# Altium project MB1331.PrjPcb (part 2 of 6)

## Sheet MCU.SchDoc: MCU STM32H7B3LIH6Q
size A3; Date: Not used; ApprovedBy: Not used; CheckedBy: Not used; Author: Not used; CompanyName: STMicroelectronics; DrawnBy: Not used; Engineer: Not used; Organization: Not used; Address1: Not used; Address2: Not used; Address3: Not used; Address4: Not used; DocumentNumber: Not used; Revision: Not used; SheetNumber: 3; SheetTotal: 23

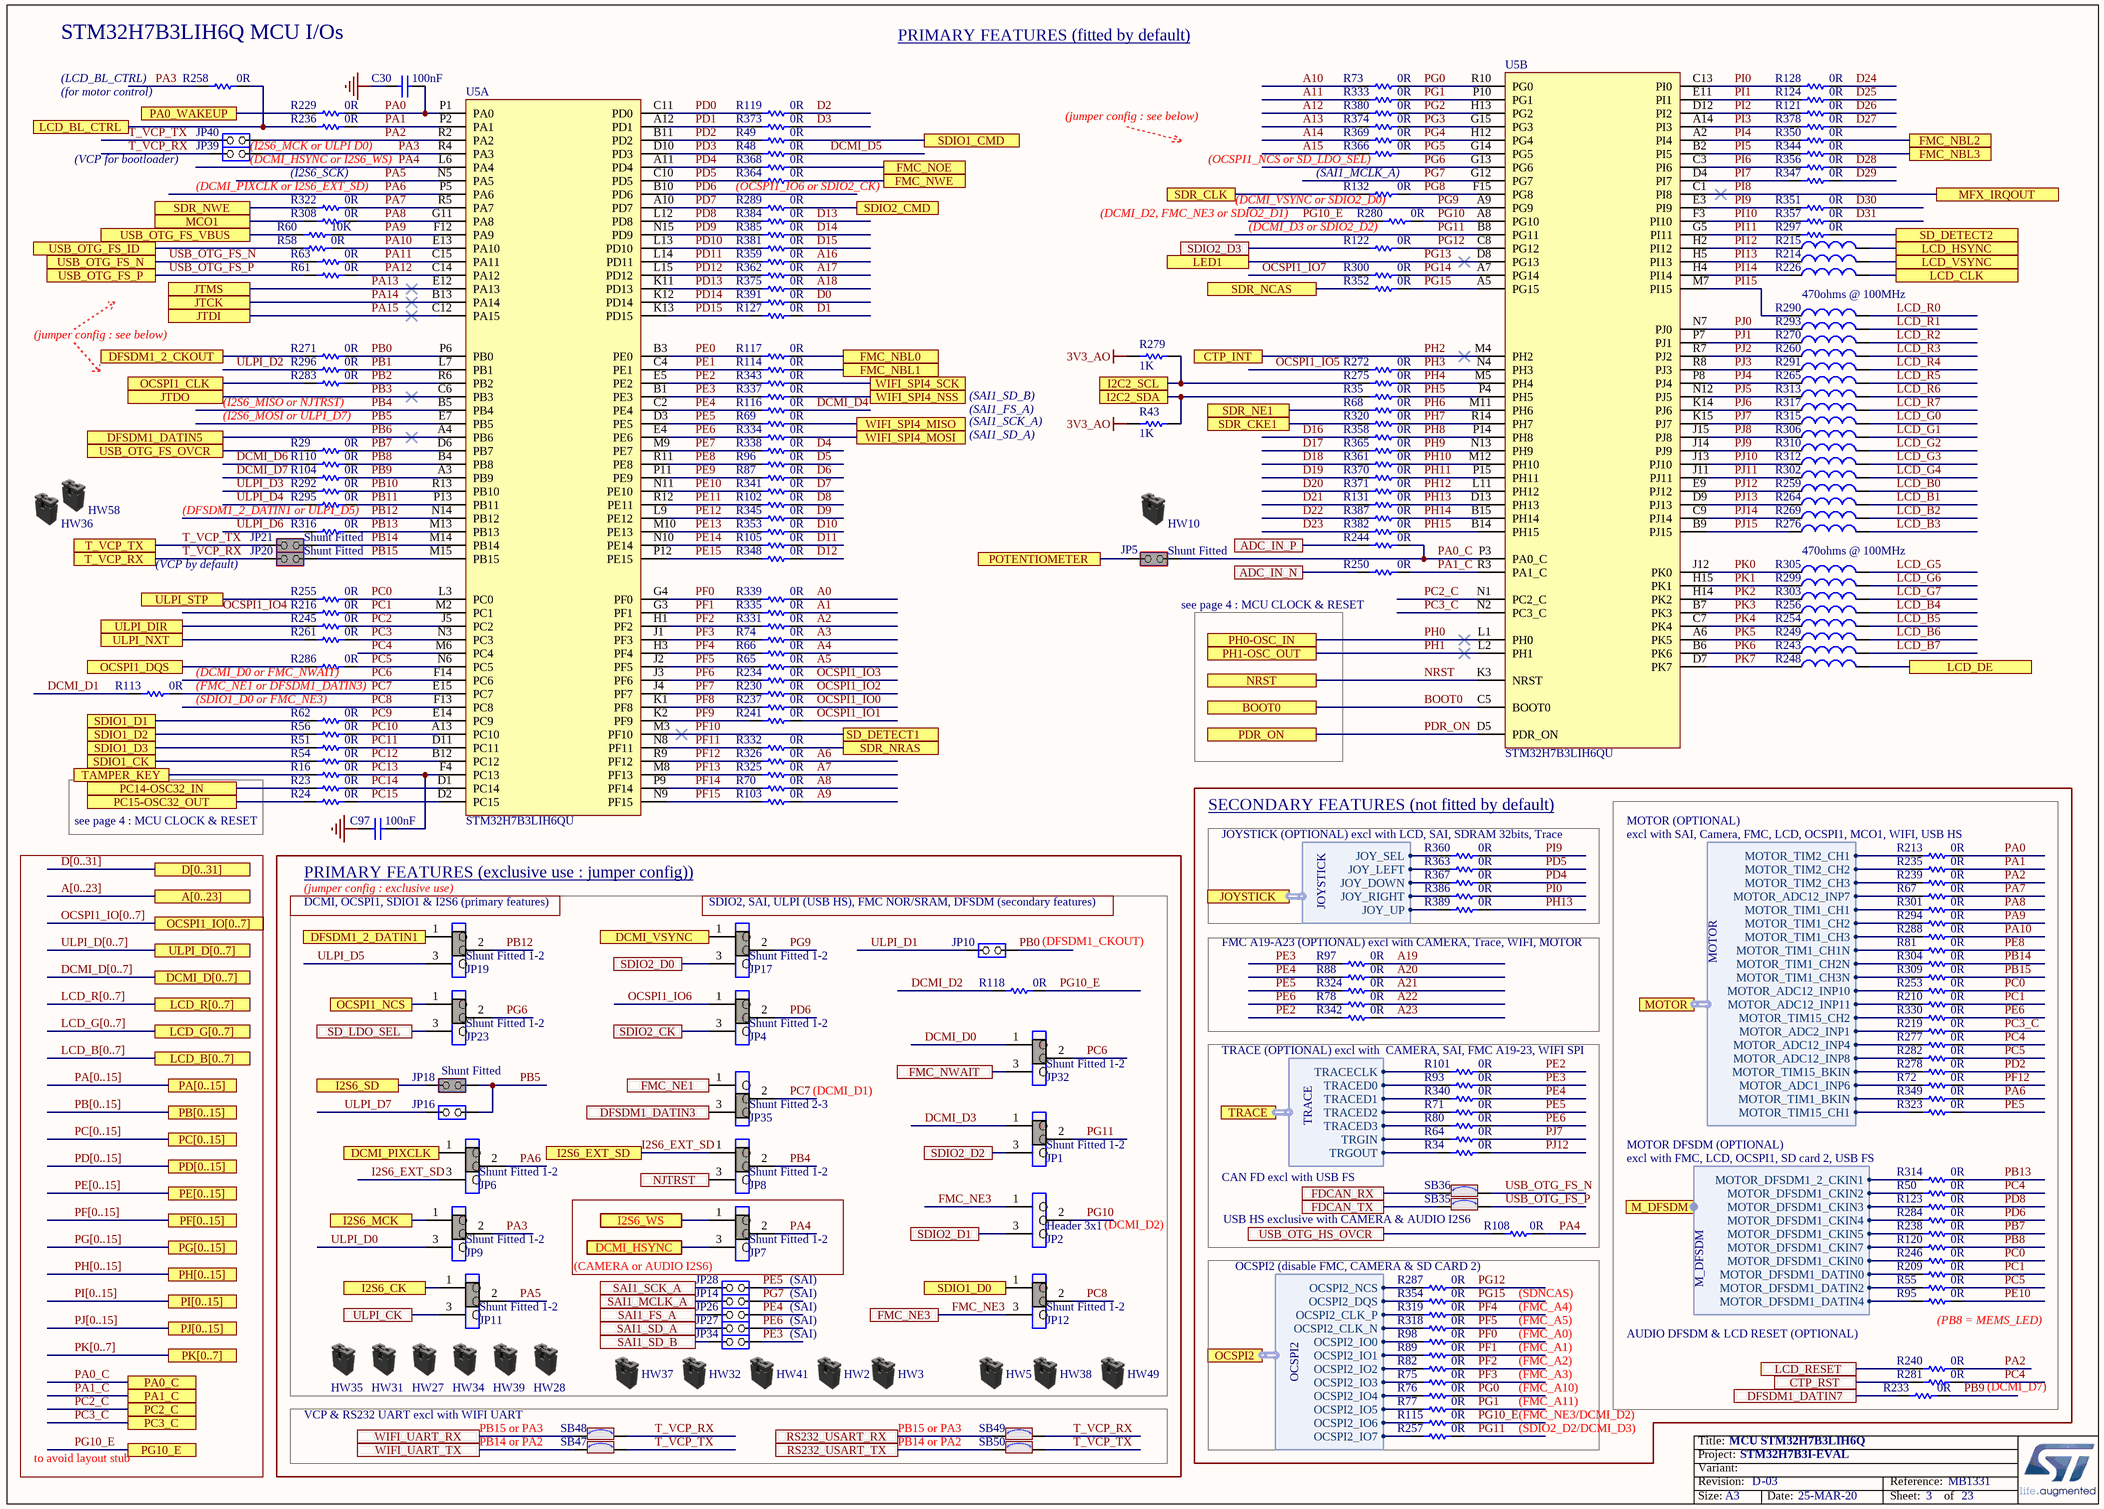
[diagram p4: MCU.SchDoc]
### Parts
C30  value 100nF  [C0402]  (hidden comment: Capacitor)
C97  value 100nF  [C0402]  (hidden comment: Capacitor)
HW2  Shunt Black 2.54mm  (value not drawn)  (mechanical)
HW3  Shunt Black 2.54mm  (value not drawn)  (mechanical)
HW5  Shunt Black 2.54mm  (value not drawn)  (mechanical)
HW10  Shunt Black 2.54mm  (value not drawn)  (mechanical)
HW27  Shunt Black 2.54mm  (value not drawn)  (mechanical)
HW28  Shunt Black 2.54mm  (value not drawn)  (mechanical)
HW31  Shunt Black 2.54mm  (value not drawn)  (mechanical)
HW32  Shunt Black 2.54mm  (value not drawn)  (mechanical)
HW34  Shunt Black 2.54mm  (value not drawn)  (mechanical)
HW35  Shunt Black 2.54mm  (value not drawn)  (mechanical)
HW36  Shunt Black 2.54mm  (value not drawn)  (mechanical)
HW37  Shunt Black 2.54mm  (value not drawn)  (mechanical)
HW38  Shunt Black 2.54mm  (value not drawn)  (mechanical)
HW39  Shunt Black 2.54mm  (value not drawn)  (mechanical)
HW41  Shunt Black 2.54mm  (value not drawn)  (mechanical)
HW49  Shunt Black 2.54mm  (value not drawn)  (mechanical)
HW58  Shunt Black 2.54mm  (value not drawn)  (mechanical)
JP1  value Shunt Fitted 1-2  [CON_SAMTEC_TSW-103-07-F-S]  (hidden comment: Jumper_Header 3x1 Fitted 1-2)
JP2  value Header 3x1  [CON_SAMTEC_TSW-103-07-F-S]  (hidden comment: Jumper_Header 3x1)
JP4  value Shunt Fitted 1-2  [CON_SAMTEC_TSW-103-07-F-S]  (hidden comment: Jumper_Header 3x1 Fitted 1-2)
JP5  value Shunt Fitted  [CON_SAMTEC_TSW-102-07-G-S]  (hidden comment: Jumper_Header 2x1 Fitted)
JP6  value Shunt Fitted 1-2  [CON_SAMTEC_TSW-103-07-F-S]  (hidden comment: Jumper_Header 3x1 Fitted 1-2)
JP7  value Shunt Fitted 1-2  [CON_SAMTEC_TSW-103-07-F-S]  (hidden comment: Jumper_Header 3x1 Fitted 1-2)
JP8  value Shunt Fitted 1-2  [CON_SAMTEC_TSW-103-07-F-S]  (hidden comment: Jumper_Header 3x1 Fitted 1-2)
JP9  value Shunt Fitted 1-2  [CON_SAMTEC_TSW-103-07-F-S]  (hidden comment: Jumper_Header 3x1 Fitted 1-2)
JP10  Jumper_Header 2x1  [CON_SAMTEC_TSW-102-07-G-S]  (value not drawn)
JP11  value Shunt Fitted 1-2  [CON_SAMTEC_TSW-103-07-F-S]  (hidden comment: Jumper_Header 3x1 Fitted 1-2)
JP12  value Shunt Fitted 1-2  [CON_SAMTEC_TSW-103-07-F-S]  (hidden comment: Jumper_Header 3x1 Fitted 1-2)
JP14  Jumper_Header 2x1  [CON_SAMTEC_TSW-102-07-G-S]  (value not drawn)
JP16  Jumper_Header 2x1  [CON_SAMTEC_TSW-102-07-G-S]  (value not drawn)
JP17  value Shunt Fitted 1-2  [CON_SAMTEC_TSW-103-07-F-S]  (hidden comment: Jumper_Header 3x1 Fitted 1-2)
JP18  value Shunt Fitted  [CON_SAMTEC_TSW-102-07-G-S]  (hidden comment: Jumper_Header 2x1 Fitted)
JP19  value Shunt Fitted 1-2  [CON_SAMTEC_TSW-103-07-F-S]  (hidden comment: Jumper_Header 3x1 Fitted 1-2)
JP20  value Shunt Fitted  [CON_SAMTEC_TSW-102-07-G-S]  (hidden comment: Jumper_Header 2x1 Fitted)
JP21  value Shunt Fitted  [CON_SAMTEC_TSW-102-07-G-S]  (hidden comment: Jumper_Header 2x1 Fitted)
JP23  value Shunt Fitted 1-2  [CON_SAMTEC_TSW-103-07-F-S]  (hidden comment: Jumper_Header 3x1 Fitted 1-2)
JP26  Jumper_Header 2x1  [CON_SAMTEC_TSW-102-07-G-S]  (value not drawn)
JP27  Jumper_Header 2x1  [CON_SAMTEC_TSW-102-07-G-S]  (value not drawn)
JP28  Jumper_Header 2x1  [CON_SAMTEC_TSW-102-07-G-S]  (value not drawn)
JP32  value Shunt Fitted 1-2  [CON_SAMTEC_TSW-103-07-F-S]  (hidden comment: Jumper_Header 3x1 Fitted 1-2)
JP34  Jumper_Header 2x1  [CON_SAMTEC_TSW-102-07-G-S]  (value not drawn)
JP35  value Shunt Fitted 2-3  [CON_SAMTEC_TSW-103-07-F-S]  (hidden comment: Jumper_Header 3x1 Fitted 2-3)
JP39  Jumper_Header 2x1  [CON_SAMTEC_TSW-102-07-G-S]  (value not drawn)
JP40  Jumper_Header 2x1  [CON_SAMTEC_TSW-102-07-G-S]  (value not drawn)
R16  value 0R  [R0402]  (hidden comment: Resistor)
R23  value 0R  [R0402]  (hidden comment: Resistor)
R24  value 0R  [R0402]  (hidden comment: Resistor)
R29  value 0R  [R0402]  (hidden comment: Resistor)
R34  value 0R  [R0402]  (hidden comment: Resistor)
R35  value 0R  [R0603]  (hidden comment: Resistor)
R43  value 1K  [R0402]  (hidden comment: Resistor)
R48  value 0R  [R0402]  (hidden comment: Resistor)
R49  value 0R  [R0402]  (hidden comment: Resistor)
R50  value 0R  [R0603]  (hidden comment: Resistor)
R51  value 0R  [R0402]  (hidden comment: Resistor)
R54  value 0R  [R0402]  (hidden comment: Resistor)
R55  value 0R  [R0603]  (hidden comment: Resistor)
R56  value 0R  [R0402]  (hidden comment: Resistor)
R58  value 0R  [R0402]  (hidden comment: Resistor)
R60  value 10K  [R0402]  (hidden comment: Resistor)
R61  value 0R  [R0402]  (hidden comment: Resistor)
R62  value 0R  [R0402]  (hidden comment: Resistor)
R63  value 0R  [R0402]  (hidden comment: Resistor)
R64  value 0R  [R0402]  (hidden comment: Resistor)
R65  value 0R  [R0402]  (hidden comment: Resistor)
R66  value 0R  [R0402]  (hidden comment: Resistor)
R67  value 0R  [R0603]  (hidden comment: Resistor)
R68  value 0R  [R0402]  (hidden comment: Resistor)
R69  value 0R  [R0402]  (hidden comment: Resistor)
R70  value 0R  [R0402]  (hidden comment: Resistor)
R71  value 0R  [R0402]  (hidden comment: Resistor)
R72  value 0R  [R0603]  (hidden comment: Resistor)
R73  value 0R  [R0402]  (hidden comment: Resistor)
R74  value 0R  [R0402]  (hidden comment: Resistor)
R75  value 0R  [R0402]  (hidden comment: Resistor)
R76  value 0R  [R0402]  (hidden comment: Resistor)
R77  value 0R  [R0402]  (hidden comment: Resistor)
R78  value 0R  [R0402]  (hidden comment: Resistor)
R80  value 0R  [R0402]  (hidden comment: Resistor)
R81  value 0R  [R0603]  (hidden comment: Resistor)
R82  value 0R  [R0402]  (hidden comment: Resistor)
R87  value 0R  [R0402]  (hidden comment: Resistor)
R88  value 0R  [R0402]  (hidden comment: Resistor)
R89  value 0R  [R0402]  (hidden comment: Resistor)
R93  value 0R  [R0402]  (hidden comment: Resistor)
R95  value 0R  [R0402]  (hidden comment: Resistor)
R96  value 0R  [R0402]  (hidden comment: Resistor)
R97  value 0R  [R0402]  (hidden comment: Resistor)
R98  value 0R  [R0402]  (hidden comment: Resistor)
R101  value 0R  [R0402]  (hidden comment: Resistor)
R102  value 0R  [R0402]  (hidden comment: Resistor)
R103  value 0R  [R0402]  (hidden comment: Resistor)
R104  value 0R  [R0402]  (hidden comment: Resistor)
R105  value 0R  [R0402]  (hidden comment: Resistor)
R108  value 0R  [R0402]  (hidden comment: Resistor)
R110  value 0R  [R0402]  (hidden comment: Resistor)
R113  value 0R  [R0402]  (hidden comment: Resistor)
R114  value 0R  [R0402]  (hidden comment: Resistor)
R115  value 0R  [R0402]  (hidden comment: Resistor)
R116  value 0R  [R0402]  (hidden comment: Resistor)
R117  value 0R  [R0402]  (hidden comment: Resistor)
R118  value 0R  [R0402]  (hidden comment: Resistor)
R119  value 0R  [R0402]  (hidden comment: Resistor)
R120  value 0R  [R0603]  (hidden comment: Resistor)
R121  value 0R  [R0402]  (hidden comment: Resistor)
R122  value 0R  [R0402]  (hidden comment: Resistor)
R123  value 0R  [R0603]  (hidden comment: Resistor)
R124  value 0R  [R0402]  (hidden comment: Resistor)
R127  value 0R  [R0402]  (hidden comment: Resistor)
R128  value 0R  [R0402]  (hidden comment: Resistor)
R131  value 0R  [R0402]  (hidden comment: Resistor)
R132  value 0R  [R0402]  (hidden comment: Resistor)
R209  value 0R  [R0603]  (hidden comment: Resistor)
R210  value 0R  [R0603]  (hidden comment: Resistor)
R213  value 0R  [R0603]  (hidden comment: Resistor)
R214  Inductor  [IND_0402_MURATA_BLM15H_H0P5]  (value not drawn)
R215  Inductor  [IND_0402_MURATA_BLM15H_H0P5]  (value not drawn)
R216  value 0R  [R0402]  (hidden comment: Resistor)
R219  value 0R  [R0603]  (hidden comment: Resistor)
R226  Inductor  [IND_0402_MURATA_BLM15H_H0P5]  (value not drawn)
R229  value 0R  [R0402]  (hidden comment: Resistor)
R230  value 0R  [R0402]  (hidden comment: Resistor)
R233  value 0R  [R0402]  (hidden comment: Resistor)
R234  value 0R  [R0402]  (hidden comment: Resistor)
R235  value 0R  [R0603]  (hidden comment: Resistor)
R236  value 0R  [R0402]  (hidden comment: Resistor)
R237  value 0R  [R0402]  (hidden comment: Resistor)
R238  value 0R  [R0603]  (hidden comment: Resistor)
R239  value 0R  [R0603]  (hidden comment: Resistor)
R240  value 0R  [R0402]  (hidden comment: Resistor)
R241  value 0R  [R0402]  (hidden comment: Resistor)
R243  Inductor  [IND_0402_MURATA_BLM15H_H0P5]  (value not drawn)
R244  value 0R  [R0402]  (hidden comment: Resistor)
R245  value 0R  [R0402]  (hidden comment: Resistor)
R246  value 0R  [R0603]  (hidden comment: Resistor)
R248  Inductor  [IND_0402_MURATA_BLM15H_H0P5]  (value not drawn)
R249  Inductor  [IND_0402_MURATA_BLM15H_H0P5]  (value not drawn)
R250  value 0R  [R0402]  (hidden comment: Resistor)
R253  value 0R  [R0603]  (hidden comment: Resistor)
R254  Inductor  [IND_0402_MURATA_BLM15H_H0P5]  (value not drawn)
R255  value 0R  [R0402]  (hidden comment: Resistor)
R256  Inductor  [IND_0402_MURATA_BLM15H_H0P5]  (value not drawn)
R257  value 0R  [R0402]  (hidden comment: Resistor)
R258  value 0R  [R0402]  (hidden comment: Resistor)
R259  Inductor  [IND_0402_MURATA_BLM15H_H0P5]  (value not drawn)
R260  Inductor  [IND_0402_MURATA_BLM15H_H0P5]  (value not drawn)
R261  value 0R  [R0402]  (hidden comment: Resistor)
R264  Inductor  [IND_0402_MURATA_BLM15H_H0P5]  (value not drawn)
R265  Inductor  [IND_0402_MURATA_BLM15H_H0P5]  (value not drawn)
R269  Inductor  [IND_0402_MURATA_BLM15H_H0P5]  (value not drawn)
R270  Inductor  [IND_0402_MURATA_BLM15H_H0P5]  (value not drawn)
R271  value 0R  [R0402]  (hidden comment: Resistor)
R272  value 0R  [R0402]  (hidden comment: Resistor)
R275  value 0R  [R0603]  (hidden comment: Resistor)
R276  Inductor  [IND_0402_MURATA_BLM15H_H0P5]  (value not drawn)
R277  value 0R  [R0603]  (hidden comment: Resistor)
R278  value 0R  [R0603]  (hidden comment: Resistor)
R279  value 1K  [R0402]  (hidden comment: Resistor)
R280  value 0R  [R0402]  (hidden comment: Resistor)
R281  value 0R  [R0402]  (hidden comment: Resistor)
R282  value 0R  [R0603]  (hidden comment: Resistor)
R283  value 0R  [R0402]  (hidden comment: Resistor)
R284  value 0R  [R0603]  (hidden comment: Resistor)
R286  value 0R  [R0402]  (hidden comment: Resistor)
R287  value 0R  [R0402]  (hidden comment: Resistor)
R288  value 0R  [R0603]  (hidden comment: Resistor)
R289  value 0R  [R0402]  (hidden comment: Resistor)
R290  value 470ohms @ 100MHz  [IND_0402_MURATA_BLM15H_H0P5]  (hidden comment: Inductor)
R291  Inductor  [IND_0402_MURATA_BLM15H_H0P5]  (value not drawn)
R292  value 0R  [R0402]  (hidden comment: Resistor)
R293  Inductor  [IND_0402_MURATA_BLM15H_H0P5]  (value not drawn)
R294  value 0R  [R0603]  (hidden comment: Resistor)
R295  value 0R  [R0402]  (hidden comment: Resistor)
R296  value 0R  [R0402]  (hidden comment: Resistor)
R297  value 0R  [R0402]  (hidden comment: Resistor)
R299  Inductor  [IND_0402_MURATA_BLM15H_H0P5]  (value not drawn)
R300  value 0R  [R0402]  (hidden comment: Resistor)
R301  value 0R  [R0603]  (hidden comment: Resistor)
R302  Inductor  [IND_0402_MURATA_BLM15H_H0P5]  (value not drawn)
R303  Inductor  [IND_0402_MURATA_BLM15H_H0P5]  (value not drawn)
R304  value 0R  [R0603]  (hidden comment: Resistor)
R305  value 470ohms @ 100MHz  [IND_0402_MURATA_BLM15H_H0P5]  (hidden comment: Inductor)
R306  Inductor  [IND_0402_MURATA_BLM15H_H0P5]  (value not drawn)
R308  value 0R  [R0402]  (hidden comment: Resistor)
R309  value 0R  [R0603]  (hidden comment: Resistor)
R310  Inductor  [IND_0402_MURATA_BLM15H_H0P5]  (value not drawn)
R312  Inductor  [IND_0402_MURATA_BLM15H_H0P5]  (value not drawn)
R313  Inductor  [IND_0402_MURATA_BLM15H_H0P5]  (value not drawn)
R314  value 0R  [R0603]  (hidden comment: Resistor)
R315  Inductor  [IND_0402_MURATA_BLM15H_H0P5]  (value not drawn)
R316  value 0R  [R0402]  (hidden comment: Resistor)
R317  Inductor  [IND_0402_MURATA_BLM15H_H0P5]  (value not drawn)
R318  value 0R  [R0402]  (hidden comment: Resistor)
R319  value 0R  [R0402]  (hidden comment: Resistor)
R320  value 0R  [R0402]  (hidden comment: Resistor)
R322  value 0R  [R0402]  (hidden comment: Resistor)
R323  value 0R  [R0603]  (hidden comment: Resistor)
R324  value 0R  [R0402]  (hidden comment: Resistor)
R325  value 0R  [R0402]  (hidden comment: Resistor)
R326  value 0R  [R0402]  (hidden comment: Resistor)
R330  value 0R  [R0603]  (hidden comment: Resistor)
R331  value 0R  [R0402]  (hidden comment: Resistor)
R332  value 0R  [R0402]  (hidden comment: Resistor)
R333  value 0R  [R0402]  (hidden comment: Resistor)
R334  value 0R  [R0402]  (hidden comment: Resistor)
R335  value 0R  [R0402]  (hidden comment: Resistor)
R337  value 0R  [R0402]  (hidden comment: Resistor)
R338  value 0R  [R0402]  (hidden comment: Resistor)
R339  value 0R  [R0402]  (hidden comment: Resistor)
R340  value 0R  [R0402]  (hidden comment: Resistor)
R341  value 0R  [R0402]  (hidden comment: Resistor)
R342  value 0R  [R0402]  (hidden comment: Resistor)
R343  value 0R  [R0402]  (hidden comment: Resistor)
R344  value 0R  [R0402]  (hidden comment: Resistor)
R345  value 0R  [R0402]  (hidden comment: Resistor)
R347  value 0R  [R0402]  (hidden comment: Resistor)
R348  value 0R  [R0402]  (hidden comment: Resistor)
R349  value 0R  [R0402]  (hidden comment: Resistor)
R350  value 0R  [R0402]  (hidden comment: Resistor)
R351  value 0R  [R0402]  (hidden comment: Resistor)
R352  value 0R  [R0402]  (hidden comment: Resistor)
R353  value 0R  [R0402]  (hidden comment: Resistor)
R354  value 0R  [R0402]  (hidden comment: Resistor)
R356  value 0R  [R0402]  (hidden comment: Resistor)
R357  value 0R  [R0402]  (hidden comment: Resistor)
R358  value 0R  [R0402]  (hidden comment: Resistor)
R359  value 0R  [R0402]  (hidden comment: Resistor)
R360  value 0R  [R0402]  (hidden comment: Resistor)
R361  value 0R  [R0402]  (hidden comment: Resistor)
R362  value 0R  [R0402]  (hidden comment: Resistor)
R363  value 0R  [R0402]  (hidden comment: Resistor)
R364  value 0R  [R0402]  (hidden comment: Resistor)
R365  value 0R  [R0402]  (hidden comment: Resistor)
R366  value 0R  [R0402]  (hidden comment: Resistor)
R367  value 0R  [R0402]  (hidden comment: Resistor)
R368  value 0R  [R0402]  (hidden comment: Resistor)
R369  value 0R  [R0402]  (hidden comment: Resistor)
R370  value 0R  [R0402]  (hidden comment: Resistor)
R371  value 0R  [R0402]  (hidden comment: Resistor)
R373  value 0R  [R0402]  (hidden comment: Resistor)
R374  value 0R  [R0402]  (hidden comment: Resistor)
R375  value 0R  [R0402]  (hidden comment: Resistor)
R378  value 0R  [R0402]  (hidden comment: Resistor)
R380  value 0R  [R0402]  (hidden comment: Resistor)
R381  value 0R  [R0402]  (hidden comment: Resistor)
R382  value 0R  [R0402]  (hidden comment: Resistor)
R384  value 0R  [R0402]  (hidden comment: Resistor)
R385  value 0R  [R0402]  (hidden comment: Resistor)
R386  value 0R  [R0402]  (hidden comment: Resistor)
R387  value 0R  [R0402]  (hidden comment: Resistor)
R389  value 0R  [R0402]  (hidden comment: Resistor)
R391  value 0R  [R0402]  (hidden comment: Resistor)
SB35  SB_ON  [SOLDER-BRIDGE_R0603-0R]  (value not drawn)
SB36  SB_ON  [SOLDER-BRIDGE_R0603-0R]  (value not drawn)
SB47  SB_ON  [SOLDER-BRIDGE_R0402-0R]  (value not drawn)
SB48  SB_ON  [SOLDER-BRIDGE_R0402-0R]  (value not drawn)
SB49  SB_ON  [SOLDER-BRIDGE_R0402-0R]  (value not drawn)
SB50  SB_ON  [SOLDER-BRIDGE_R0402-0R]  (value not drawn)
U5  value STM32H7B3LIH6QU  [ICC_TFBGA225_13X13_STM32H7B3NIH6Q_P080__SOCKET_IRONWOOD_CS1222291MF_REV-A_WITHOUT-3D-SOCKET]  (hidden comment: STM32H7B3NIH6Q)  (parts A,B of 3)

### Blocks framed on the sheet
SECONDARY FEATURES (not fitted by default): R360 R363 R367 R386 R389
PRIMARY FEATURES (exclusive use : jumper config)): HW2 HW3 HW5 HW27 HW28 HW31 HW32 HW34 HW35 HW37-HW39 HW41 HW49 JP1 JP2 JP4 JP6 JP8-JP12 JP14 JP16-JP19 JP23 JP26-JP28 JP32 JP34 JP35 R118
FMC A19-A23 (OPTIONAL) excl with CAMERA, Trace, WIFI, MOTOR: R78 R88 R97 R324 R342
(CAMERA or AUDIO I2S6): JP7

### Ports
A[0..23], ADC_IN_N, ADC_IN_P, BOOT0, CTP_INT, CTP_RST, D[0..31], DCMI_D[0..7], DCMI_HSYNC, DCMI_PIXCLK, DCMI_VSYNC, DFSDM1_2_CKOUT, DFSDM1_2_DATIN1, DFSDM1_DATIN3, DFSDM1_DATIN5, DFSDM1_DATIN7, FDCAN_RX, FDCAN_TX, FMC_NBL0, FMC_NBL1, FMC_NBL2, FMC_NBL3, FMC_NE1, FMC_NE3, FMC_NOE, FMC_NWAIT, FMC_NWE, I2C2_SCL, I2C2_SDA, I2S6_CK, I2S6_EXT_SD, I2S6_MCK, I2S6_SD, I2S6_WS, JOYSTICK (harness JOYSTICK), JTCK, JTDI, JTDO, JTMS, LCD_B[0..7], LCD_BL_CTRL, LCD_CLK, LCD_DE, LCD_G[0..7], LCD_HSYNC, LCD_R[0..7], LCD_RESET, LCD_VSYNC, LED1, M_DFSDM (harness M_DFSDM), MCO1, MFX_IRQOUT, MOTOR (harness MOTOR), NJTRST, NRST, OCSPI1_CLK, OCSPI1_DQS, OCSPI1_IO[0..7], OCSPI1_NCS, OCSPI2 (harness OCSPI2), PA0_C, PA0_WAKEUP, PA1_C, PA[0..15], PB[0..15], PC2_C, PC3_C, PC14-OSC32_IN, PC15-OSC32_OUT, PC[0..15], PD[0..15], PDR_ON, PE[0..15], PF[0..15], PG10_E, PG[0..15], PH0-OSC_IN, PH1-OSC_OUT, PH[0..15], PI[0..15], PJ[0..15], PK[0..7], POTENTIOMETER, RS232_USART_RX, RS232_USART_TX, SAI1_FS_A, SAI1_MCLK_A, SAI1_SCK_A, SAI1_SD_A, SAI1_SD_B, SD_DETECT1, SD_DETECT2, SD_LDO_SEL, SDIO1_CK, SDIO1_CMD, SDIO1_D0, SDIO1_D1, SDIO1_D2, SDIO1_D3, SDIO2_CK, SDIO2_CMD, SDIO2_D0, SDIO2_D1, SDIO2_D2, SDIO2_D3, SDR_CKE1, SDR_CLK, SDR_NCAS, SDR_NE1, SDR_NRAS, SDR_NWE, T_VCP_RX, T_VCP_TX, TAMPER_KEY, TRACE (harness TRACE), ULPI_CK, ULPI_D[0..7], ULPI_DIR, ULPI_NXT, ULPI_STP, USB_OTG_FS_ID, USB_OTG_FS_N, USB_OTG_FS_OVCR, USB_OTG_FS_P, USB_OTG_FS_VBUS, USB_OTG_HS_OVCR, WIFI_SPI4_MISO, WIFI_SPI4_MOSI, WIFI_SPI4_NSS, WIFI_SPI4_SCK, WIFI_UART_RX, WIFI_UART_TX

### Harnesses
MOTOR: MOTOR_TIM2_CH1, MOTOR_TIM2_CH2, MOTOR_TIM2_CH3, MOTOR_ADC12_INP7, MOTOR_TIM1_CH1, MOTOR_TIM1_CH2, MOTOR_TIM1_CH3, MOTOR_TIM1_CH1N, MOTOR_TIM1_CH2N, MOTOR_TIM1_CH3N, MOTOR_ADC12_INP10, MOTOR_ADC12_INP11, MOTOR_TIM15_CH2, MOTOR_ADC2_INP1, MOTOR_ADC12_INP4, MOTOR_ADC12_INP8, MOTOR_TIM15_BKIN, MOTOR_ADC1_INP6, MOTOR_TIM1_BKIN, MOTOR_TIM15_CH1
OCSPI2: OCSPI2_NCS, OCSPI2_DQS, OCSPI2_CLK_P, OCSPI2_CLK_N, OCSPI2_IO0, OCSPI2_IO1, OCSPI2_IO2, OCSPI2_IO3, OCSPI2_IO4, OCSPI2_IO5, OCSPI2_IO6, OCSPI2_IO7
TRACE: TRACECLK, TRACED0, TRACED1, TRACED2, TRACED3, TRGIN, TRGOUT
JOYSTICK: JOY_SEL, JOY_LEFT, JOY_DOWN, JOY_RIGHT, JOY_UP
M_DFSDM: MOTOR_DFSDM1_2_CKIN1, MOTOR_DFSDM1_CKIN3, MOTOR_DFSDM1_CKIN5, MOTOR_DFSDM1_CKIN7, MOTOR_DFSDM1_CKIN2, MOTOR_DFSDM1_CKIN4, MOTOR_DFSDM1_CKIN0, MOTOR_DFSDM1_DATIN0, MOTOR_DFSDM1_DATIN2, MOTOR_DFSDM1_DATIN4

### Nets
3V3_AO: R43.1 R279.1
GND: C30.2 C97.2
A0: R339.2
A1: R335.2
A2: R331.2
A3: R74.2
A4: R66.2
A5: R65.2
A6: R326.2
A7: R325.2
A8: R70.2
A9: R103.2
A10: R73.1
A11: R333.1
A12: R380.1
A13: R374.1
A14: R369.1
A15: R366.1
A16: R359.2
A17: R362.2
A18: R375.2
A19: R97.2
A20: R88.2
A21: R324.2
A22: R78.2
A23: R342.2
ADC_IN_N: R250.1 ; port ADC_IN_N
ADC_IN_P: R244.1 ; port ADC_IN_P
BOOT0: U5.C5(BOOT0) ; port BOOT0
CTP_RST: R281.1 ; port CTP_RST
D0: R391.2
D1: R127.2
D2: R119.2
D3: R373.2
D4: R338.2
D5: R96.2
D6: R87.2
D7: R341.2
D8: R102.2
D9: R345.2
D10: R353.2
D11: R105.2
D12: R348.2
D13: R384.2
D14: R385.2
D15: R381.2
D16: R358.1
D17: R365.1
D18: R361.1
D19: R370.1
D20: R371.1
D21: R131.1
D22: R387.1
D23: R382.1
D24: R128.2
D25: R124.1
D26: R121.1
D27: R378.1
D28: R356.1
D29: R347.1
D30: R351.2
D31: R357.2
DCMI_D0: JP32.1
DCMI_D1: R113.1
DCMI_D2: R118.1
DCMI_D3: JP1.1
DCMI_D4: R116.1
DCMI_D5: R48.2
DCMI_D6: R110.2
DCMI_D7: R104.1
DCMI_HSYNC: JP7.3 ; port DCMI_HSYNC
DCMI_PIXCLK: JP6.1 ; port DCMI_PIXCLK
DCMI_VSYNC: JP17.1 ; port DCMI_VSYNC
DFSDM1_2_CKOUT: R271.1 ; port DFSDM1_2_CKOUT
DFSDM1_2_DATIN1: JP19.1 ; port DFSDM1_2_DATIN1
DFSDM1_DATIN3: JP35.3 ; port DFSDM1_DATIN3
DFSDM1_DATIN7: R233.2 ; port DFSDM1_DATIN7
FDCAN_RX: SB36.1 ; port FDCAN_RX
FDCAN_TX: SB35.1 ; port FDCAN_TX
FMC_NBL0: R117.2 ; port FMC_NBL0
FMC_NBL1: R114.2 ; port FMC_NBL1
FMC_NBL2: R350.2 ; port FMC_NBL2
FMC_NBL3: R344.2 ; port FMC_NBL3
FMC_NE1: JP35.1 ; port FMC_NE1
FMC_NE3: JP2.1 JP12.3 ; port FMC_NE3
FMC_NOE: R368.2 ; port FMC_NOE
FMC_NWAIT: JP32.3 ; port FMC_NWAIT
FMC_NWE: R364.2 ; port FMC_NWE
I2C2_SCL: R275.1 R279.2 ; port I2C2_SCL
I2C2_SDA: R35.1 R43.2 ; port I2C2_SDA
I2S6_CK: JP11.1 ; port I2S6_CK
I2S6_EXT_SD: JP6.3 JP8.1 ; port I2S6_EXT_SD
I2S6_MCK: JP9.1 ; port I2S6_MCK
I2S6_SD: JP18.2(NO) ; port I2S6_SD
I2S6_WS: JP7.1 ; port I2S6_WS
LCD_B0: R259.2
LCD_B1: R264.2
LCD_B2: R269.2
LCD_B3: R276.2
LCD_B4: R256.2
LCD_B5: R254.2
LCD_B6: R249.2
LCD_B7: R243.2
LCD_BL_CTRL: R236.1 R258.2 ; port LCD_BL_CTRL
LCD_CLK: R226.2 ; port LCD_CLK
LCD_DE: R248.2 ; port LCD_DE
LCD_G0: R315.2
LCD_G1: R306.2
LCD_G2: R310.2
LCD_G3: R312.2
LCD_G4: R302.2
LCD_G5: R305.2
LCD_G6: R299.2
LCD_G7: R303.2
LCD_HSYNC: R215.2 ; port LCD_HSYNC
LCD_R0: R290.2
LCD_R1: R293.2
LCD_R2: R270.2
LCD_R3: R260.2
LCD_R4: R291.2
LCD_R5: R265.2
LCD_R6: R313.2
LCD_R7: R317.2
LCD_RESET: R240.1 ; port LCD_RESET
LCD_VSYNC: R214.2 ; port LCD_VSYNC
MCO1: R308.1 ; port MCO1
MOTOR_ADC1_INP6: R72.1 ; port MOTOR.MOTOR_ADC1_INP6
MOTOR_ADC2_INP1: R219.1 ; port MOTOR.MOTOR_ADC2_INP1
MOTOR_ADC12_INP4: R277.1 ; port MOTOR.MOTOR_ADC12_INP4
MOTOR_ADC12_INP7: R67.1 ; port MOTOR.MOTOR_ADC12_INP7
MOTOR_ADC12_INP8: R282.1 ; port MOTOR.MOTOR_ADC12_INP8
MOTOR_ADC12_INP10: R253.1 ; port MOTOR.MOTOR_ADC12_INP10
MOTOR_ADC12_INP11: R210.1 ; port MOTOR.MOTOR_ADC12_INP11
MOTOR_DFSDM1_2_CKIN1: R314.1 ; port M_DFSDM.MOTOR_DFSDM1_2_CKIN1
MOTOR_DFSDM1_CKIN0: R246.1 ; port M_DFSDM.MOTOR_DFSDM1_CKIN0
MOTOR_DFSDM1_CKIN2: R50.1 ; port M_DFSDM.MOTOR_DFSDM1_CKIN2
MOTOR_DFSDM1_CKIN3: R123.1 ; port M_DFSDM.MOTOR_DFSDM1_CKIN3
MOTOR_DFSDM1_CKIN4: R284.1 ; port M_DFSDM.MOTOR_DFSDM1_CKIN4
MOTOR_DFSDM1_CKIN5: R238.1 ; port M_DFSDM.MOTOR_DFSDM1_CKIN5
MOTOR_DFSDM1_CKIN7: R120.1 ; port M_DFSDM.MOTOR_DFSDM1_CKIN7
MOTOR_DFSDM1_DATIN0: R209.1 ; port M_DFSDM.MOTOR_DFSDM1_DATIN0
MOTOR_DFSDM1_DATIN2: R55.1 ; port M_DFSDM.MOTOR_DFSDM1_DATIN2
MOTOR_DFSDM1_DATIN4: R95.1 ; port M_DFSDM.MOTOR_DFSDM1_DATIN4
MOTOR_TIM1_BKIN: R349.1 ; port MOTOR.MOTOR_TIM1_BKIN
MOTOR_TIM1_CH1: R301.1 ; port MOTOR.MOTOR_TIM1_CH1
MOTOR_TIM1_CH1N: R81.1 ; port MOTOR.MOTOR_TIM1_CH1N
MOTOR_TIM1_CH2: R294.1 ; port MOTOR.MOTOR_TIM1_CH2
MOTOR_TIM1_CH2N: R304.1 ; port MOTOR.MOTOR_TIM1_CH2N
MOTOR_TIM1_CH3: R288.1 ; port MOTOR.MOTOR_TIM1_CH3
MOTOR_TIM1_CH3N: R309.1 ; port MOTOR.MOTOR_TIM1_CH3N
MOTOR_TIM2_CH1: R213.1 ; port MOTOR.MOTOR_TIM2_CH1
MOTOR_TIM2_CH2: R235.1 ; port MOTOR.MOTOR_TIM2_CH2
MOTOR_TIM2_CH3: R239.1 ; port MOTOR.MOTOR_TIM2_CH3
MOTOR_TIM15_BKIN: R278.1 ; port MOTOR.MOTOR_TIM15_BKIN
MOTOR_TIM15_CH1: R323.1 ; port MOTOR.MOTOR_TIM15_CH1
MOTOR_TIM15_CH2: R330.1 ; port MOTOR.MOTOR_TIM15_CH2
NJTRST: JP8.3 ; port NJTRST
NRST: U5.K3(NRST) ; port NRST
OCSPI1_CLK: R283.1 ; port OCSPI1_CLK
OCSPI1_DQS: R286.1 ; port OCSPI1_DQS
OCSPI1_IO0: R237.2
OCSPI1_IO1: R241.2
OCSPI1_IO2: R230.2
OCSPI1_IO3: R234.2
OCSPI1_IO4: R216.1
OCSPI1_IO5: R272.1
OCSPI1_IO6: JP4.1
OCSPI1_IO7: R300.1
OCSPI1_NCS: JP23.1 ; port OCSPI1_NCS
OCSPI2_CLK_N: R318.1 ; port OCSPI2.OCSPI2_CLK_N
OCSPI2_CLK_P: R319.1 ; port OCSPI2.OCSPI2_CLK_P
OCSPI2_DQS: R354.1 ; port OCSPI2.OCSPI2_DQS
OCSPI2_IO0: R98.1 ; port OCSPI2.OCSPI2_IO0
OCSPI2_IO1: R89.1 ; port OCSPI2.OCSPI2_IO1
OCSPI2_IO2: R82.1 ; port OCSPI2.OCSPI2_IO2
OCSPI2_IO3: R75.1 ; port OCSPI2.OCSPI2_IO3
OCSPI2_IO4: R76.1 ; port OCSPI2.OCSPI2_IO4
OCSPI2_IO5: R77.1 ; port OCSPI2.OCSPI2_IO5
OCSPI2_IO6: R115.1 ; port OCSPI2.OCSPI2_IO6
OCSPI2_IO7: R257.1 ; port OCSPI2.OCSPI2_IO7
OCSPI2_NCS: R287.1 ; port OCSPI2.OCSPI2_NCS
PA0: C30.1 R213.2 R229.2 U5.P1(PA0)
PA0_C: JP5.2(NO) R244.2 U5.P3(PA0_C) ; port PA0_C
PA0_WAKEUP: R229.1 ; port PA0_WAKEUP
PA1: R235.2 R236.2 U5.P2(PA1)
PA1_C: R250.2 U5.R3(PA1_C) ; port PA1_C
PA2: JP40.2(NO) R239.2 R240.2 U5.R2(PA2)
PA3: JP9.2 JP39.2(NO) R258.1 U5.R4(PA3)
PA4: JP7.2 R108.2 U5.L6(PA4)
PA5: JP11.2 U5.N5(PA5)
PA6: JP6.2 R349.2 U5.P5(PA6)
PA7: R67.2 R322.2 U5.R5(PA7)
PA8: R301.2 R308.2 U5.G11(PA8)
PA9: R60.2 R294.2 U5.F12(PA9)
PA10: R58.2 R288.2 U5.E13(PA10)
PA11: R63.2 U5.C15(PA11)
PA12: R61.2 U5.C14(PA12)
PA13: U5.E12(PA13) ; port JTMS
PA14: U5.B13(PA14) ; port JTCK
PA15: U5.C12(PA15) ; port JTDI
PB0: JP10.1(COMMON) R271.2 U5.P6(PB0)
PB1: R296.2 U5.L7(PB1)
PB2: R283.2 U5.R6(PB2)
PB3: U5.C6(PB3) ; port JTDO
PB4: JP8.2 U5.B5(PB4)
PB5: JP16.2(NO) JP18.1(COMMON) U5.E7(PB5)
PB6: U5.A4(PB6) ; port DFSDM1_DATIN5  [project net DFSDM1_DATIN5]
PB7: R29.2 R238.2 U5.D6(PB7)
PB8: R110.1 R120.2 U5.B4(PB8)
PB9: R104.2 R233.1 U5.A3(PB9)
PB10: R292.2 U5.R13(PB10)
PB11: R295.2 U5.P13(PB11)
PB12: JP19.2 U5.N14(PB12)
PB13: R314.2 R316.2 U5.M13(PB13)
PB14: JP21.2(NO) R304.2 U5.M14(PB14)
PB15: JP20.2(NO) R309.2 U5.M15(PB15)
PC0: R246.2 R253.2 R255.2 U5.L3(PC0)
PC1: R209.2 R210.2 R216.2 U5.M2(PC1)
PC2: R245.2 U5.J5(PC2)
PC2_C: U5.N1(PC2_C) ; port PC2_C
PC3: R261.2 U5.N3(PC3)
PC3_C: R219.2 U5.N2(PC3_C) ; port PC3_C
PC4: R50.2 R277.2 R281.2 U5.M6(PC4)
PC5: R55.2 R282.2 R286.2 U5.N6(PC5)
PC6: JP32.2 U5.F14(PC6)
PC7: JP35.2 R113.2 U5.E15(PC7)
PC8: JP12.2 U5.F13(PC8)
PC9: R62.2 U5.E14(PC9)
PC10: R56.2 U5.A13(PC10)
PC11: R51.2 U5.D11(PC11)
PC12: R54.2 U5.B12(PC12)
PC13: C97.1 R16.2 U5.F4(PC13)
PC14: R23.2 U5.D1(PC14)
PC14-OSC32_IN: R23.1 ; port PC14-OSC32_IN
PC15: R24.2 U5.D2(PC15)
PC15-OSC32_OUT: R24.1 ; port PC15-OSC32_OUT
PD0: R119.1 U5.C11(PD0)
PD1: R373.1 U5.A12(PD1)
PD2: R49.1 R278.2 U5.B11(PD2)
PD3: R48.1 U5.D10(PD3)
PD4: R367.2 R368.1 U5.A11(PD4)
PD5: R363.2 R364.1 U5.C10(PD5)
PD6: JP4.2 R284.2 U5.B10(PD6)
PD7: R289.1 U5.A10(PD7)
PD8: R123.2 R384.1 U5.L12(PD8)
PD9: R385.1 U5.N15(PD9)
PD10: R381.1 U5.L13(PD10)
PD11: R359.1 U5.L14(PD11)
PD12: R362.1 U5.L15(PD12)
PD13: R375.1 U5.K11(PD13)
PD14: R391.1 U5.K12(PD14)
PD15: R127.1 U5.K13(PD15)
PDR_ON: U5.D5(PDR_ON) ; port PDR_ON
PE0: R117.1 U5.B3(PE0)
PE1: R114.1 U5.C4(PE1)
PE2: R101.2 R342.1 R343.2 U5.E5(PE2)
PE3: JP34.1(COMMON) R93.2 R97.1 R337.2 U5.B1(PE3)
PE4: JP26.1(COMMON) R88.1 R116.2 R340.2 U5.C2(PE4)
PE5: JP28.1(COMMON) R69.2 R71.2 R323.2 R324.1 U5.D3(PE5)
PE6: JP27.1(COMMON) R78.1 R80.2 R330.2 R334.2 U5.E4(PE6)
PE7: R338.1 U5.M9(PE7)
PE8: R81.2 R96.1 U5.R11(PE8)
PE9: R87.1 U5.P11(PE9)
PE10: R95.2 R341.1 U5.N11(PE10)
PE11: R102.1 U5.R12(PE11)
PE12: R345.1 U5.L9(PE12)
PE13: R353.1 U5.M10(PE13)
PE14: R105.1 U5.N10(PE14)
PE15: R348.1 U5.P12(PE15)
PF0: R98.2 R339.1 U5.G4(PF0)
PF1: R89.2 R335.1 U5.G3(PF1)
PF2: R82.2 R331.1 U5.H1(PF2)
PF3: R74.1 R75.2 U5.J1(PF3)
PF4: R66.1 R319.2 U5.H3(PF4)
PF5: R65.1 R318.2 U5.J2(PF5)
PF6: R234.1 U5.J3(PF6)
PF7: R230.1 U5.J4(PF7)
PF8: R237.1 U5.K1(PF8)
PF9: R241.1 U5.K2(PF9)
PF10: U5.M3(PF10) ; port SD_DETECT1
PF11: R332.1 U5.N8(PF11)
PF12: R72.2 R326.1 U5.R9(PF12)
PF13: R325.1 U5.M8(PF13)
PF14: R70.1 U5.P9(PF14)
PF15: R103.1 U5.N9(PF15)
PG0: R73.2 R76.2 U5.R10(PG0)
PG1: R77.2 R333.2 U5.P10(PG1)
PG2: R380.2 U5.H13(PG2)
PG3: R374.2 U5.G15(PG3)
PG4: R369.2 U5.H12(PG4)
PG5: R366.2 U5.G14(PG5)
PG6: JP23.2 U5.G13(PG6)
PG7: JP14.1(COMMON) U5.G12(PG7)
PG8: R132.2 U5.F15(PG8)
PG9: JP17.2 U5.A9(PG9)
PG10: JP2.2 R280.2 U5.A8(PG10)
PG10_E: R115.2 R118.2 R280.1 ; port PG10_E
PG11: JP1.2 R257.2 U5.B8(PG11)
PG12: R122.2 R287.2 U5.C8(PG12)
PG13: U5.D8(PG13) ; port LED1
PG14: R300.2 U5.A7(PG14)
PG15: R352.2 R354.2 U5.A5(PG15)
PH0: U5.L1(PH0) ; port PH0-OSC_IN
PH1: U5.L2(PH1) ; port PH1-OSC_OUT
PH2: U5.M4(PH2) ; port CTP_INT  [project net CTP_INT]
PH3: R272.2 U5.N4(PH3)
PH4: R275.2 U5.M5(PH4)
PH5: R35.2 U5.P4(PH5)
PH6: R68.2 U5.M11(PH6)
PH7: R320.2 U5.R14(PH7)
PH8: R358.2 U5.P14(PH8)
PH9: R365.2 U5.N13(PH9)
PH10: R361.2 U5.M12(PH10)
PH11: R370.2 U5.P15(PH11)
PH12: R371.2 U5.L11(PH12)
PH13: R131.2 R389.2 U5.D13(PH13)
PH14: R387.2 U5.B15(PH14)
PH15: R382.2 U5.B14(PH15)
PI0: R128.1 R386.2 U5.C13(PI0)
PI1: R124.2 U5.E11(PI1)
PI2: R121.2 U5.D12(PI2)
PI3: R378.2 U5.A14(PI3)
PI4: R350.1 U5.A2(PI4)
PI5: R344.1 U5.B2(PI5)
PI6: R356.2 U5.C3(PI6)
PI7: R347.2 U5.D4(PI7)
PI8: U5.C1(PI8) ; port MFX_IRQOUT
PI9: R351.1 R360.2 U5.E3(PI9)
PI10: R357.1 U5.F3(PI10)
PI11: R297.1 U5.G5(PI11)
PI12: R215.1 U5.H2(PI12)
PI13: R214.1 U5.H5(PI13)
PI14: R226.1 U5.H4(PI14)
PI15: R290.1 U5.M7(PI15)
PJ0: R293.1 U5.N7(PJ0)
PJ1: R270.1 U5.P7(PJ1)
PJ2: R260.1 U5.R7(PJ2)
PJ3: R291.1 U5.R8(PJ3)
PJ4: R265.1 U5.P8(PJ4)
PJ5: R313.1 U5.N12(PJ5)
PJ6: R317.1 U5.K14(PJ6)
PJ7: R64.2 R315.1 U5.K15(PJ7)
PJ8: R306.1 U5.J15(PJ8)
PJ9: R310.1 U5.J14(PJ9)
PJ10: R312.1 U5.J13(PJ10)
PJ11: R302.1 U5.J11(PJ11)
PJ12: R34.2 R259.1 U5.E9(PJ12)
PJ13: R264.1 U5.D9(PJ13)
PJ14: R269.1 U5.C9(PJ14)
PJ15: R276.1 U5.B9(PJ15)
PK0: R305.1 U5.J12(PK0)
PK1: R299.1 U5.H15(PK1)
PK2: R303.1 U5.H14(PK2)
PK3: R256.1 U5.B7(PK3)
PK4: R254.1 U5.C7(PK4)
PK5: R249.1 U5.A6(PK5)
PK6: R243.1 U5.B6(PK6)
PK7: R248.1 U5.D7(PK7)
POTENTIOMETER: JP5.1(COMMON) ; port POTENTIOMETER
RS232_USART_RX: SB49.1 ; port RS232_USART_RX
RS232_USART_TX: SB50.1 ; port RS232_USART_TX
SAI1_FS_A: JP26.2(NO) ; port SAI1_FS_A
SAI1_MCLK_A: JP14.2(NO) ; port SAI1_MCLK_A
SAI1_SCK_A: JP28.2(NO) ; port SAI1_SCK_A
SAI1_SD_A: JP27.2(NO) ; port SAI1_SD_A
SAI1_SD_B: JP34.2(NO) ; port SAI1_SD_B
SD_DETECT2: R297.2 ; port SD_DETECT2
SD_LDO_SEL: JP23.3 ; port SD_LDO_SEL
SDIO1_CK: R54.1 ; port SDIO1_CK
SDIO1_CMD: R49.2 ; port SDIO1_CMD
SDIO1_D0: JP12.1 ; port SDIO1_D0
SDIO1_D1: R62.1 ; port SDIO1_D1
SDIO1_D2: R56.1 ; port SDIO1_D2
SDIO1_D3: R51.1 ; port SDIO1_D3
SDIO2_CK: JP4.3 ; port SDIO2_CK
SDIO2_CMD: R289.2 ; port SDIO2_CMD
SDIO2_D0: JP17.3 ; port SDIO2_D0
SDIO2_D1: JP2.3 ; port SDIO2_D1
SDIO2_D2: JP1.3 ; port SDIO2_D2
SDIO2_D3: R122.1 ; port SDIO2_D3
SDR_CKE1: R320.1 ; port SDR_CKE1
SDR_CLK: R132.1 ; port SDR_CLK
SDR_NCAS: R352.1 ; port SDR_NCAS
SDR_NE1: R68.1 ; port SDR_NE1
SDR_NRAS: R332.2 ; port SDR_NRAS
SDR_NWE: R322.1 ; port SDR_NWE
T_VCP_RX: JP20.1(COMMON) JP39.1(COMMON) SB48.2 SB49.2 ; port T_VCP_RX
T_VCP_TX: JP21.1(COMMON) JP40.1(COMMON) SB47.2 SB50.2 ; port T_VCP_TX
TAMPER_KEY: R16.1 ; port TAMPER_KEY
TRACECLK: R101.1 ; port TRACE.TRACECLK
TRACED0: R93.1 ; port TRACE.TRACED0
TRACED1: R340.1 ; port TRACE.TRACED1
TRACED2: R71.1 ; port TRACE.TRACED2
TRACED3: R80.1 ; port TRACE.TRACED3
TRGIN: R64.1 ; port TRACE.TRGIN
TRGOUT: R34.1 ; port TRACE.TRGOUT
ULPI_CK: JP11.3 ; port ULPI_CK
ULPI_D0: JP9.3
ULPI_D1: JP10.2(NO)
ULPI_D2: R296.1
ULPI_D3: R292.1
ULPI_D4: R295.1
ULPI_D5: JP19.3
ULPI_D6: R316.1
ULPI_D7: JP16.1(COMMON)
ULPI_DIR: R245.1 ; port ULPI_DIR
ULPI_NXT: R261.1 ; port ULPI_NXT
ULPI_STP: R255.1 ; port ULPI_STP
USB_OTG_FS_ID: R58.1 ; port USB_OTG_FS_ID
USB_OTG_FS_N: R63.1 SB36.2 ; port USB_OTG_FS_N
USB_OTG_FS_OVCR: R29.1 ; port USB_OTG_FS_OVCR
USB_OTG_FS_P: R61.1 SB35.2 ; port USB_OTG_FS_P
USB_OTG_FS_VBUS: R60.1 ; port USB_OTG_FS_VBUS
USB_OTG_HS_OVCR: R108.1 ; port USB_OTG_HS_OVCR
WIFI_SPI4_MISO: R69.1 ; port WIFI_SPI4_MISO
WIFI_SPI4_MOSI: R334.1 ; port WIFI_SPI4_MOSI
WIFI_SPI4_NSS: R337.1 ; port WIFI_SPI4_NSS
WIFI_SPI4_SCK: R343.1 ; port WIFI_SPI4_SCK
WIFI_UART_RX: SB48.1 ; port WIFI_UART_RX
WIFI_UART_TX: SB47.1 ; port WIFI_UART_TX
NetB4_1: R363.1 ; port JOYSTICK.JOY_LEFT
NetB4_2: R360.1 ; port JOYSTICK.JOY_SEL
NetB4_3: R367.1 ; port JOYSTICK.JOY_DOWN
NetB4_4: R389.1 ; port JOYSTICK.JOY_UP
NetB4_6: R386.1 ; port JOYSTICK.JOY_RIGHT

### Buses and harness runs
bus A[0..23] = port A[0..23]
bus D[0..31] = port D[0..31]
bus DCMI_D[0..7] = port DCMI_D[0..7]
bus LCD_B[0..7] = port LCD_B[0..7]
bus LCD_G[0..7] = port LCD_G[0..7]
bus LCD_R[0..7] = port LCD_R[0..7]
bus OCSPI1_IO[0..7] = port OCSPI1_IO[0..7]
bus PA[0..15] = port PA[0..15]
bus PB[0..15] = port PB[0..15]
bus PC[0..15] = port PC[0..15]
bus PD[0..15] = port PD[0..15]
bus PE[0..15] = port PE[0..15]
bus PF[0..15] = port PF[0..15]
bus PG[0..15] = port PG[0..15]
bus PH[0..15] = port PH[0..15]
bus PI[0..15] = port PI[0..15]
bus PJ[0..15] = port PJ[0..15]
bus PK[0..7] = port PK[0..7]
bus ULPI_D[0..7] = port ULPI_D[0..7]

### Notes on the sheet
- (near R258) STM32H7B3LIH6Q MCU I/Os
- PRIMARY FEATURES (fitted by default)
- (near R258) (for motor control)
- (LCD_BL_CTRL)
- (VCP for bootloader)
- (I2S6_MCK or ULPI D0)
- (DCMI_HSYNC or I2S6_WS)
- (I2S6_SCK)
- (jumper config : see below)
- (near R366) (OCSPI1_NCS or SD_LDO_SEL)
- (SAI1_MCLK_A)
- (near R322) (DCMI_PIXCLK or I2S6_EXT_SD)
- (near R364) (OCSPI1_IO6 or SDIO2_CK)
- (DCMI_D2, FMC_NE3 or SDIO2_D1)
- (near R132) (DCMI_VSYNC or SDIO2_D0)
- (DCMI_D3 or SDIO2_D2)
- (near R283) (I2S6_MISO or NJTRST)
- (I2S6_MOSI or ULPI_D7)
- (SAI1_SCK_A)
- (SAI1_FS_A)
- (SAI1_SD_A)
- (SAI1_SD_B)
- (near R295) (DFSDM1_2_DATIN1 or ULPI_D5)
- (VCP by default)
- (near R250) see page 4 : MCU CLOCK & RESET
- (near R62) (SDIO1_D0 or FMC_NE3)
- (near R286) (FMC_NE1 or DFSDM1_DATIN3)
- (near R286) (DCMI_D0 or FMC_NWAIT)
- see page 4 : MCU CLOCK & RESET
- (near R360) JOYSTICK (OPTIONAL) excl with LCD, SAI, SDRAM 32bits, Trace
- MOTOR (OPTIONAL)
- (near R213) excl with SAI, Camera, FMC, LCD, OCSPI1, MCO1, WIFI, USB HS
- (jumper config : exclusive use)
- (near JP19) DCMI, OCSPI1, SDIO1 & I2S6 (primary features)
- SDIO2, SAI, ULPI (USB HS), FMC NOR/SRAM, DFSDM (secondary features)
- (DFSDM1_CKOUT)
- (near R101) TRACE (OPTIONAL) excl with  CAMERA, SAI, FMC A19-23, WIFI SPI
- (DCMI_D1)
- CAN FD excl with USB FS
- excl with FMC, LCD, OCSPI1, SD card 2, USB FS
- MOTOR DFSDM (OPTIONAL)
- (DCMI_D2)
- (near SB35) USB HS exclusive with CAMERA & AUDIO I2S6
- (SAI)
- (near HW2) (SAI)
- (near R287) OCSPI2 (disable FMC, CAMERA & SD CARD 2)
- (SDNCAS)
- (FMC_A4)
- (FMC_A5)
- (near R95) (PB8 = MEMS_LED)
- (FMC_A0)
- (FMC_A1)
- (FMC_A2)
- (FMC_A3)
- (FMC_A10)
- AUDIO DFSDM & LCD RESET (OPTIONAL)
- (DCMI_D7)
- to avoid layout stub
- VCP & RS232 UART excl with WIFI UART
- PB14 or PA2
- PB15 or PA3
- (FMC_A11)
- (FMC_NE3/DCMI_D2)
- (SDIO2_D2/DCMI_D3)

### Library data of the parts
C30 C97 = MCD-00006: Capacitor, MLCC, 100nF, 16V, X7R, 10%, 0402, T=0.5mm; Manufacturer_Part_Number: CC0402KRX7R7BB104; Manufacturer: YAGEO; Alternate_Manufacturer_Part_Number: GCM155R71C104KA55D; Alternate_Manufacturer: MURATA; Provided_By: SUBCO; ECCN_US: EAR99; ECCN_EU: NEC
HW2 HW3 HW5 HW10 HW27 HW28 HW31 HW32 HW34-HW39 HW41 HW49 HW58 = MCD-00043: SHUNT 2.54mm BLACK; Part_Type: Mechanical; Manufacturer: SAMTEC; Alternate_Manufacturer_Part_Number: 316102S111A; Alternate_Manufacturer: JIUBABA; Value: SNT-100-BK-G; Provided_By: SUBCO
JP1 JP4 JP6-JP9 JP11 JP12 JP17 JP19 JP23 JP32 = MCD-00684: Header, 3x1, 2,54mm, VR, TH, Height 5.84mm/2.54mm - Shunt Fitted 1-2 by default; Part_Type: Connector; Manufacturer_Part_Number: TSW-103-07-F-S; Manufacturer: SAMTEC; Provided_By: SUBCO
JP2 = MCD-00111: Header, 3x1, 2,54mm, VR, TH, Height 5.84mm/2.54mm; Part_Type: Connector; Manufacturer_Part_Number: TSW-103-07-F-S; Manufacturer: SAMTEC; Provided_By: SUBCO; ECCN_US: EAR99; ECCN_EU: NEC
JP5 JP18 JP20 JP21 = MCD-00683: Header, 2x1, 2,54mm, VR, TH, Height 5.84mm/2.54mm - Shunt Fitted by default; Part_Type: Connector; Manufacturer_Part_Number: TSW-102-07-x-S; Manufacturer: SAMTEC; Alternate_Manufacturer_Part_Number: 313102S111116; Alternate_Manufacturer: LIANYI; Provided_By: SUBCO
JP10 JP14 JP16 JP26-JP28 JP34 JP39 JP40 = MCD-00045: Header, 2x1, 2,54mm, VR, TH, Height 5.84mm/2.54mm; Manufacturer_Part_Number: TSW-102-07-x-S; Manufacturer: SAMTEC; Part_Type: Connector; Alternate_Manufacturer_Part_Number: 313102S111116;313102S111116; Alternate_Manufacturer: JIUBABA; LIANYI; Value: Shunt not fitted; Provided_By: SUBCO
JP35 = MCD-00685: Header, 3x1, 2,54mm, VR, TH, Height 5.84mm/2.54mm - Shunt Fitted 2-3 by default; Part_Type: Connector; Manufacturer_Part_Number: TSW-103-07-F-S; Manufacturer: SAMTEC; Provided_By: SUBCO
R16 R23 R24 R29 R34 R48 R49 R51 R54 R56 R58 R61-R66 R68-R71 R73-R78 R80 R82 R87-R89 R93 R95-R98 R101-R105 R108 R110 R113-R119 R121 R122 R124 R127 R128 R131 R132 R216 R229 R230 R233 R234 R236 R237 R240 R241 R244 R245 R250 R255 R257 R258 R261 R271 R272 R280 R281 R283 R286 R287 R289 R292 R295-R297 R300 R308 R316 R318-R320 R322 R324-R326 R331-R335 R337-R345 R347-R354 R356-R371 R373-R375 R378 R380-R382 R384-R387 R389 R391 = MCD-00052: Resistor,0R,0402,5%,1/16W; Manufacturer_Part_Number: RC0402JR-070RL; Manufacturer: YAGEO; Provided_By: SUBCO; ECCN_US: EAR99; ECCN_EU: NEC
R35 R50 R55 R67 R72 R81 R120 R123 R209 R210 R213 R219 R235 R238 R239 R246 R253 R275 R277 R278 R282 R284 R288 R294 R301 R304 R309 R314 R323 R330 = MCD-00056: Resistor,0R,0603,5%,1/10W; Manufacturer_Part_Number: RC0603JR-070RL; Manufacturer: YAGEO; Provided_By: SUBCO; ECCN_US: EAR99; ECCN_EU: NEC
R43 R279 = MCD-00061: Resistor,1K,0402,1%,1/16W; Manufacturer_Part_Number: RC0402FR-071KL; Manufacturer: YAGEO; Provided_By: SUBCO; ECCN_US: EAR99; ECCN_EU: NEC
R60 = MCD-00053: Resistor,10K,0402,1%,1/16W; Manufacturer_Part_Number: RC0402FR-0710KL; Manufacturer: YAGEO; Provided_By: SUBCO; ECCN_US: EAR99; ECCN_EU: NEC
R214 R215 R226 R243 R248 R249 R254 R256 R259 R260 R264 R265 R269 R270 R276 R291 R293 R299 R302 R303 R306 R310 R312 R313 R315 R317 = MCD-01986: Ferrite bead, 470ohms at 100MHz, 200mA, 0.6ohms DC max; Manufacturer_Part_Number: BLM15BD471SN1D; Manufacturer: Murata; Value: 470ohms @ 100MHz; ECCN_US: EAR99; ECCN_EU: NEC; Provided_By: SUBCO
R290 R305 = MCD-01986: Ferrite bead, 470ohms at 100MHz, 200mA, 0.6ohms DC max; Manufacturer_Part_Number: BLM15BD471SN1D; Manufacturer: Murata; ECCN_US: EAR99; ECCN_EU: NEC; Provided_By: SUBCO
SB35 SB36 = MCD-00071: Solder Bridge ON; Part_Type: Mechanical; Manufacturer_Part_Number: RC0603JR-070RL; Manufacturer: YAGEO; Provided_By: SUBCO
SB47-SB50 = MCD-01618: Solder Bridge 0402 ON; Part_Type: Mechanical; Manufacturer_Part_Number: RC0402JR-070RL; Manufacturer: YAGEO; Provided_By: SUBCO
U5 = MCD-01930: STM32H7B3LIH6QU (crypto),TFBGA 225, 13x13 0.8 with footprint for socket IRONWOOD CS1222291MF; Part_Type: IC; Manufacturer: STMICROELECTRONICS; BMS_Part_Number: 9175362; ECCN_US: 5A992C; ECCN_EU: 5A002A4; Provided_By: SUBCO with ST control

## Sheet Audio_Codec.SchDoc: Audio Codec
size A4; Date: Not used; ApprovedBy: Not used; CheckedBy: Not used; Author: Not used; CompanyName: STMicroelectronics; DrawnBy: Not used; Engineer: Not used; Organization: Not used; Address1: Not used; Address2: Not used; Address3: Not used; Address4: Not used; DocumentNumber: Not used; Revision: Not used; SheetNumber: 10; SheetTotal: 23

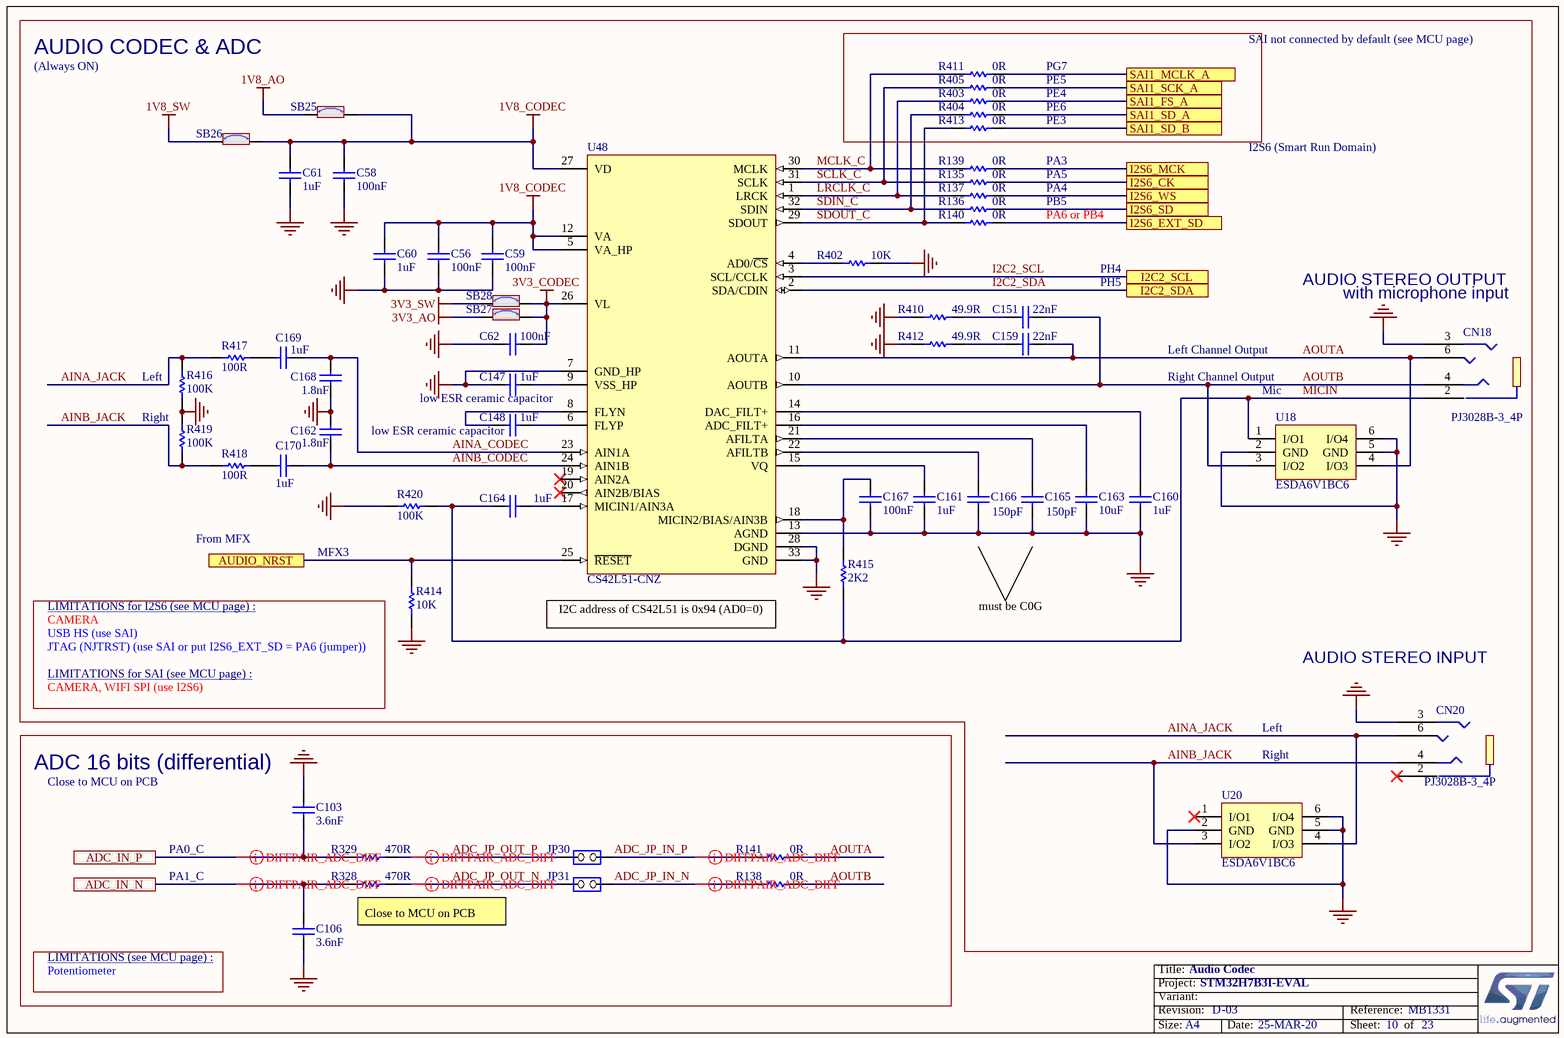
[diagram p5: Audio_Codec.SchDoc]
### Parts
C56  value 100nF  [C0402]  (hidden comment: Capacitor)
C58  value 100nF  [C0402]  (hidden comment: Capacitor)
C59  value 100nF  [C0402]  (hidden comment: Capacitor)
C60  value 1uF  [C0603]  (hidden comment: Capacitor)
C61  value 1uF  [C0603]  (hidden comment: Capacitor)
C62  value 100nF  [C0402]  (hidden comment: Capacitor)
C103  value 3.6nF  [C0603]  (hidden comment: Capacitor)
C106  value 3.6nF  [C0603]  (hidden comment: Capacitor)
C147  value 1uF  [C0603]  (hidden comment: Capacitor)
C148  value 1uF  [C0603]  (hidden comment: Capacitor)
C151  value 22nF  [C0603]  (hidden comment: Capacitor)
C159  value 22nF  [C0603]  (hidden comment: Capacitor)
C160  value 1uF  [C0603]  (hidden comment: Capacitor)
C161  value 1uF  [C0603]  (hidden comment: Capacitor)
C162  value 1.8nF  [C0402]  (hidden comment: Capacitor)
C163  value 10uF  [C0603]  (hidden comment: Capacitor)
C164  value 1uF  [C0603]  (hidden comment: Capacitor)
C165  value 150pF  [C0603]  (hidden comment: Capacitor)
C166  value 150pF  [C0603]  (hidden comment: Capacitor)
C167  value 100nF  [C0402]  (hidden comment: Capacitor)
C168  value 1.8nF  [C0402]  (hidden comment: Capacitor)
C169  value 1uF  [C0402]  (hidden comment: Capacitor)
C170  value 1uF  [C0402]  (hidden comment: Capacitor)
CN18  value PJ3028B-3_4P  [CON_PHONE-JACK-3P5_HY_PJ3028B]  (hidden comment: Jack_PJ3028B-3_4P)
CN20  value PJ3028B-3_4P  [CON_PHONE-JACK-3P5_HY_PJ3028B]  (hidden comment: Jack_PJ3028B-3_4P)
JP30  Jumper_Header 2x1  [CON_SAMTEC_TSW-102-07-G-S]  (value not drawn)
JP31  Jumper_Header 2x1  [CON_SAMTEC_TSW-102-07-G-S]  (value not drawn)
R135  value 0R  [R0402]  (hidden comment: Resistor)
R136  value 0R  [R0402]  (hidden comment: Resistor)
R137  value 0R  [R0402]  (hidden comment: Resistor)
R138  value 0R  [R0603]  (hidden comment: Resistor)
R139  value 0R  [R0402]  (hidden comment: Resistor)
R140  value 0R  [R0402]  (hidden comment: Resistor)
R141  value 0R  [R0603]  (hidden comment: Resistor)
R328  value 470R  [R0402]  (hidden comment: Resistor)
R329  value 470R  [R0402]  (hidden comment: Resistor)
R402  value 10K  [R0402]  (hidden comment: Resistor)
R403  value 0R  [R0402]  (hidden comment: Resistor)
R404  value 0R  [R0402]  (hidden comment: Resistor)
R405  value 0R  [R0402]  (hidden comment: Resistor)
R410  value 49.9R  [R0603]  (hidden comment: Resistor)
R411  value 0R  [R0402]  (hidden comment: Resistor)
R412  value 49.9R  [R0603]  (hidden comment: Resistor)
R413  value 0R  [R0402]  (hidden comment: Resistor)
R414  value 10K  [R0402]  (hidden comment: Resistor)
R415  value 2K2  [R0603]  (hidden comment: Resistor)
R416  value 100K  [R0402]  (hidden comment: Resistor)
R417  value 100R  [R0402]  (hidden comment: Resistor)
R418  value 100R  [R0402]  (hidden comment: Resistor)
R419  value 100K  [R0402]  (hidden comment: Resistor)
R420  value 100K  [R0603]  (hidden comment: Resistor)
SB25  SB_ON  [SOLDER-BRIDGE_R0603-0R]  (value not drawn)
SB26  SB_ON  [SOLDER-BRIDGE_R0603-0R]  (value not drawn)
SB27  SB_ON  [SOLDER-BRIDGE_R0603-0R]  (value not drawn)
SB28  SB_ON  [SOLDER-BRIDGE_R0603-0R]  (value not drawn)
U18  ESDA6V1BC6  [ESD_SOT23-6L]
U20  ESDA6V1BC6  [ESD_SOT23-6L]
U48  CS42L51-CNZ  [ICC_QFN32-EPAD_5X5_P050]

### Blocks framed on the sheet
AUDIO CODEC & ADC: C56 C58-C62 C147 C148 C151 C159-C170 CN18 CN20 R135-R137 R139 R140 R402-R405 R410-R420 SB25-SB28 U18 U20 U48
ADC 16 bits (differential): C103 C106 JP30 JP31 R138 R141 R328 R329

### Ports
ADC_IN_N, ADC_IN_P, AUDIO_NRST, I2C2_SCL, I2C2_SDA, I2S6_CK, I2S6_EXT_SD, I2S6_MCK, I2S6_SD, I2S6_WS, SAI1_FS_A, SAI1_MCLK_A, SAI1_SCK_A, SAI1_SD_A, SAI1_SD_B

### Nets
1V8_AO: SB25.1
1V8_CODEC: C56.2 C58.2 C59.2 C60.1 C61.1 SB25.2 SB26.2 U48.5(VA_HP) U48.12(VA) U48.27(VD)
1V8_SW: SB26.1
3V3_AO: SB27.1
3V3_CODEC: C62.1 SB27.2 SB28.2 U48.26(VL)
3V3_SW: SB28.1
GND: C56.1 C58.1 C59.1 C60.2 C61.2 C62.2 C103.2 C106.1 C147.1 C160.1 C161.1 C162.2 C163.1 C165.2 C166.2 C167.2 C168.1 CN18.3 CN20.3 R402.2 R410.1 R412.1 R414.1 R416.1 R419.2 R420.1 U18.2(GND) U18.5(GND) U18.6(I/O4) U20.2(GND) U20.5(GND) U20.6(I/O4) U48.7(GND_HP) U48.13(AGND) U48.28(DGND) U48.33(GND)
ADC_IN_N: C106.2 R328.1 ; port ADC_IN_N
ADC_IN_P: C103.1 R329.1 ; port ADC_IN_P
ADC_JP_IN_N: JP31.1(COMMON) R138.1
ADC_JP_IN_P: JP30.1(COMMON) R141.1
ADC_JP_OUT_N: JP31.2(NO) R328.2
ADC_JP_OUT_P: JP30.2(NO) R329.2
AINA_CODEC: C168.2 C169.2 U48.23(AIN1A)
AINA_JACK: CN20.6 R416.2 R417.1 U20.4(I/O3)
AINB_CODEC: C162.1 C170.2 U48.24(AIN1B)
AINB_JACK: CN20.4 R418.1 R419.1 U20.3(I/O2)
AOUTA: C159.2 CN18.6 R141.2 U18.4(I/O3) U48.11(AOUTA)
AOUTB: C151.2 CN18.4 R138.2 U18.3(I/O2) U48.10(AOUTB)
AUDIO_NRST: R414.2 U48.25(~{RESET}) ; port AUDIO_NRST
I2C2_SCL: U48.3(SCL/CCLK) ; port I2C2_SCL
I2C2_SDA: U48.2(SDA/CDIN) ; port I2C2_SDA
I2S6_CK: R135.2 ; port I2S6_CK
I2S6_EXT_SD: R140.2 ; port I2S6_EXT_SD
I2S6_MCK: R139.2 ; port I2S6_MCK
I2S6_SD: R136.2 ; port I2S6_SD
I2S6_WS: R137.2 ; port I2S6_WS
LRCLK_C: R137.1 R403.1 U48.1(LRCK)
MCLK_C: R139.1 R411.1 U48.30(MCLK)
MICIN: C164.1 CN18.2 R415.1 R420.2 U18.1(I/O1)
SAI1_FS_A: R403.2 ; port SAI1_FS_A
SAI1_MCLK_A: R411.2 ; port SAI1_MCLK_A
SAI1_SCK_A: R405.2 ; port SAI1_SCK_A
SAI1_SD_A: R404.2 ; port SAI1_SD_A
SAI1_SD_B: R413.2 ; port SAI1_SD_B
SCLK_C: R135.1 R405.1 U48.31(SCLK)
SDIN_C: R136.1 R404.1 U48.32(SDIN)
SDOUT_C: R140.1 R413.1 U48.29(SDOUT)
NetC147_2: C147.2 U48.9(VSS_HP)
NetC148_1: C148.1 U48.8(FLYN)
NetC148_2: C148.2 U48.6(FLYP)
NetC151_1: C151.1 R410.2
NetC159_1: C159.1 R412.2
NetC160_2: C160.2 U48.14(DAC_FILT+)
NetC161_2: C161.2 U48.15(VQ)
NetC163_2: C163.2 U48.16(ADC_FILT+)
NetC164_2: C164.2 U48.17(MICIN1/AIN3A)
NetC165_1: C165.1 U48.21(AFILTA)
NetC166_1: C166.1 U48.22(AFILTB)
NetC167_1: C167.1 R415.2 U48.18(MICIN2/BIAS/AIN3B)
NetC169_1: C169.1 R417.2
NetC170_1: C170.1 R418.2
NetR402_1: R402.1 U48.4(AD0/~{CS})

Not connected (* = marked no-connect by the designer): CN20 2*; U20 1(I/O1)*; U48 19(AIN2A)* 20(AIN2B/BIAS)*

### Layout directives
differential pair: ADC_IN_N, ADC_IN_P, ADC_JP_IN_N, ADC_JP_IN_P, ADC_JP_OUT_N, ADC_JP_OUT_P

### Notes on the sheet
- SAI not connected by default (see MCU page)
- (Always ON)
- PE6
- PE4
- PE5
- PG7
- PA5
- PA3
- PE3
- I2S6 (Smart Run Domain)
- PA4
- PA6 or PB4
- PB5
- PH4
- PH5
- AUDIO STEREO OUTPUT
- (near CN18) with microphone input
- (near R416) Left
- Left Channel Output
- Right Channel Output
- Right
- (near C148) low ESR ceramic capacitor
- low ESR ceramic capacitor
- (near U18) Mic
- From MFX
- MFX3
- LIMITATIONS for I2S6 (see MCU page) :
- CAMERA
- USB HS (use SAI)
- (near R414) JTAG (NJTRST) (use SAI or put I2S6_EXT_SD = PA6 (jumper))
- (near U48) I2C address of CS42L51 is 0x94 (AD0=0)
- must be C0G
- LIMITATIONS for SAI (see MCU page) :
- CAMERA, WIFI SPI (use I2S6)
- AUDIO STEREO INPUT
- Close to MCU on PCB
- Left
- PA0_C
- PA1_C
- (near R328) Close to MCU on PCB
- LIMITATIONS (see MCU page) :
- Potentiometer

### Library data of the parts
C56 C58 C59 C62 C167 = MCD-00006: as C30 on sheet MCU
C60 C61 C147 C148 C160 C161 C164 = MCD-00010: Capacitor, MLCC, 1uF, 16V, X5R, 10%, 0603, T=0,8mm; Manufacturer_Part_Number: CC0603KRX5R7BB105; Manufacturer: YAGEO; Provided_By: SUBCO; ECCN_US: EAR99; ECCN_EU: NEC
C103 C106 = MCD-00716: Capacitor, MLCC, 3.6nF, 50V, C0G, 5%, 0603, T=0,8mm; Manufacturer_Part_Number: C0603C362J5GACTU; Manufacturer: KEMET; Alternate_Manufacturer_Part_Number: GRM1885C1H362JA01D; Alternate_Manufacturer: MURATA; Provided_By: SUBCO; ECCN_US: EAR99; ECCN_EU: NEC
C151 C159 = MCD-00555: Capacitor, MLCC, 22nF, 10%, 25V, X7R, 0603, T=0,8mm; Manufacturer_Part_Number: CC0603KRX7R8BB223; Manufacturer: YAGEO; Provided_By: SUBCO; ECCN_US: EAR99; ECCN_EU: NEC
C162 C168 = MCD-00694: Capacitor, MLCC, 1.8nF, 50V, X7R, 10%, 0402, T=0.5mm; Manufacturer_Part_Number: CC0402KRX7R9BB182; Manufacturer: YAGEO; Provided_By: SUBCO
C163 = MCD-00099: Capacitor, MLCC, 10uF, 10V, X5R, 10%, 0603, T=0,8mm; Manufacturer_Part_Number: GRM188R61A106KE69D; Manufacturer: MURATA; Provided_By: SUBCO; ECCN_US: EAR99; ECCN_EU: NEC
C165 C166 = MCD-00304: Capacitor, MLCC, 150pF, 50V, COG, 5%, 0603, T=0,8mm; Manufacturer_Part_Number: CC0603JRNPO9BN151; Manufacturer: YAGEO; Provided_By: SUBCO; ECCN_US: EAR99; ECCN_EU: NEC
C169 C170 = MCD-00095: Capacitor, MLCC, 1uF, 6V3, X5R, 10%, 0402, T=0,5mm; Manufacturer_Part_Number: GRM155R61E105KA12; Manufacturer: MURATA; Alternate_Manufacturer_Part_Number: GRM155R60J105KE19; Provided_By: SUBCO; ECCN_US: EAR99; ECCN_EU: NEC
CN18 CN20 = MCD-00263: Connector Jack Socket Stereo 3.5mm, 4 pins, RA, SMT, Black; Manufacturer: QIAOD; Provided_By: SUBCO
JP30 JP31 = MCD-00045: Header, 2x1, 2,54mm, VR, TH, Height 5.84mm/2.54mm; Part_Type: Connector; Manufacturer_Part_Number: TSW-102-07-x-S; Manufacturer: SAMTEC; Alternate_Manufacturer_Part_Number: 313102S111116;313102S111116; Alternate_Manufacturer: JIUBABA; LIANYI; Value: Shunt not fitted; Provided_By: SUBCO
R135-R137 R139 R140 R403-R405 R411 R413 = MCD-00052: as R16 on sheet MCU
R138 R141 = MCD-00056: as R35 on sheet MCU
R328 R329 = MCD-00178: Resistor,470R,0402,1%,1/16W; Manufacturer_Part_Number: RC0402FR-07470RL; Manufacturer: YAGEO; Provided_By: SUBCO; ECCN_US: EAR99; ECCN_EU: NEC
R402 R414 = MCD-00053: as R60 on sheet MCU
R410 R412 = MCD-00564: Resistor,49R9,0603,1%,1/10W; Manufacturer_Part_Number: RC0603FR-0749R9L; Manufacturer: YAGEO; Provided_By: SUBCO; ECCN_US: EAR99; ECCN_EU: NEC
R415 = MCD-00349: Resistor,2K2,0603,1%,1/10W; Manufacturer_Part_Number: RC0603FR-072K2L; Manufacturer: YAGEO; Provided_By: SUBCO; ECCN_US: EAR99; ECCN_EU: NEC
R416 R419 = MCD-00059: Resistor,100K,0402,1%,1/16W; Manufacturer_Part_Number: RC0402FR-07100KL; Manufacturer: YAGEO; Alternate_Manufacturer_Part_Number: RT0402FRE07100KL; Provided_By: SUBCO; ECCN_US: EAR99; ECCN_EU: NEC
R417 R418 = MCD-00067: Resistor,100R,0402,1%,1/16W; Manufacturer_Part_Number: RC0402FR-07100RL; Manufacturer: YAGEO; Provided_By: SUBCO; ECCN_US: EAR99; ECCN_EU: NEC
R420 = MCD-00223: Resistor,100K,0603,1%,1/10W; Manufacturer_Part_Number: RC0603FR-07100KL; Manufacturer: YAGEO; Provided_By: SUBCO; ECCN_US: EAR99; ECCN_EU: NEC
SB25-SB28 = MCD-00071: as SB35 on sheet MCU
U18 U20 = MCD-00247: Quad Bidir ESD protection; Manufacturer: STMICROELECTRONICS; Part_Type: Diode; BMS_Part_Number: 9179038; Provided_By: SUBCO with ST control; ECCN_US: EAR99; ECCN_EU: NEC
U48 = MCD-00265: Low-Power, Stereo Codec with Headphone Amp; Manufacturer: CIRRUS LOGIC; Part_Type: IC; Provided_By: SUBCO; ECCN_US: EAR99; ECCN_EU: NEC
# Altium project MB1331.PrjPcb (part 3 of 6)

## Sheet DFSDM_Audio&Motor.SchDoc: Audio & Motor DFSDM
size A4; Date: Not used; ApprovedBy: Not used; CheckedBy: Not used; Author: Not used; CompanyName: STMicroelectronics; DrawnBy: Not used; Engineer: Not used; Organization: Not used; Address1: Not used; Address2: Not used; Address3: Not used; Address4: Not used; DocumentNumber: Not used; Revision: Not used; SheetNumber: 11; SheetTotal: 23

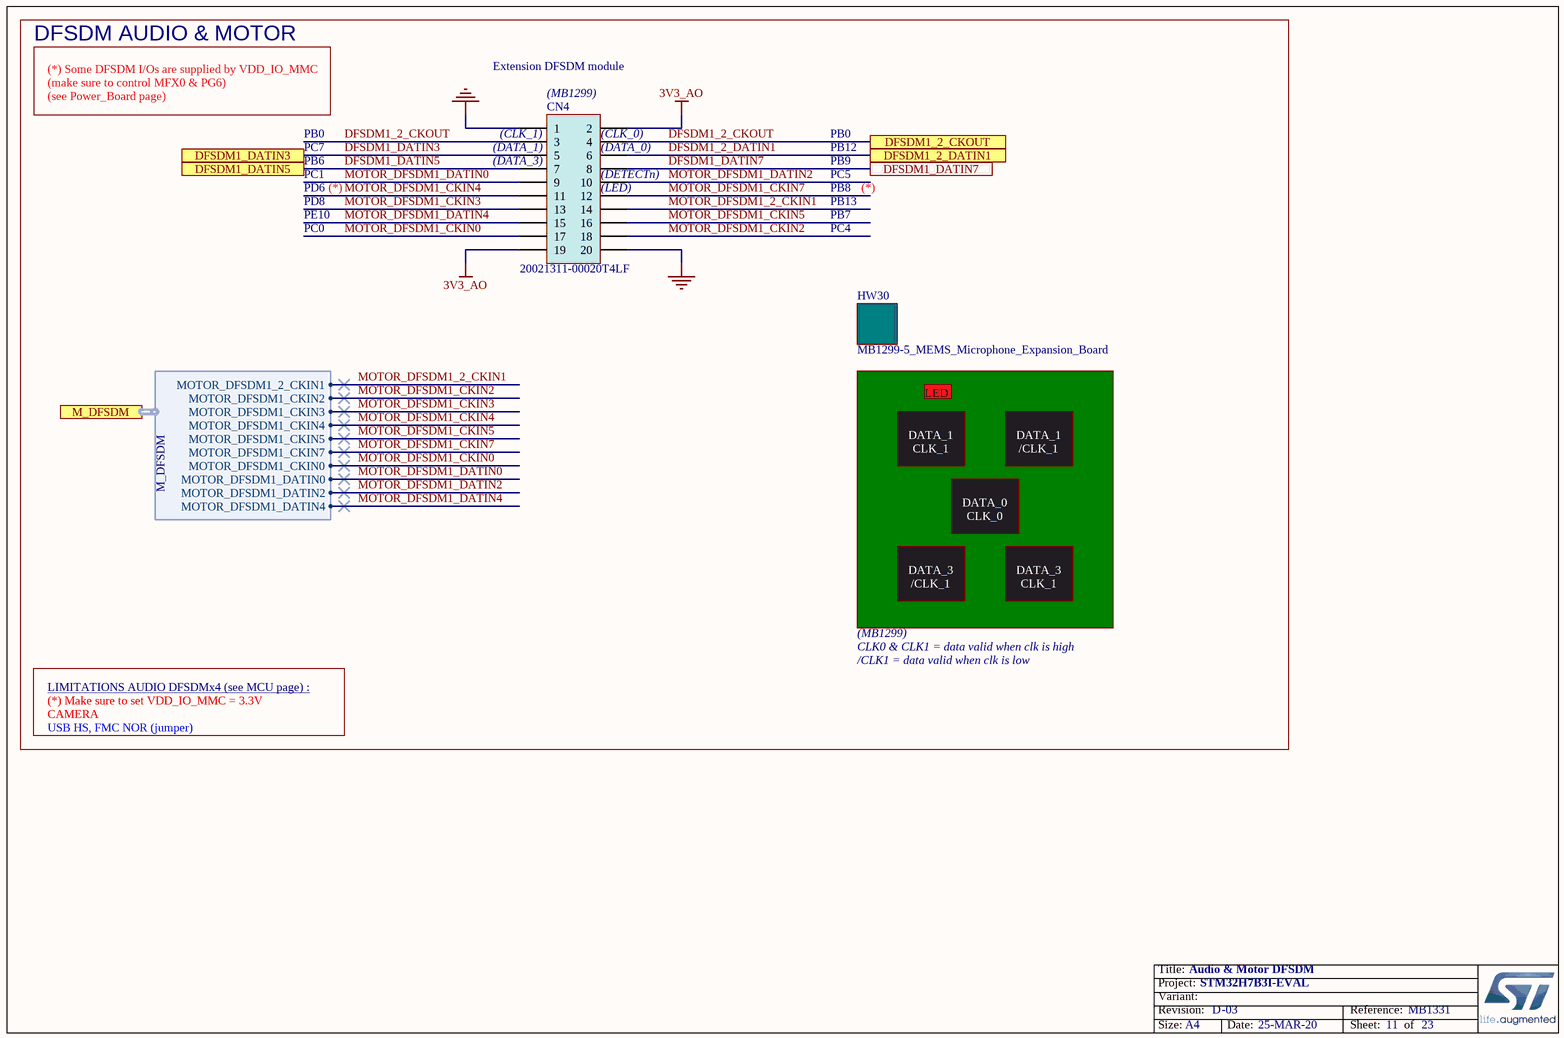
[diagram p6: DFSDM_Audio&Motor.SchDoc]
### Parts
CN4  value 20021311-00020T4LF  [CON_FCI_20021311-XXX20XXLF]  (hidden comment: Socket 10x2)
HW30  value MB1299-5_MEMS_Microphone_Expansion_Board  [MOD_MB1299_5-MEMS_MICROPHONE-EXPANSION-BOARD]  (hidden comment: Daughter_Board)

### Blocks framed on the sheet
DFSDM AUDIO & MOTOR: CN4 HW30

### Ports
DFSDM1_2_CKOUT, DFSDM1_2_DATIN1, DFSDM1_DATIN3, DFSDM1_DATIN5, DFSDM1_DATIN7, M_DFSDM (harness M_DFSDM)

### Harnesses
M_DFSDM: MOTOR_DFSDM1_2_CKIN1, MOTOR_DFSDM1_CKIN3, MOTOR_DFSDM1_CKIN5, MOTOR_DFSDM1_CKIN7, MOTOR_DFSDM1_CKIN2, MOTOR_DFSDM1_CKIN4, MOTOR_DFSDM1_CKIN0, MOTOR_DFSDM1_DATIN0, MOTOR_DFSDM1_DATIN2, MOTOR_DFSDM1_DATIN4

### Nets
3V3_AO: CN4.2 CN4.19
GND: CN4.1 CN4.20
DFSDM1_2_CKOUT: CN4.3 CN4.4 ; port DFSDM1_2_CKOUT
DFSDM1_2_DATIN1: CN4.6 ; port DFSDM1_2_DATIN1
DFSDM1_DATIN3: CN4.5 ; port DFSDM1_DATIN3
DFSDM1_DATIN5: CN4.7 ; port DFSDM1_DATIN5
DFSDM1_DATIN7: CN4.8 ; port DFSDM1_DATIN7
MOTOR_DFSDM1_2_CKIN1: CN4.14 ; port M_DFSDM.MOTOR_DFSDM1_2_CKIN1
MOTOR_DFSDM1_CKIN0: CN4.17 ; port M_DFSDM.MOTOR_DFSDM1_CKIN0
MOTOR_DFSDM1_CKIN2: CN4.18 ; port M_DFSDM.MOTOR_DFSDM1_CKIN2
MOTOR_DFSDM1_CKIN3: CN4.13 ; port M_DFSDM.MOTOR_DFSDM1_CKIN3
MOTOR_DFSDM1_CKIN4: CN4.11 ; port M_DFSDM.MOTOR_DFSDM1_CKIN4
MOTOR_DFSDM1_CKIN5: CN4.16 ; port M_DFSDM.MOTOR_DFSDM1_CKIN5
MOTOR_DFSDM1_CKIN7: CN4.12 ; port M_DFSDM.MOTOR_DFSDM1_CKIN7
MOTOR_DFSDM1_DATIN0: CN4.9 ; port M_DFSDM.MOTOR_DFSDM1_DATIN0
MOTOR_DFSDM1_DATIN2: CN4.10 ; port M_DFSDM.MOTOR_DFSDM1_DATIN2
MOTOR_DFSDM1_DATIN4: CN4.15 ; port M_DFSDM.MOTOR_DFSDM1_DATIN4

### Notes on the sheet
- (*) Some DFSDM I/Os are supplied by VDD_IO_MMC
  (make sure to control MFX0 & PG6)
  (see Power_Board page)
- Extension DFSDM module
- (near CN4) (MB1299)
- PB0
- PB6
- PC7
- PC1
- (near CN4) (DATA_1)
- (near CN4) (DATA_3)
- (near CN4) (CLK_1)
- (near CN4) (CLK_0)
- (near CN4) (DATA_0)
- (near CN4) (DETECTn)
- PB12
- PB9
- PC5
- PD8
- PC0
- PD6
- PE10
- (*)
- (near CN4) (LED)
- PB13
- PB8
- PB7
- PC4
- DATA_1
  CLK_1
- LED
- DATA_1
  /CLK_1
- DATA_0
  CLK_0
- DATA_3
  /CLK_1
- DATA_3
  CLK_1
- (MB1299)
- CLK0 & CLK1 = data valid when clk is high
- LIMITATIONS AUDIO DFSDMx4 (see MCU page) :
- CAMERA
- (*) Make sure to set VDD_IO_MMC = 3.3V
- /CLK1 = data valid when clk is low
- USB HS, FMC NOR (jumper)

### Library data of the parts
CN4 = MCD-00147: Socket for MB1299, 10x2, 1.27mm, VR, TH, Height 4.30mm/2.40mm; Manufacturer: FCI; Part_Type: Connector; Alternate_Manufacturer_Part_Number: 234220S1410; Alternate_Manufacturer: JIUBABA; Provided_By: SUBCO; ECCN_US: EAR99; ECCN_EU: NEC
HW30 = MCD-01031: MB1299 : Expansion Board with 5 x MEMS Microphones; Part_Type: Misc; Manufacturer_Part_Number: MB1299 - 5 x MEMS Microphones Expansion Board; Manufacturer: STMICROELECTRONICS; Provided_By: SUBCO with ST control

## Sheet LCD.SchDoc: LCD
size A4; Date: Not used; ApprovedBy: Not used; CheckedBy: Not used; Author: Not used; CompanyName: STMicroelectronics; DrawnBy: Not used; Engineer: Not used; Organization: Not used; Address1: Not used; Address2: Not used; Address3: Not used; Address4: Not used; DocumentNumber: Not used; Revision: Not used; SheetNumber: 13; SheetTotal: 23

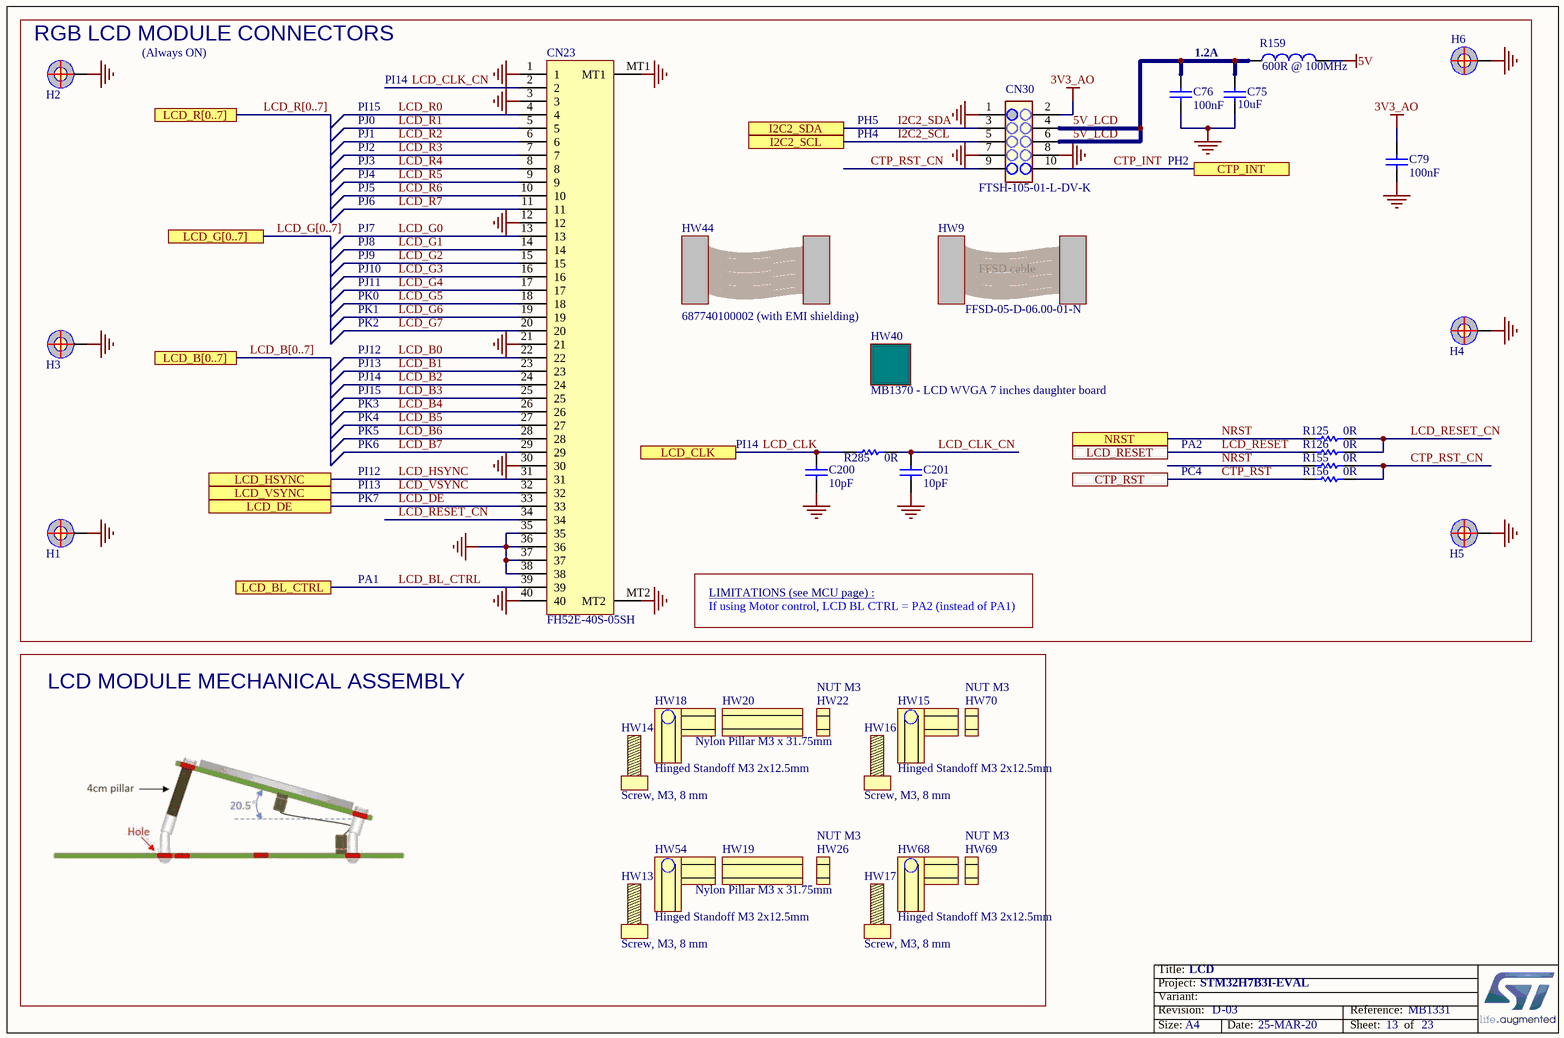
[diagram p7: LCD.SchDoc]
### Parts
C75  value 10uF  [C0805]  (hidden comment: Capacitor)
C76  value 100nF  [C0402]  (hidden comment: Capacitor)
C79  value 100nF  [C0402]  (hidden comment: Capacitor)
C200  value 10pF  [C0402]  (hidden comment: Capacitor)
C201  value 10pF  [C0402]  (hidden comment: Capacitor)
CN23  value FH52E-40S-05SH  [CON_HRS_FH52E-40S-05SH]  (hidden comment: FH52E-40S-0.5SH)
CN30  value FTSH-105-01-L-DV-K  [CON_SAMTEC_FTSH-105-01-L-DV-K]  (hidden comment: Header 5x2 Generic)
H1  POSITION HOLE  [PTH_M1261-3005-N_3P5X6_M3_H14]  (value not drawn)  (no BOM)
H2  POSITION HOLE  [PTH_M1261-3005-N_3P5X6_M3_H14]  (value not drawn)  (no BOM)
H3  POSITION HOLE  [PTH_M1261-3005-N_3P5X6_M3_H14]  (value not drawn)  (no BOM)
H4  POSITION HOLE  [PTH_M1261-3005-N_3P5X6_M3_H14]  (value not drawn)  (no BOM)
H5  POSITION HOLE  [PTH_M1261-3005-N_3P5X6_M3_H14]  (value not drawn)  (no BOM)
H6  POSITION HOLE  [PTH_M1261-3005-N_3P5X6_M3_H14]  (value not drawn)  (no BOM)
HW9  value FFSD-05-D-06.00-01-N  (hidden comment: FFSD05_CABLE)
HW13  value Screw, M3, 8 mm  (hidden comment: SCREW)  (mechanical)
HW14  value Screw, M3, 8 mm  (hidden comment: SCREW)  (mechanical)
HW15  value Hinged Standoff M3 2x12.5mm  (hidden comment: Hinged_Standoff)  (mechanical)
HW16  value Screw, M3, 8 mm  (hidden comment: SCREW)  (mechanical)
HW17  value Screw, M3, 8 mm  (hidden comment: SCREW)  (mechanical)
HW18  value Hinged Standoff M3 2x12.5mm  (hidden comment: Hinged_Standoff)  (mechanical)
HW19  value Nylon Pillar M3 x 31.75mm  (hidden comment: PILLAR)  (mechanical)
HW20  value Nylon Pillar M3 x 31.75mm  (hidden comment: PILLAR)  (mechanical)
HW22  value NUT M3  (hidden comment: NUT)  (mechanical)
HW26  value NUT M3  (hidden comment: NUT)  (mechanical)
HW40  value MB1370 - LCD WVGA 7 inches daughter board  [LCD_DRAWING_ROCKTEK_RK070ER9427L]  (hidden comment: Daughter_Board)
HW44  value 687740100002 (with EMI shielding)  (hidden comment: CABLE)  (mechanical)
HW54  value Hinged Standoff M3 2x12.5mm  (hidden comment: Hinged_Standoff)  (mechanical)
HW68  value Hinged Standoff M3 2x12.5mm  (hidden comment: Hinged_Standoff)  (mechanical)
HW69  value NUT M3  (hidden comment: NUT)  (mechanical)
HW70  value NUT M3  (hidden comment: NUT)  (mechanical)
R125  value 0R  [R0603]  (hidden comment: Resistor)
R126  value 0R  [R0603]  (hidden comment: Resistor)
R155  value 0R  [R0603]  (hidden comment: Resistor)
R156  value 0R  [R0603]  (hidden comment: Resistor)
R159  value 600R @ 100MHz  [IND_0603_H0P8]  (hidden comment: Inductor)
R285  value 0R  [R0603]  (hidden comment: Resistor)

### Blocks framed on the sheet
RGB LCD MODULE CONNECTORS: C75 C76 C79 C200 C201 CN23 CN30 H1-H6 HW9 HW40 HW44 R125 R126 R155 R156 R159 R285
LCD MODULE MECHANICAL ASSEMBLY: HW13-HW20 HW22 HW26 HW54 HW68-HW70

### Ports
CTP_INT, CTP_RST, I2C2_SCL, I2C2_SDA, LCD_B[0..7], LCD_BL_CTRL, LCD_CLK, LCD_DE, LCD_G[0..7], LCD_HSYNC, LCD_R[0..7], LCD_RESET, LCD_VSYNC, NRST

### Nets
3V3_AO: C79.2 CN30.2
5V: R159.2
GND: C75.1 C76.2 C79.1 C200.1 C201.1 CN23.1 CN23.3 CN23.12 CN23.21 CN23.30 CN23.35 CN23.36 CN23.37 CN23.38 CN23.40 CN23.MT1 CN23.MT2 CN30.1 CN30.7 CN30.8 H1.1 H2.1 H3.1 H4.1 H5.1 H6.1
5V_LCD: C75.2 C76.1 CN30.4 CN30.6 R159.1
CTP_INT: CN30.10 ; port CTP_INT
CTP_RST: R156.1 ; port CTP_RST
CTP_RST_CN: CN30.9 R155.2 R156.2
I2C2_SCL: CN30.5 ; port I2C2_SCL
I2C2_SDA: CN30.3 ; port I2C2_SDA
LCD_B0: CN23.22
LCD_B1: CN23.23
LCD_B2: CN23.24
LCD_B3: CN23.25
LCD_B4: CN23.26
LCD_B5: CN23.27
LCD_B6: CN23.28
LCD_B7: CN23.29
LCD_BL_CTRL: CN23.39 ; port LCD_BL_CTRL
LCD_CLK: C200.2 R285.1 ; port LCD_CLK
LCD_CLK_CN: C201.2 CN23.2 R285.2
LCD_DE: CN23.33 ; port LCD_DE
LCD_G0: CN23.13
LCD_G1: CN23.14
LCD_G2: CN23.15
LCD_G3: CN23.16
LCD_G4: CN23.17
LCD_G5: CN23.18
LCD_G6: CN23.19
LCD_G7: CN23.20
LCD_HSYNC: CN23.31 ; port LCD_HSYNC
LCD_R0: CN23.4
LCD_R1: CN23.5
LCD_R2: CN23.6
LCD_R3: CN23.7
LCD_R4: CN23.8
LCD_R5: CN23.9
LCD_R6: CN23.10
LCD_R7: CN23.11
LCD_RESET: R126.1 ; port LCD_RESET
LCD_RESET_CN: CN23.34 R125.2 R126.2
LCD_VSYNC: CN23.32 ; port LCD_VSYNC
NRST: R125.1 R155.1 ; port NRST

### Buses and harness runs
bus LCD_B[0..7] = port LCD_B[0..7]
bus LCD_G[0..7] = port LCD_G[0..7]
bus LCD_R[0..7] = port LCD_R[0..7]

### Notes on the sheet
- (Always ON)
- PI15
- PI14
- 1.2A
- PJ0
- PJ1
- PJ2
- PJ3
- PJ4
- PH5
- PH4
- PH2
- PJ5
- PJ6
- PJ7
- PJ8
- PJ9
- PJ10
- PJ11
- PK0
- PK1
- PK2
- PJ12
- PJ13
- PJ14
- PJ15
- PK3
- PK4
- PK5
- PK6
- PA2
- PI12
- PI13
- PK7
- PC4
- PA1
- LIMITATIONS (see MCU page) :
- If using Motor control, LCD BL CTRL = PA2 (instead of PA1)

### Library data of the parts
C75 = MCD-00014: Capacitor, MLCC, 10uF, 25V, X5R, 10%, 0805, T=0,85mm; Manufacturer_Part_Number: CC0805KRX5R8BB106; Manufacturer: YAGEO; Provided_By: SUBCO; ECCN_US: EAR99; ECCN_EU: NEC
C76 C79 = MCD-00006: Capacitor, MLCC, 100nF, 16V, X7R, 10%, 0402, T=0.5mm; Manufacturer_Part_Number: CC0402KRX7R7BB104; Manufacturer: YAGEO; Alternate_Manufacturer_Part_Number: GCM155R71C104KA55D; Alternate_Manufacturer: MURATA; Provided_By: SUBCO; ECCN_US: EAR99; ECCN_EU: NEC
C200 C201 = MCD-00015: Capacitor, MLCC, 10pF, 50V, NPO, 5%, 0402, T=0,5mm; Manufacturer_Part_Number: CC0402JRNPO9BN100; Manufacturer: YAGEO; ECCN_US: EAR99; ECCN_EU: NEC; Provided_By: SUBCO
CN23 = MCD-01992: FFC et FPC connector 0.5MM 40P LNG MTL FITNG SMT VERT MNT; Manufacturer: HIROSE; ECCN_US: EAR99; ECCN_EU: NEC; Provided_By: SUBCO
CN30 = MCD-00610: Surface mount, vertical male connector. Double row of 5 pins, 1.27mm pitch, 3.05mm lead. Mates with FFSD connector; Manufacturer: SAMTEC; Alternate_Manufacturer_Part_Number: P127B-2x05MGF-079-1A; Alternate_Manufacturer: JIUBABA; Provided_By: SUBCO
H1-H6 = MCD-00035: POSITION HOLE C6D3R5; Part_Type: Mechanical
HW9 = MCD-00612: FFSD series Ribbon cable pitch1.27mm 5pin x 2row, 15cm length.; Part_Type: Misc; Manufacturer: SAMTEC; ECCN_US: EAR99; ECCN_EU: NEC; Provided_By: SUBCO
HW13 HW14 HW16 HW17 = MCD-01711: Screw, M3, 8 mm, Stainless Steel; Part_Type: Mechanical; Manufacturer: ETTINGER; Provided_By: SUBCO
HW15 HW18 HW54 HW68 = MCD-01710: M3 2x12.5mm male to female Hinged Hex Standoff made of brass with nickel plated finish; Part_Type: Mechanical; Manufacturer: ETTINGER; Alternate_Manufacturer_Part_Number: 14.04.3.00034; Alternate_Manufacturer: JIUBABA; Provided_By: SUBCO
HW19 HW20 = MCD-01841: Nylon Pillar M3 x 31.75mm Male/Female; Part_Type: Mechanical; Manufacturer_Part_Number: 4820; Manufacturer: KEYSTONE ELECTRONICS; ECCN_US: EAR99; ECCN_EU: NEC; Provided_By: SUBCO
HW22 HW26 HW69 HW70 = MCD-01354: Nut, Steel, M3; Part_Type: Mechanical; Manufacturer_Part_Number: 4708; Manufacturer: Keystone Electronics
HW40 = MCD-01035: MB1370 - LCD WVGA 7 inches daughter board; Part_Type: Misc; Manufacturer: STMICROELECTRONICS; Provided_By: SUBCO with ST control
HW44 = MCD-02049: FFC/FPC Flex Cable, Opposite Side Contacts, WR-FFC 0.5mm Type 2 40P 100mm length, customized with EMI shielding; Part_Type: Mechanical; Manufacturer: WURTH ELEKTRONIK; Order_Code_RS: 1222740; ECCN_US: EAR99; ECCN_EU: NEC; Provided_By: SUBCO
R125 R126 R155 R156 R285 = MCD-00056: Resistor,0R,0603,5%,1/10W; Manufacturer_Part_Number: RC0603JR-070RL; Manufacturer: YAGEO; Provided_By: SUBCO; ECCN_US: EAR99; ECCN_EU: NEC
R159 = MCD-00593: Ferrite bead, 600R @ 100MHz,  1.3A, 150mOhm, 0603; Manufacturer_Part_Number: BLM18KG601SN1D; Manufacturer: MURATA; ECCN_US: EAR99; ECCN_EU: NEC; Provided_By: SUBCO

## Sheet JTAG&Trace.SchDoc: JTAG & Trace
size A4; Date: Not used; ApprovedBy: Not used; CheckedBy: Not used; Author: Not used; CompanyName: STMicroelectronics; DrawnBy: Not used; Engineer: Not used; Organization: Not used; Address1: Not used; Address2: Not used; Address3: Not used; Address4: Not used; DocumentNumber: Not used; Revision: Not used; SheetNumber: 22; SheetTotal: 23

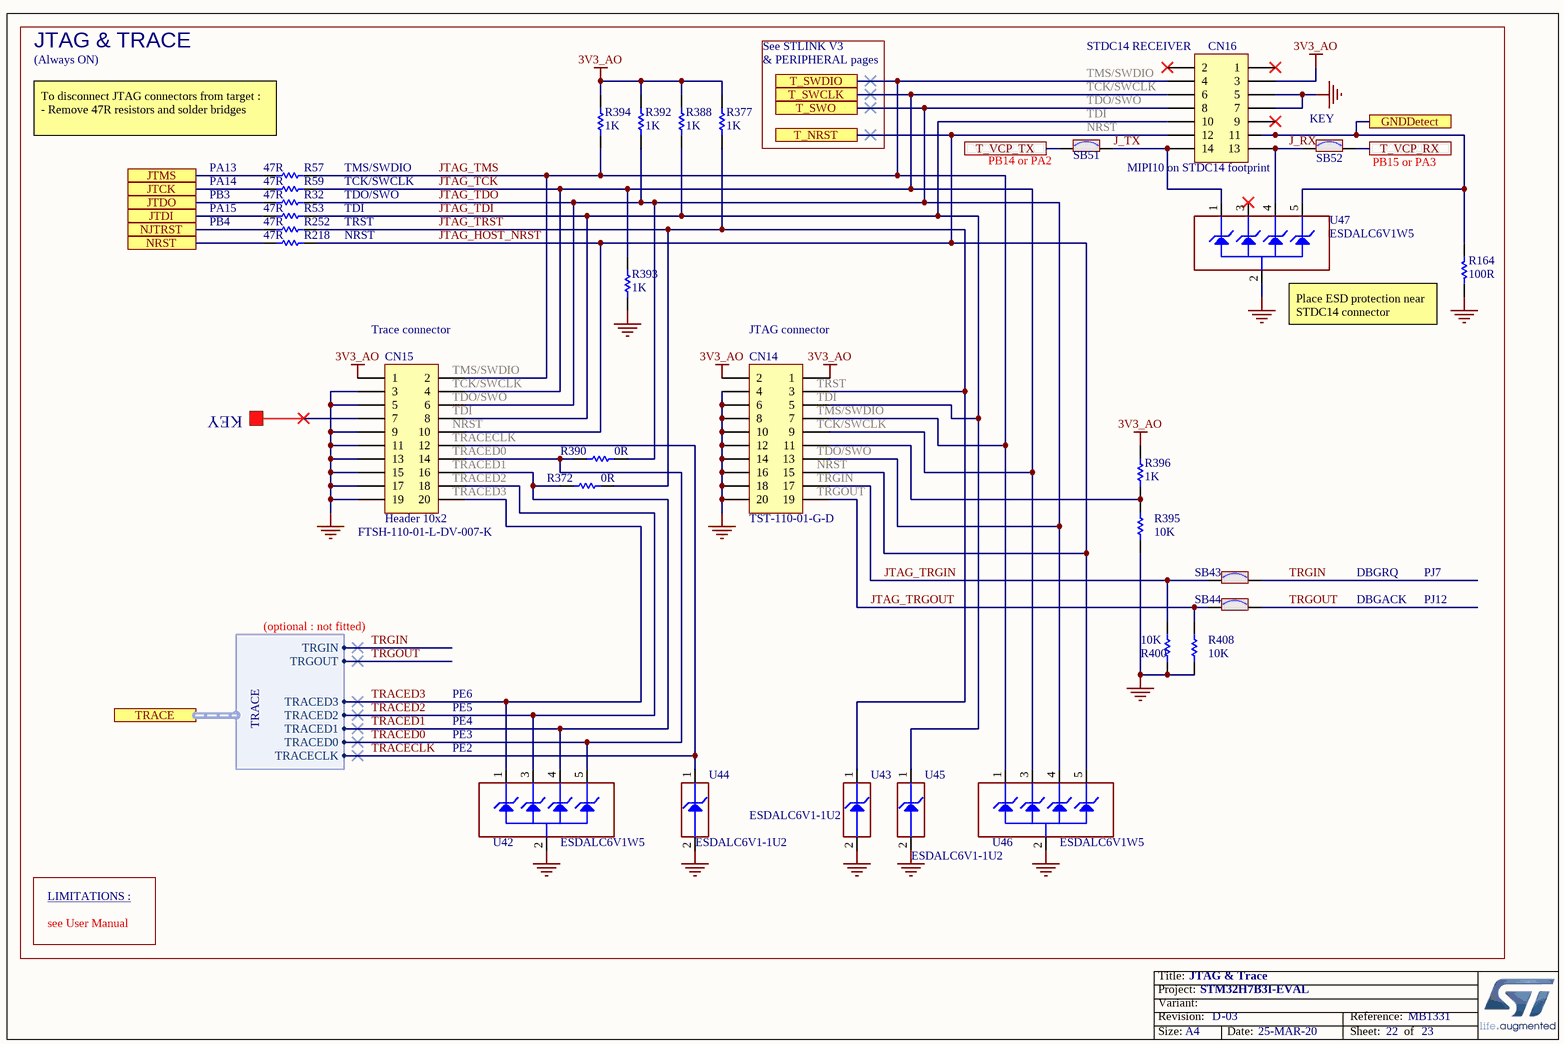
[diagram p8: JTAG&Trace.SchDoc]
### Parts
CN14  value TST-110-01-G-D  [CON_CVILUX_CH87-20-2-V-1-00]  (hidden comment: Header 10x2)
CN15  Header 10x2  [CON_SAMTEC_FTSH-110-01-L-DV]
CN16  value MIPI10 on STDC14 footprint  [CON_STDC14_Receiver_MEDIUM_WITH_MIPI10_3D]  (hidden comment: Header 7x2)
R32  value 47R  [R0603]  (hidden comment: Resistor)
R53  value 47R  [R0603]  (hidden comment: Resistor)
R57  value 47R  [R0603]  (hidden comment: Resistor)
R59  value 47R  [R0603]  (hidden comment: Resistor)
R164  value 100R  [R0402]  (hidden comment: Resistor)
R218  value 47R  [R0603]  (hidden comment: Resistor)
R252  value 47R  [R0603]  (hidden comment: Resistor)
R372  value 0R  [R0402]  (hidden comment: Resistor)
R377  value 1K  [R0402]  (hidden comment: Resistor)
R388  value 1K  [R0402]  (hidden comment: Resistor)
R390  value 0R  [R0402]  (hidden comment: Resistor)
R392  value 1K  [R0402]  (hidden comment: Resistor)
R393  value 1K  [R0402]  (hidden comment: Resistor)
R394  value 1K  [R0402]  (hidden comment: Resistor)
R395  value 10K  [R0402]  (hidden comment: Resistor)
R396  value 1K  [R0402]  (hidden comment: Resistor)
R400  value 10K  [R0402]  (hidden comment: Resistor)
R408  value 10K  [R0402]  (hidden comment: Resistor)
SB43  SB_ON  [SOLDER-BRIDGE_R0603-0R]  (value not drawn)
SB44  SB_ON  [SOLDER-BRIDGE_R0603-0R]  (value not drawn)
SB51  SB_ON  [SOLDER-BRIDGE_R0402-0R]  (value not drawn)
SB52  SB_ON  [SOLDER-BRIDGE_R0402-0R]  (value not drawn)
U42  ESDALC6V1W5  [ESD_SOT323-5L]
U43  value ESDALC6V1-1U2  [ESD_ST0201]  (hidden comment: ESD-TRANSIL)
U44  value ESDALC6V1-1U2  [ESD_ST0201]  (hidden comment: ESD-TRANSIL)
U45  value ESDALC6V1-1U2  [ESD_ST0201]  (hidden comment: ESD-TRANSIL)
U46  ESDALC6V1W5  [ESD_SOT323-5L]
U47  ESDALC6V1W5  [ESD_SOT323-5L]

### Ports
GNDDetect, JTCK, JTDI, JTDO, JTMS, NJTRST, NRST, T_NRST, T_SWCLK, T_SWDIO, T_SWO, T_VCP_RX, T_VCP_TX, TRACE (harness TRACE)

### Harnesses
TRACE: TRACECLK, TRACED0, TRACED1, TRACED2, TRACED3, TRGIN, TRGOUT

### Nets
3V3_AO: CN14.1 CN14.2 CN15.1 CN16.3 R377.2 R388.2 R392.2 R394.2 R396.2
GND: CN14.4 CN14.6 CN14.8 CN14.10 CN14.12 CN14.14 CN14.16 CN14.18 CN14.20 CN15.3 CN15.5 CN15.9 CN15.11 CN15.13 CN15.15 CN15.17 CN15.19 CN16.5 CN16.7 R164.1 R393.1 R395.1 R400.1 R408.1 U42.2(GND) U43.2(GND) U44.2(GND) U45.2(GND) U46.2(GND) U47.2(GND)
GNDDetect: CN16.11 R164.2 U47.5(IO4) ; port GNDDetect
J_RX: CN16.13 SB52.1 U47.4(IO3)
J_TX: CN16.14 SB51.2 U47.1(IO1)
JTAG_HOST_NRST: CN14.15 CN15.10 CN16.12 R218.1 U46.5(IO4) ; port T_NRST
JTAG_TCK: CN14.9 CN15.4 CN16.6 R59.1 R393.2 U46.3(IO2) ; port T_SWCLK
JTAG_TDI: CN14.5 CN15.8 CN16.10 R53.1 R388.1 U45.1(IO1)
JTAG_TDO: CN14.13 CN15.6 CN16.8 R32.1 R390.2 R392.1 U46.4(IO3) ; port T_SWO
JTAG_TMS: CN14.7 CN15.2 CN16.4 R57.1 R394.1 U46.1(IO1) ; port T_SWDIO
JTAG_TRGIN: CN14.17 R400.2 SB43.1
JTAG_TRGOUT: CN14.19 R408.2 SB44.1
JTAG_TRST: CN14.3 R252.1 R372.2 R377.1 U43.1(IO1)
NJTRST: R252.2 ; port NJTRST
NRST: R218.2 ; port NRST
PA13: R57.2 ; port JTMS
PA14: R59.2 ; port JTCK
PA15: R53.2 ; port JTDI
PB3: R32.2 ; port JTDO
T_VCP_RX: SB52.2 ; port T_VCP_RX
T_VCP_TX: SB51.1 ; port T_VCP_TX
TRACECLK: CN15.12 U44.1(IO1) ; port TRACE.TRACECLK
TRACED0: CN15.14 R390.1 U42.5(IO4) ; port TRACE.TRACED0
TRACED1: CN15.16 R372.1 U42.4(IO3) ; port TRACE.TRACED1
TRACED2: CN15.18 U42.3(IO2) ; port TRACE.TRACED2
TRACED3: CN15.20 U42.1(IO1) ; port TRACE.TRACED3
TRGIN: SB43.2 ; port TRACE.TRGIN
TRGOUT: SB44.2 ; port TRACE.TRGOUT
NetCN14_11: CN14.11 R395.2 R396.1

Not connected (* = marked no-connect by the designer): CN15 7*; CN16 1* 2* 9*; U47 3(IO2)*

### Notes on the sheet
- JTAG & TRACE
- See STLINK V3
- (near CN16) STDC14 RECEIVER
- (Always ON)
- & PERIPHERAL pages
- TMS/SWDIO
- TCK/SWCLK
- (near SB51) TDO/SWO
- (near SB51) TDI
- (near SB52) KEY
- To disconnect JTAG connectors from target :
  - Remove 47R resistors and solder bridges
- PA13
- PA14
- (near SB51) PB14 or PA2
- (near SB51) NRST
- (near SB52) PB15 or PA3
- PB3
- PA15
- PB4
- TDO/SWO
- TDI
- TRST
- NRST
- (near U47) Place ESD protection near STDC14 connector
- (near CN15) Trace connector
- (near CN15) TMS/SWDIO
- (near CN15) TCK/SWCLK
- (near CN14) JTAG connector
- (near CN14) TRST
- KEY
- (near CN15) TDO/SWO
- (near CN15) TDI
- (near CN15) NRST
- (near CN15) TRACECLK
- (near CN15) TRACED0
- (near CN14) TDI
- (near CN14) TMS/SWDIO
- (near CN14) TCK/SWCLK
- (near CN14) TDO/SWO
- (near CN15) TRACED1
- (near CN15) TRACED2
- (near CN15) TRACED3
- (near CN14) NRST
- (near CN14) TRGIN
- (near CN14) TRGOUT
- (near CN15) FTSH-110-01-L-DV-007-K
- DBGRQ
- PJ7
- (optional : not fitted)
- DBGACK
- PJ12
- PE6
- PE5
- PE4
- PE3
- (near U42) PE2
- LIMITATIONS :
- see User Manual

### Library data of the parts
CN14 = MCD-01058: Header, 2.54mm, 10x2, VR, TH, Height 9.1mm/3,1mm; Part_Type: Connector; Manufacturer: SAMTEC; Alternate_Manufacturer_Part_Number: CH87-20-2-V-1-00; Alternate_Manufacturer: CVILUX; Provided_By: SUBCO
CN15 = MCD-00557: Header 10x2, 1.27mm, VR, CMS, Height 3.05mm; Part_Type: Connector; Manufacturer_Part_Number: FTSH-110-01-L-DV-007-K; Manufacturer: SAMTEC; Alternate_Manufacturer_Part_Number: P127B-2*10MGF-079-1E7A; Alternate_Manufacturer: JIUBABA; Provided_By: SUBCO
CN16 = MCD-01226: Header 5x2, 1.27mm, Dual row, Straight, Surface mount, vertical male connector. 3.05mm lead. Mates with FFSD connector. Footprint compatible with FTSH-107-01-L-DV,-K,-A,-P,-ES (STDC14 MEDIUM); Manufacturer_Part_Number: FTSH-105-01-L-DV-K; Manufacturer: SAMTEC; Alternate_Manufacturer_Part_Number: P127B-2x05MGF-079-1A; Alternate_Manufacturer: JIUBABA; Provided_By: SUBCO
R32 R53 R57 R59 R218 R252 = MCD-00482: Resistor,47R,0603,1%,1/10W; Manufacturer_Part_Number: RC0603FR-0747RL; Manufacturer: YAGEO; Provided_By: SUBCO; ECCN_US: EAR99; ECCN_EU: NEC
R164 = MCD-00067: Resistor,100R,0402,1%,1/16W; Manufacturer_Part_Number: RC0402FR-07100RL; Manufacturer: YAGEO; Provided_By: SUBCO; ECCN_US: EAR99; ECCN_EU: NEC
R372 R390 = MCD-00052: Resistor,0R,0402,5%,1/16W; Manufacturer_Part_Number: RC0402JR-070RL; Manufacturer: YAGEO; Provided_By: SUBCO; ECCN_US: EAR99; ECCN_EU: NEC
R377 R388 R392-R394 R396 = MCD-00061: Resistor,1K,0402,1%,1/16W; Manufacturer_Part_Number: RC0402FR-071KL; Manufacturer: YAGEO; Provided_By: SUBCO; ECCN_US: EAR99; ECCN_EU: NEC
R395 R400 R408 = MCD-00053: Resistor,10K,0402,1%,1/16W; Manufacturer_Part_Number: RC0402FR-0710KL; Manufacturer: YAGEO; Provided_By: SUBCO; ECCN_US: EAR99; ECCN_EU: NEC
SB43 SB44 = MCD-00071: Solder Bridge ON; Part_Type: Mechanical; Manufacturer_Part_Number: RC0603JR-070RL; Manufacturer: YAGEO; Provided_By: SUBCO
SB51 SB52 = MCD-01618: Solder Bridge 0402 ON; Part_Type: Mechanical; Manufacturer_Part_Number: RC0402JR-070RL; Manufacturer: YAGEO; Provided_By: SUBCO
U42 U46 = MCD-00136: Dual Transil array for ESD protection; Manufacturer: STMICROELECTRONICS; Part_Type: Diode; BMS_Part_Number: 9151112; Provided_By: SUBCO with ST control; ECCN_US: EAR99; ECCN_EU: NEC
U43-U45 = MCD-00170: ESD protection 6V1; Part_Type: Diode; Manufacturer: STMICROELECTRONICS; BMS_Part_Number: 9151132; Provided_By: SUBCO with ST control; ECCN_US: EAR99; ECCN_EU: NEC
U47 = MCD-00136: Dual Transil array for ESD protection; Part_Type: Diode; Manufacturer: STMICROELECTRONICS; BMS_Part_Number: 9151112; Provided_By: SUBCO with ST control; ECCN_US: EAR99; ECCN_EU: NEC

## Sheet MCU_Clock&Reset.SchDoc: MCU Clocks and Reset
size A4; Date: Not used; ApprovedBy: Not used; CheckedBy: Not used; Author: Not used; CompanyName: STMicroelectronics; DrawnBy: Not used; Engineer: Not used; Organization: Not used; Address1: Not used; Address2: Not used; Address3: Not used; Address4: Not used; DocumentNumber: Not used; Revision: Not used; SheetNumber: 4; SheetTotal: 23

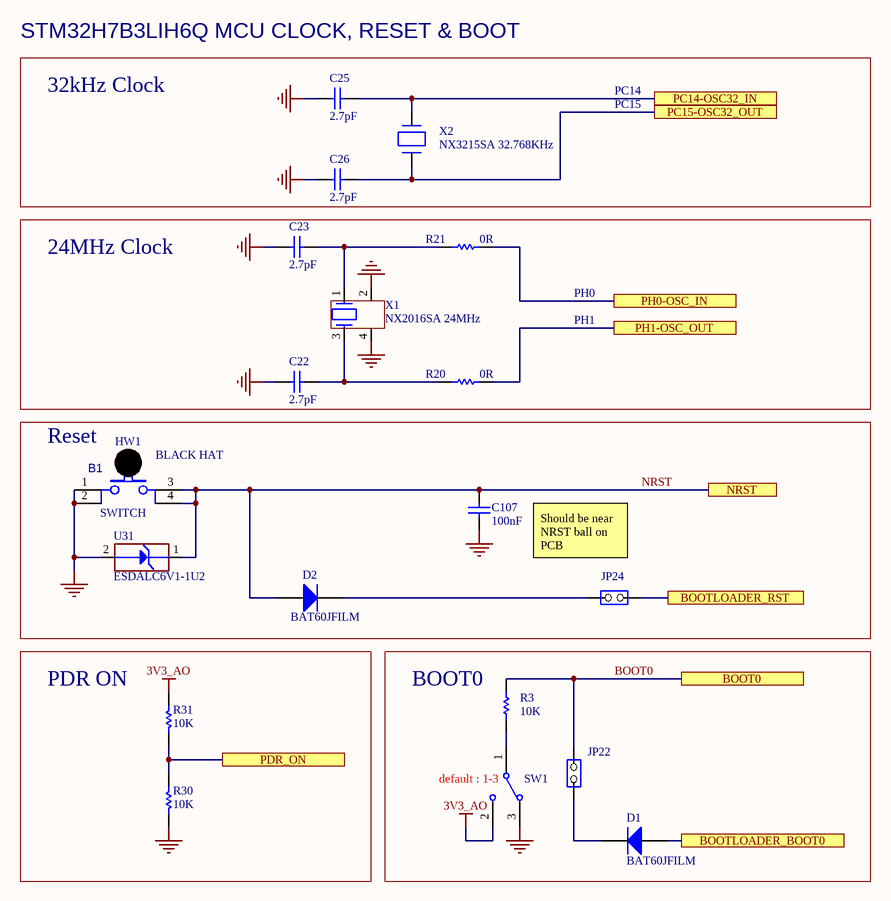
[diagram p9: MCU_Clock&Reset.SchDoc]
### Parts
B1  value SWITCH  [SWI_WEALTHMETAL_TD-0341_4P_BLACK]  (hidden comment: SW-PUSH-CMS)
C22  value 2.7pF  [C0603]  (hidden comment: Capacitor)
C23  value 2.7pF  [C0603]  (hidden comment: Capacitor)
C25  value 2.7pF  [C0603]  (hidden comment: Capacitor)
C26  value 2.7pF  [C0603]  (hidden comment: Capacitor)
C107  value 100nF  [C0402]  (hidden comment: Capacitor)
D1  BAT60JFILM  [DIO_SOD323]
D2  BAT60JFILM  [DIO_SOD323]
HW1  value BLACK HAT  (hidden comment: BUTTON_HAT_BLACK)  (mechanical)
JP22  Jumper_Header 2x1  [CON_SAMTEC_TSW-102-07-G-S]  (value not drawn)
JP24  Jumper_Header 2x1  [CON_SAMTEC_TSW-102-07-G-S]  (value not drawn)
R3  value 10K  [R0402]  (hidden comment: Resistor)
R20  value 0R  [R0402]  (hidden comment: Resistor)
R21  value 0R  [R0402]  (hidden comment: Resistor)
R30  value 10K  [R0402]  (hidden comment: Resistor)
R31  value 10K  [R0402]  (hidden comment: Resistor)
SW1  SW_MECA_1K2  [SWI_EAO_09-03290-01_EXTENDED_STRAIGHT_BLACK]  (value not drawn)
U31  value ESDALC6V1-1U2  [ESD_ST0201]  (hidden comment: ESD-TRANSIL)
X1  value NX2016SA 24MHz  [CRY_NX2016SA_4P]  (hidden comment: XTAL_4_PINS)
X2  value NX3215SA 32.768KHz  [CRY_NX3215SA_2P]  (hidden comment: XTAL_2_PINS)

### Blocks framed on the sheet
24MHz Clock: C22 C23 R20 R21 X1
Reset: B1 C107 D2 HW1 JP24 U31
PDR ON: R30 R31
BOOT0: D1 JP22 R3 SW1

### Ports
BOOT0, BOOTLOADER_BOOT0, BOOTLOADER_RST, NRST, PC14-OSC32_IN, PC15-OSC32_OUT, PDR_ON, PH0-OSC_IN, PH1-OSC_OUT

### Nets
3V3_AO: R31.1 SW1.2
GND: B1.1 B1.2 C22.1 C23.1 C25.1 C26.1 C107.1 R30.2 SW1.3 U31.2(GND) X1.2 X1.4
BOOT0: JP22.2(NO) R3.1 ; port BOOT0
BOOTLOADER_BOOT0: D1.1(A) ; port BOOTLOADER_BOOT0
BOOTLOADER_RST: JP24.2(NO) ; port BOOTLOADER_RST
NRST: B1.3 B1.4 C107.2 D2.1(A) U31.1(IO1) ; port NRST
PC14-OSC32_IN: C25.2 X2.2(X2) ; port PC14-OSC32_IN
PC15-OSC32_OUT: C26.2 X2.1(X1) ; port PC15-OSC32_OUT
PDR_ON: R30.1 R31.2 ; port PDR_ON
PH0: R21.2 ; port PH0-OSC_IN
PH1: R20.2 ; port PH1-OSC_OUT
NetC22_2: C22.2 R20.1 X1.3
NetC23_2: C23.2 R21.1 X1.1
NetD1_2: D1.2(K) JP22.1(COMMON)
NetD2_2: D2.2(K) JP24.1(COMMON)
NetR3_2: R3.2 SW1.1

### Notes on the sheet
- STM32H7B3LIH6Q MCU CLOCK, RESET & BOOT
- 32kHz Clock
- PC14
- PC15
- PH0
- PH1
- Should be near NRST ball on PCB
- (near SW1) default : 1-3

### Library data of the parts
B1 = MCD-00001: Non-Open Push-Button 0.1A 24V BLACK; Manufacturer_Part_Number: TD-0341; Manufacturer: WEALTHMETAL; Part_Type: Misc; Provided_By: SUBCO
C22 C23 C25 C26 = MCD-01726: Capacitor, MLCC, 2.7pF, 50V, NPO, -+0.25pF 0603; Manufacturer_Part_Number: CC0603CRNPO9BN2R7; Manufacturer: YAGEO; Provided_By: SUBCO
C107 = MCD-00006: as C76 on sheet LCD
D1 D2 = MCD-00034: Manufacturer: STMICROELECTRONICS; Part_Type: Diode; BMS_Part_Number: 9151097; Provided_By: SUBCO with ST control; ECCN_US: EAR99; ECCN_EU: NEC
HW1 = MCD-00635: Black Hat for switch TD0341X-G01-BLA; Part_Type: Mechanical; Manufacturer_Part_Number: 988.16.09.3.00003_SH-517; Manufacturer: JIUBABA; Provided_By: SUBCO
JP22 JP24 = MCD-00045: Header, 2x1, 2,54mm, VR, TH, Height 5.84mm/2.54mm; Manufacturer_Part_Number: TSW-102-07-x-S; Manufacturer: SAMTEC; Part_Type: Connector; Alternate_Manufacturer_Part_Number: 313102S111116;313102S111116; Alternate_Manufacturer: JIUBABA; LIANYI; Value: Shunt not fitted; Provided_By: SUBCO
R3 R30 R31 = MCD-00053: as R395 on sheet JTAG&Trace
R20 R21 = MCD-00052: as R372 on sheet JTAG&Trace
SW1 = MCD-00566: Mechanical Slide Switches 1K2 BLK ACT GOLD STRT MNT; Part_Type: Misc; Manufacturer_Part_Number: 09.03290.01; Manufacturer: EAO; Value: Mechanical Slide Switch 1K2; Provided_By: SUBCO
U31 = MCD-00170: as U43 on sheet JTAG&Trace
X1 = MCD-01036: Crystal 24MHz, 6pF, +-20ppm, 80ohms max, SMD; Part_Type: Crystal_Osc; Manufacturer_Part_Number: NX2016SA 24MHz EXS00A-CS10820; Manufacturer: NDK; BMS_Part_Number: 9157045; Provided_By: SUBCO; ECCN_US: EAR99; ECCN_EU: NEC
X2 = MCD-00091: Crystal 32.768kHz, 6pF, +-20ppm, 50Kohms max, SMD; Part_Type: Crystal_Osc; Manufacturer_Part_Number: NX3215SA 32.768KHz EXS00A-MU00525; Manufacturer: NDK; BMS_Part_Number: 9157034; Provided_By: SUBCO; ECCN_US: EAR99; ECCN_EU: NEC

## Sheet Memory.SchDoc: Memory
size A4; Date: Not used; ApprovedBy: Not used; CheckedBy: Not used; Author: Not used; CompanyName: STMicroelectronics; DrawnBy: Not used; Engineer: Not used; Organization: Not used; Address1: Not used; Address2: Not used; Address3: Not used; Address4: Not used; DocumentNumber: Not used; Revision: Not used; SheetNumber: 7; SheetTotal: 23

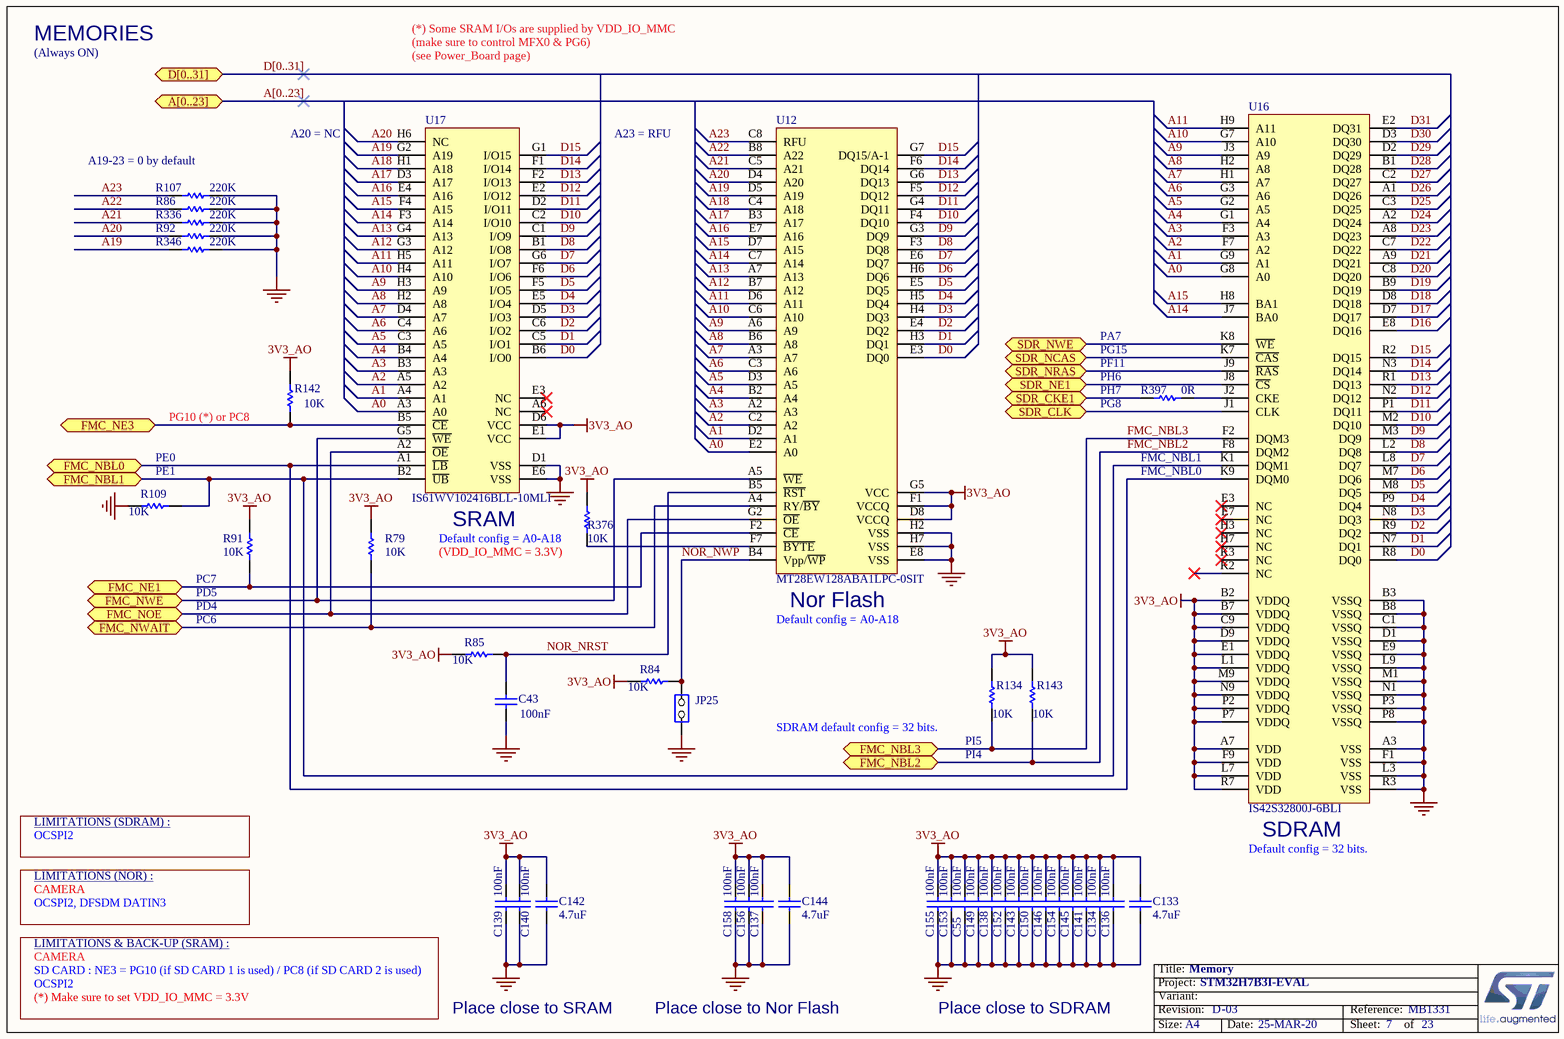
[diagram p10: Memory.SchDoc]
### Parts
C43  value 100nF  [C0402]  (hidden comment: Capacitor)
C55  value 100nF  [C0402]  (hidden comment: Capacitor)
C133  value 4.7uF  [C0603]  (hidden comment: Capacitor)
C134  value 100nF  [C0402]  (hidden comment: Capacitor)
C136  value 100nF  [C0402]  (hidden comment: Capacitor)
C137  value 100nF  [C0402]  (hidden comment: Capacitor)
C138  value 100nF  [C0402]  (hidden comment: Capacitor)
C139  value 100nF  [C0402]  (hidden comment: Capacitor)
C140  value 100nF  [C0402]  (hidden comment: Capacitor)
C141  value 100nF  [C0402]  (hidden comment: Capacitor)
C142  value 4.7uF  [C0603]  (hidden comment: Capacitor)
C143  value 100nF  [C0402]  (hidden comment: Capacitor)
C144  value 4.7uF  [C0603]  (hidden comment: Capacitor)
C145  value 100nF  [C0402]  (hidden comment: Capacitor)
C146  value 100nF  [C0402]  (hidden comment: Capacitor)
C149  value 100nF  [C0402]  (hidden comment: Capacitor)
C150  value 100nF  [C0402]  (hidden comment: Capacitor)
C152  value 100nF  [C0402]  (hidden comment: Capacitor)
C153  value 100nF  [C0402]  (hidden comment: Capacitor)
C154  value 100nF  [C0402]  (hidden comment: Capacitor)
C155  value 100nF  [C0402]  (hidden comment: Capacitor)
C156  value 100nF  [C0402]  (hidden comment: Capacitor)
C158  value 100nF  [C0402]  (hidden comment: Capacitor)
JP25  Jumper_Header 2x1  [CON_SAMTEC_TSW-102-07-G-S]  (value not drawn)
R79  value 10K  [R0402]  (hidden comment: Resistor)
R84  value 10K  [R0402]  (hidden comment: Resistor)
R85  value 10K  [R0402]  (hidden comment: Resistor)
R86  value 220K  [R0402]  (hidden comment: Resistor)
R91  value 10K  [R0402]  (hidden comment: Resistor)
R92  value 220K  [R0402]  (hidden comment: Resistor)
R107  value 220K  [R0402]  (hidden comment: Resistor)
R109  value 10K  [R0402]  (hidden comment: Resistor)
R134  value 10K  [R0402]  (hidden comment: Resistor)
R142  value 10K  [R0402]  (hidden comment: Resistor)
R143  value 10K  [R0402]  (hidden comment: Resistor)
R336  value 220K  [R0402]  (hidden comment: Resistor)
R346  value 220K  [R0402]  (hidden comment: Resistor)
R376  value 10K  [R0402]  (hidden comment: Resistor)
R397  value 0R  [R0402]  (hidden comment: Resistor)
U12  value MT28EW128ABA1LPC-0SIT  [ICC_FBGA64_11X13_P1]  (hidden comment: PC28F128M29EWLA)
U16  value IS42S32800J-6BLI  [ICC_TFBGA90_8X13_P080]  (hidden comment: IS42S32800G-6BLI)
U17  IS61WV102416BLL-10MLI  [ICC_MINI-BGA48_9X11_P075]

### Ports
A[0..23], D[0..31], FMC_NBL0, FMC_NBL1, FMC_NBL2, FMC_NBL3, FMC_NE1, FMC_NE3, FMC_NOE, FMC_NWAIT, FMC_NWE, SDR_CKE1, SDR_CLK, SDR_NCAS, SDR_NE1, SDR_NRAS, SDR_NWE

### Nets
3V3_AO: C55.1 C133.2 C134.1 C136.1 C137.1 C138.1 C139.1 C140.1 C141.1 C142.2 C143.1 C144.2 C145.1 C146.1 C149.1 C150.1 C152.1 C153.1 C154.1 C155.1 C156.1 C158.1 R79.2 R84.2 R85.1 R91.2 R134.2 R142.2 R143.2 R376.2 U12.D8(VCCQ) U12.F1(VCCQ) U12.G5(VCC) U16.A7(VDD) U16.B2(VDDQ) U16.B7(VDDQ) U16.C9(VDDQ) U16.D9(VDDQ) U16.E1(VDDQ) U16.F9(VDD) U16.L1(VDDQ) U16.L7(VDD) U16.M9(VDDQ) U16.N9(VDDQ) U16.P2(VDDQ) U16.P7(VDDQ) U16.R7(VDD) U17.D6(VCC) U17.E1(VCC)
GND: C43.2 C55.2 C133.1 C134.2 C136.2 C137.2 C138.2 C139.2 C140.2 C141.2 C142.1 C143.2 C144.1 C145.2 C146.2 C149.2 C150.2 C152.2 C153.2 C154.2 C155.2 C156.2 C158.2 JP25.1(COMMON) R86.1 R92.1 R107.1 R109.1 R336.1 R346.1 U12.E8(VSS) U12.H2(VSS) U12.H7(VSS) U16.A3(VSS) U16.B3(VSSQ) U16.B8(VSSQ) U16.C1(VSSQ) U16.D1(VSSQ) U16.E9(VSSQ) U16.F1(VSS) U16.L3(VSS) U16.L9(VSSQ) U16.M1(VSSQ) U16.N1(VSSQ) U16.P3(VSSQ) U16.P8(VSSQ) U16.R3(VSS) U17.D1(VSS) U17.E6(VSS)
A0: U12.E2(A0) U16.G8(A0) U17.A3(A0)
A1: U12.D2(A1) U16.G9(A1) U17.A4(A1)
A2: U12.C2(A2) U16.F7(A2) U17.A5(A2)
A3: U12.A2(A3) U16.F3(A3) U17.B3(A3)
A4: U12.B2(A4) U16.G1(A4) U17.B4(A4)
A5: U12.D3(A5) U16.G2(A5) U17.C3(A5)
A6: U12.C3(A6) U16.G3(A6) U17.C4(A6)
A7: U12.A3(A7) U16.H1(A7) U17.D4(A7)
A8: U12.B6(A8) U16.H2(A8) U17.H2(A8)
A9: U12.A6(A9) U16.J3(A9) U17.H3(A9)
A10: U12.C6(A10) U16.G7(A10) U17.H4(A10)
A11: U12.D6(A11) U16.H9(A11) U17.H5(A11)
A12: U12.B7(A12) U17.G3(A12)
A13: U12.A7(A13) U17.G4(A13)
A14: U12.C7(A14) U16.J7(BA0) U17.F3(A14)
A15: U12.D7(A15) U16.H8(BA1) U17.F4(A15)
A16: U12.E7(A16) U17.E4(A16)
A17: U12.B3(A17) U17.D3(A17)
A18: U12.C4(A18) U17.H1(A18)
A19: R346.2 U12.D5(A19) U17.G2(A19)
A20: R92.2 U12.D4(A20) U17.H6(NC)
A21: R336.2 U12.C5(A21)
A22: R86.2 U12.B8(A22)
A23: R107.2 U12.C8(RFU)
D0: U12.E3(DQ0) U16.R8(DQ0) U17.B6(I/O0)
D1: U12.H3(DQ1) U16.N7(DQ1) U17.C5(I/O1)
D2: U12.E4(DQ2) U16.R9(DQ2) U17.C6(I/O2)
D3: U12.H4(DQ3) U16.N8(DQ3) U17.D5(I/O3)
D4: U12.H5(DQ4) U16.P9(DQ4) U17.E5(I/O4)
D5: U12.E5(DQ5) U16.M8(DQ5) U17.F5(I/O5)
D6: U12.H6(DQ6) U16.M7(DQ6) U17.F6(I/O6)
D7: U12.E6(DQ7) U16.L8(DQ7) U17.G6(I/O7)
D8: U12.F3(DQ8) U16.L2(DQ8) U17.B1(I/O8)
D9: U12.G3(DQ9) U16.M3(DQ9) U17.C1(I/O9)
D10: U12.F4(DQ10) U16.M2(DQ10) U17.C2(I/O10)
D11: U12.G4(DQ11) U16.P1(DQ11) U17.D2(I/O11)
D12: U12.F5(DQ12) U16.N2(DQ12) U17.E2(I/O12)
D13: U12.G6(DQ13) U16.R1(DQ13) U17.F2(I/O13)
D14: U12.F6(DQ14) U16.N3(DQ14) U17.F1(I/O14)
D15: U12.G7(DQ15/A-1) U16.R2(DQ15) U17.G1(I/O15)
D16: U16.E8(DQ16)
D17: U16.D7(DQ17)
D18: U16.D8(DQ18)
D19: U16.B9(DQ19)
D20: U16.C8(DQ20)
D21: U16.A9(DQ21)
D22: U16.C7(DQ22)
D23: U16.A8(DQ23)
D24: U16.A2(DQ24)
D25: U16.C3(DQ25)
D26: U16.A1(DQ26)
D27: U16.C2(DQ27)
D28: U16.B1(DQ28)
D29: U16.D2(DQ29)
D30: U16.D3(DQ30)
D31: U16.E2(DQ31)
FMC_NBL0: U16.K9(DQM0) U17.A1(~{LB}) ; port FMC_NBL0
FMC_NBL1: R109.2 U16.K1(DQM1) U17.B2(~{UB}) ; port FMC_NBL1
FMC_NBL2: R143.1 U16.F8(DQM2) ; port FMC_NBL2
FMC_NBL3: R134.1 U16.F2(DQM3) ; port FMC_NBL3
FMC_NE1: R91.1 U12.F2(~{CE}) ; port FMC_NE1
FMC_NE3: R142.1 U17.B5(~{CE}) ; port FMC_NE3
FMC_NOE: U12.G2(~{OE}) U17.A2(~{OE}) ; port FMC_NOE
FMC_NWAIT: R79.1 U12.A4(RY/~{BY}) ; port FMC_NWAIT
FMC_NWE: U12.A5(~{WE}) U17.G5(~{WE}) ; port FMC_NWE
NOR_NRST: C43.1 R85.2 U12.B5(~{RST})
NOR_NWP: JP25.2(NO) R84.1 U12.B4(Vpp/~{WP})
SDR_CKE1: R397.1 ; port SDR_CKE1
SDR_CLK: U16.J1(CLK) ; port SDR_CLK
SDR_NCAS: U16.K7(~{CAS}) ; port SDR_NCAS
SDR_NE1: U16.J8(~{CS}) ; port SDR_NE1
SDR_NRAS: U16.J9(~{RAS}) ; port SDR_NRAS
SDR_NWE: U16.K8(~{WE}) ; port SDR_NWE
NetR376_1: R376.1 U12.F7(~{BYTE})
NetR397_2: R397.2 U16.J2(CKE)

Not connected (* = marked no-connect by the designer): U16 E3(NC)* E7(NC)* H3(NC)* H7(NC)* K2(NC)* K3(NC)*; U17 A6(NC)* E3(NC)*

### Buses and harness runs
bus A[0..23] = port A[0..23]
bus D[0..31] = port D[0..31]

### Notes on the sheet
- MEMORIES
- (Always ON)
- (*) Some SRAM I/Os are supplied by VDD_IO_MMC
  (make sure to control MFX0 & PG6)
  (see Power_Board page)
- A19-23 = 0 by default
- A20 = NC
- A23 = RFU
- PA7
- (near R397) PG15
- (near R397) PF11
- (near R397) PH6
- (near R142) PG10 (*) or PC8
- (near R397) PH7
- (near R397) PG8
- (near R109) PE1
- (near R109) PE0
- FMC_NBL1
- FMC_NBL0
- (near R91) PC7
- (near R376) Default config = A0-A18
- (near R376) (VDD_IO_MMC = 3.3V)
- (near U17) SRAM
- (near R91) PD5
- PC6
- PD4
- Default config = A0-A18
- (near U12) Nor Flash
- (near R134) SDRAM default config = 32 bits.
- (near R134) PI5
- PI4
- OCSPI2
- LIMITATIONS (SDRAM) :
- Default config = 32 bits.
- (near U16) SDRAM
- CAMERA
- LIMITATIONS (NOR) :
- OCSPI2, DFSDM DATIN3
- SD CARD : NE3 = PG10 (if SD CARD 1 is used) / PC8 (if SD CARD 2 is used)
- LIMITATIONS & BACK-UP (SRAM) :
- (*) Make sure to set VDD_IO_MMC = 3.3V
- Place close to SRAM
- Place close to Nor Flash
- Place close to SDRAM

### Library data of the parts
C43 C55 C134 C136-C141 C143 C145 C146 C149 C150 C152-C156 C158 = MCD-00006: as C76 on sheet LCD
C133 C142 C144 = MCD-01121: Capacitor, MLCC, 4.7uF, 10V, X5R, 20%, 0603, T=0,8mm; Manufacturer_Part_Number: GRM188R61A475ME15; Manufacturer: MURATA; Provided_By: SUBCO; ECCN_US: EAR99; ECCN_EU: NEC
JP25 = MCD-00045: as JP22 on sheet MCU_Clock&Reset
R79 R84 R85 R91 R109 R134 R142 R143 R376 = MCD-00053: as R395 on sheet JTAG&Trace
R86 R92 R107 R336 R346 = MCD-00164: Resistor,220K,0402,1%,1/16W; Manufacturer_Part_Number: RC0402FR-07220KL; Manufacturer: YAGEO; Provided_By: SUBCO; ECCN_US: EAR99; ECCN_EU: NEC
R397 = MCD-00052: as R372 on sheet JTAG&Trace
U12 = MCD-01345: NOR FLASH 128Mbit 75ns - 64-ball LBGA (replacing PC28F128M29EWLA); Part_Type: IC; Manufacturer: MICRON; Provided_By: SUBCO; ECCN_US: 3A991; ECCN_EU: NEC
U16 = MCD-00562: SDRAM 256MBit 166MHZ 90BGA; Part_Type: IC; Manufacturer: ISSI; Provided_By: SUBCO; ECCN_US: EAR99; ECCN_EU: NEC
U17 = MCD-00560: SRAM 16Mb 10ns 1Mx16 Async SRAM 3.3v; Manufacturer: ISSI; Part_Type: IC; Provided_By: SUBCO

## Sheet MFX.SchDoc: MFX I/O Expander
size A4; Date: Not used; ApprovedBy: Not used; CheckedBy: Not used; Author: Not used; CompanyName: STMicroelectronics; DrawnBy: Not used; Engineer: Not used; Organization: Not used; Address1: Not used; Address2: Not used; Address3: Not used; Address4: Not used; DocumentNumber: Not used; Revision: Not used; SheetNumber: 18; SheetTotal: 23

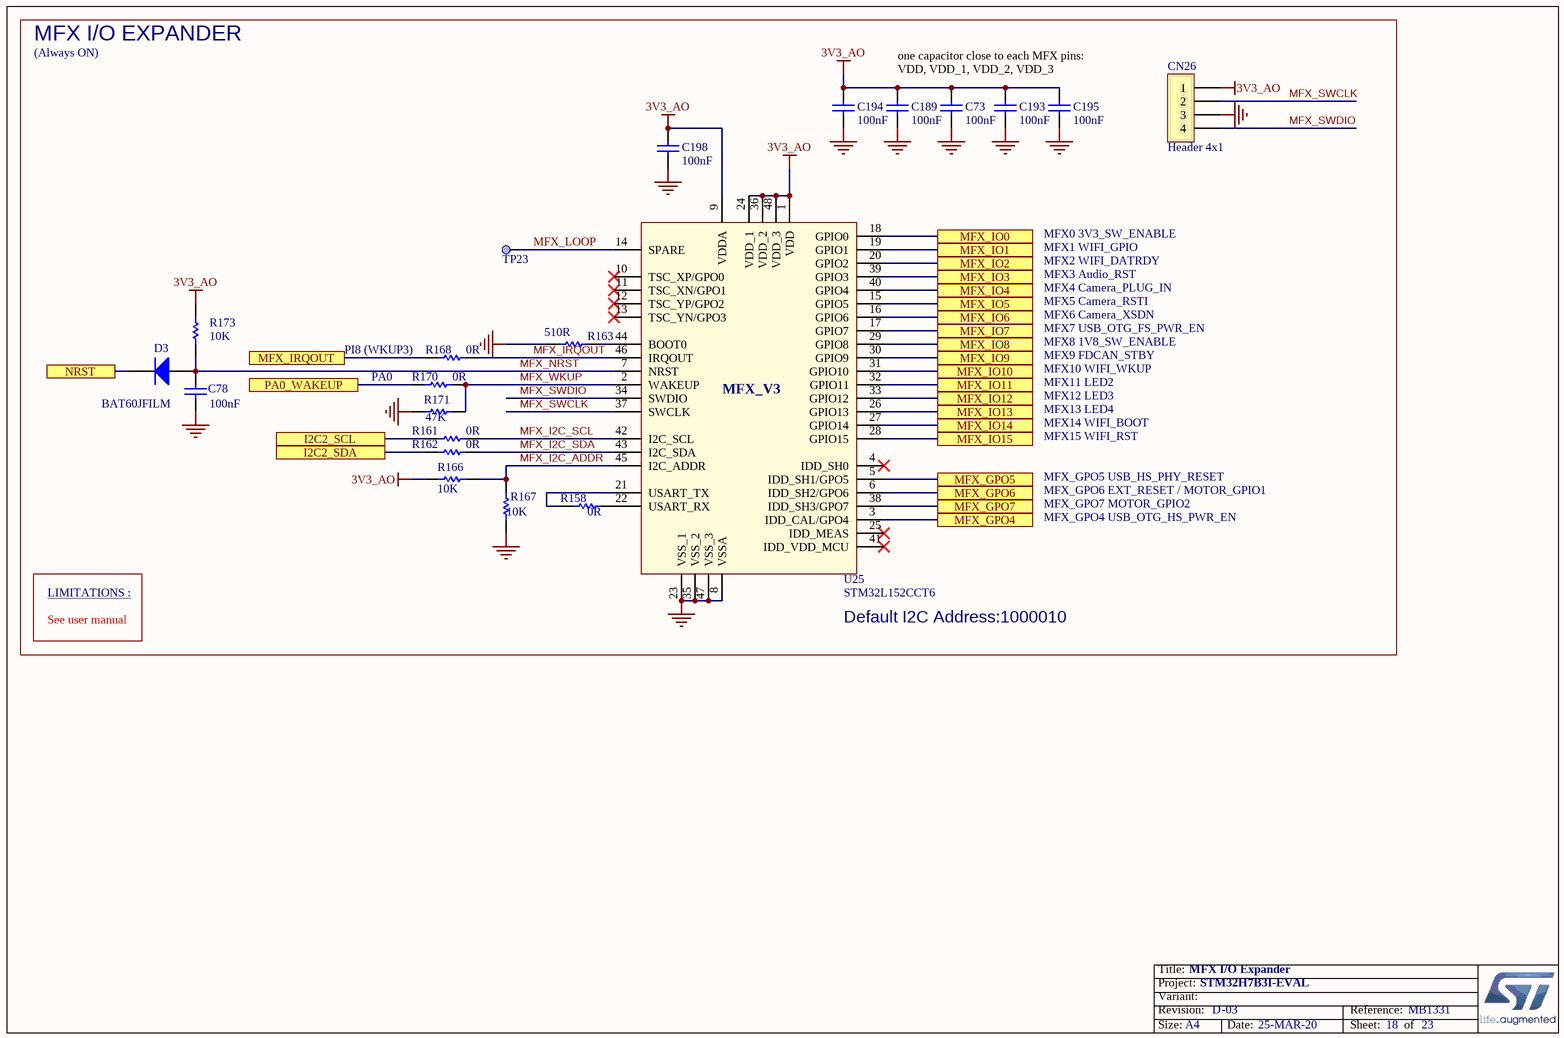
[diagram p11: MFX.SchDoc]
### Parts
C73  value 100nF  [C0402]  (hidden comment: Capacitor)
C78  value 100nF  [C0402]  (hidden comment: Capacitor)
C189  value 100nF  [C0402]  (hidden comment: Capacitor)
C193  value 100nF  [C0402]  (hidden comment: Capacitor)
C194  value 100nF  [C0402]  (hidden comment: Capacitor)
C195  value 100nF  [C0402]  (hidden comment: Capacitor)
C198  value 100nF  [C0402]  (hidden comment: Capacitor)
CN26  Header 4x1  [CON_SAMTEC_TSW-104-07-G-S]
D3  BAT60JFILM  [DIO_SOD323]
R158  value 0R  [R0603]  (hidden comment: Resistor)
R161  value 0R  [R0402]  (hidden comment: Resistor)
R162  value 0R  [R0402]  (hidden comment: Resistor)
R163  value 510R  [R0402]  (hidden comment: Resistor)
R166  value 10K  [R0402]  (hidden comment: Resistor)
R167  value 10K  [R0402]  (hidden comment: Resistor)
R168  value 0R  [R0603]  (hidden comment: Resistor)
R170  value 0R  [R0603]  (hidden comment: Resistor)
R171  value 47K  [R0402]  (hidden comment: Resistor)
R173  value 10K  [R0402]  (hidden comment: Resistor)
TP23  Test Point  [TP_SMD_1MM]  (value not drawn)  (no BOM)
U25  STM32L152CCT6  [ICC_LQFP48_7X7_P050]

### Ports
I2C2_SCL, I2C2_SDA, MFX_GPO4, MFX_GPO5, MFX_GPO6, MFX_GPO7, MFX_IO0, MFX_IO1, MFX_IO2, MFX_IO3, MFX_IO4, MFX_IO5, MFX_IO6, MFX_IO7, MFX_IO8, MFX_IO9, MFX_IO10, MFX_IO11, MFX_IO12, MFX_IO13, MFX_IO14, MFX_IO15, MFX_IRQOUT, NRST, PA0_WAKEUP

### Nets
3V3_AO: C73.1 C189.2 C193.2 C194.2 C195.2 C198.2 CN26.1 R166.1 R173.2 U25.1(VDD) U25.9(VDDA) U25.24(VDD_1) U25.36(VDD_2) U25.48(VDD_3)
GND: C73.2 C78.1 C189.1 C193.1 C194.1 C195.1 C198.1 CN26.3 R163.2 R167.2 R171.1 U25.8(VSSA) U25.23(VSS_1) U25.35(VSS_2) U25.47(VSS_3)
I2C2_SCL: R161.1 ; port I2C2_SCL
I2C2_SDA: R162.1 ; port I2C2_SDA
MFX_GPO4: U25.3(IDD_CAL/GPO4) ; port MFX_GPO4
MFX_GPO5: U25.5(IDD_SH1/GPO5) ; port MFX_GPO5
MFX_GPO6: U25.6(IDD_SH2/GPO6) ; port MFX_GPO6
MFX_GPO7: U25.38(IDD_SH3/GPO7) ; port MFX_GPO7
MFX_I2C_ADDR: R166.2 R167.1 U25.45(I2C_ADDR)
MFX_I2C_SCL: R161.2 U25.42(I2C_SCL)
MFX_I2C_SDA: R162.2 U25.43(I2C_SDA)
MFX_IO0: U25.18(GPIO0) ; port MFX_IO0
MFX_IO1: U25.19(GPIO1) ; port MFX_IO1
MFX_IO2: U25.20(GPIO2) ; port MFX_IO2
MFX_IO3: U25.39(GPIO3) ; port MFX_IO3
MFX_IO4: U25.40(GPIO4) ; port MFX_IO4
MFX_IO5: U25.15(GPIO5) ; port MFX_IO5
MFX_IO6: U25.16(GPIO6) ; port MFX_IO6
MFX_IO7: U25.17(GPIO7) ; port MFX_IO7
MFX_IO8: U25.29(GPIO8) ; port MFX_IO8
MFX_IO9: U25.30(GPIO9) ; port MFX_IO9
MFX_IO10: U25.31(GPIO10) ; port MFX_IO10
MFX_IO11: U25.32(GPIO11) ; port MFX_IO11
MFX_IO12: U25.33(GPIO12) ; port MFX_IO12
MFX_IO13: U25.26(GPIO13) ; port MFX_IO13
MFX_IO14: U25.27(GPIO14) ; port MFX_IO14
MFX_IO15: U25.28(GPIO15) ; port MFX_IO15
MFX_IRQOUT: R168.2 U25.46(IRQOUT)
MFX_LOOP: TP23.1 U25.14(SPARE)
MFX_NRST: C78.2 D3.1(A) R173.1 U25.7(NRST)
MFX_SWCLK: CN26.2 U25.37(SWCLK)
MFX_SWDIO: CN26.4 U25.34(SWDIO)
MFX_WKUP: R170.1 R171.2 U25.2(WAKEUP)
NRST: D3.2(K) ; port NRST
PA0_WAKEUP: R170.2 ; port PA0_WAKEUP
PI8: R168.1 ; port MFX_IRQOUT
NetR158_1: R158.1 U25.21(USART_TX)
NetR158_2: R158.2 U25.22(USART_RX)
NetR163_1: R163.1 U25.44(BOOT0)

Not connected (* = marked no-connect by the designer): U25 4(IDD_SH0)* 10(TSC_XP/GPO0)* 11(TSC_XN/GPO1)* 12(TSC_YP/GPO2)* 13(TSC_YN/GPO3)* 25(IDD_MEAS)* 41(IDD_VDD_MCU)*

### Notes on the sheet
- MFX I/O EXPANDER
- (Always ON)
- one capacitor close to each MFX pins: VDD, VDD_1, VDD_2, VDD_3
- PI8 (WKUP3)
- PA0
- MFX0	3V3_SW_ENABLE
  MFX1	WIFI_GPIO
  MFX2	WIFI_DATRDY
  MFX3	Audio_RST
  MFX4	Camera_PLUG_IN
  MFX5	Camera_RSTI
  MFX6	Camera_XSDN
  MFX7	USB_OTG_FS_PWR_EN
  MFX8	1V8_SW_ENABLE
  MFX9	FDCAN_STBY
  MFX10	WIFI_WKUP
  MFX11	LED2
  MFX12	LED3
  MFX13	LED4
  MFX14	WIFI_BOOT
  MFX15	WIFI_RST
- MFX_GPO5	USB_HS_PHY_RESET
  MFX_GPO6	EXT_RESET / MOTOR_GPIO1
  MFX_GPO7	MOTOR_GPIO2
  MFX_GPO4	USB_OTG_HS_PWR_EN
- LIMITATIONS :
- See user manual
- (near U25) Default I2C Address:1000010

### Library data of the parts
C73 C78 C189 C193-C195 C198 = MCD-00006: as C76 on sheet LCD
CN26 = MCD-00029: Header, 4x1, 2,54mm, VR, TH, Height 5.84mm/2.54mm; Manufacturer_Part_Number: TSW-104-07-x-S; Manufacturer: SAMTEC; Part_Type: Connector; Provided_By: SUBCO
D3 = MCD-00034: as D1 on sheet MCU_Clock&Reset
R158 R168 R170 = MCD-00056: as R125 on sheet LCD
R161 R162 = MCD-00052: as R372 on sheet JTAG&Trace
R163 = MCD-00064: Resistor,510R,0402,1%,1/16W; Manufacturer_Part_Number: RC0402FR-07510RL; Manufacturer: YAGEO; Provided_By: SUBCO; ECCN_US: EAR99; ECCN_EU: NEC
R166 R167 R173 = MCD-00053: as R395 on sheet JTAG&Trace
R171 = MCD-00063: Resistor,47K,0402,1%,1/16W; Manufacturer_Part_Number: RC0402FR-0747KL; Manufacturer: YAGEO; Provided_By: SUBCO; ECCN_US: EAR99; ECCN_EU: NEC
TP23 = MCD-00074: Test Point 1mm; Part_Type: Mechanical
U25 = MCD-00135: Ultra-low-power 32-bit MCU ARM; Manufacturer: STMICROELECTRONICS; Part_Type: IC; Provided_By: SUBCO with ST control; ECCN_US: 3A991A2; ECCN_EU: NEC

## Sheet MotorControl.SchDoc: Motor Control
size A4; SheetNumber: 17; SheetTotal: 23

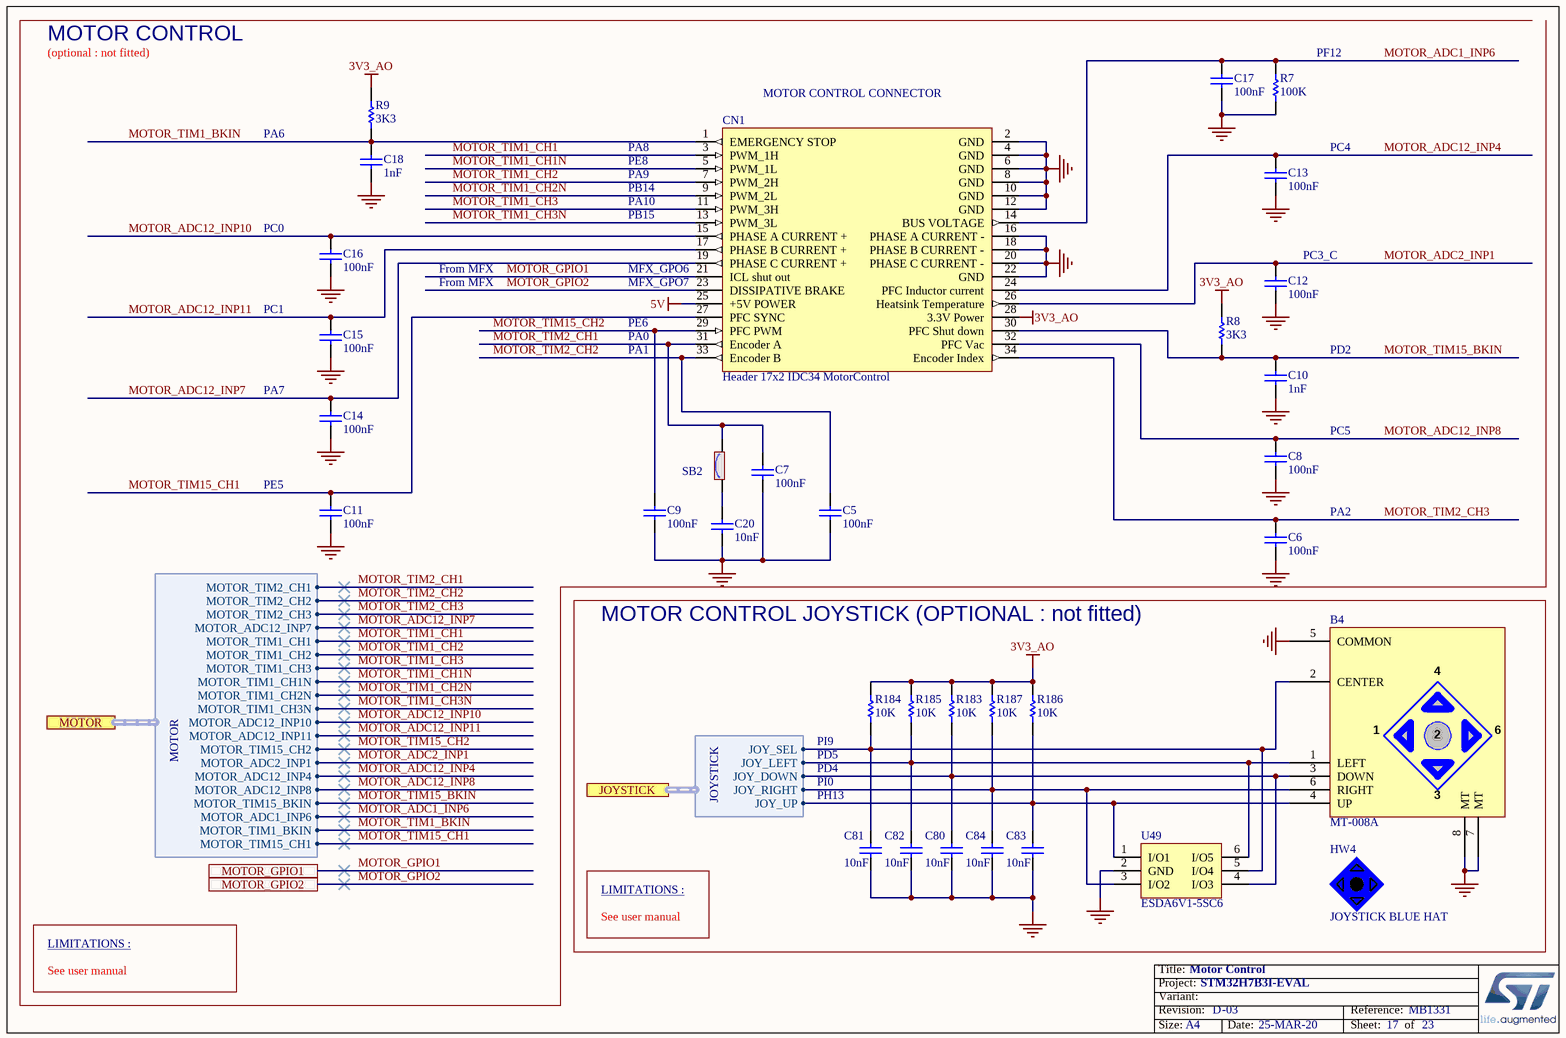
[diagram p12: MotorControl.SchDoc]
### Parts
B4  value MT-008A  [SWI_XIEJIA_MT-008A_6P]  (hidden comment: Joystick MT-008A_M)
C5  value 100nF  [C0402]  (hidden comment: Capacitor)
C6  value 100nF  [C0402]  (hidden comment: Capacitor)
C7  value 100nF  [C0402]  (hidden comment: Capacitor)
C8  value 100nF  [C0402]  (hidden comment: Capacitor)
C9  value 100nF  [C0402]  (hidden comment: Capacitor)
C10  value 1nF  [C0402]  (hidden comment: Capacitor)
C11  value 100nF  [C0402]  (hidden comment: Capacitor)
C12  value 100nF  [C0402]  (hidden comment: Capacitor)
C13  value 100nF  [C0402]  (hidden comment: Capacitor)
C14  value 100nF  [C0402]  (hidden comment: Capacitor)
C15  value 100nF  [C0402]  (hidden comment: Capacitor)
C16  value 100nF  [C0402]  (hidden comment: Capacitor)
C17  value 100nF  [C0402]  (hidden comment: Capacitor)
C18  value 1nF  [C0402]  (hidden comment: Capacitor)
C20  value 10nF  [C0402]  (hidden comment: Capacitor)
C80  value 10nF  [C0402]  (hidden comment: Capacitor)
C81  value 10nF  [C0402]  (hidden comment: Capacitor)
C82  value 10nF  [C0402]  (hidden comment: Capacitor)
C83  value 10nF  [C0402]  (hidden comment: Capacitor)
C84  value 10nF  [C0402]  (hidden comment: Capacitor)
CN1  Header 17x2 IDC34 MotorControl  [CON_SAMTEC_TST-117-01-T-D]
HW4  value JOYSTICK BLUE HAT  (hidden comment: JOYSTICK_BLUE_HAT)  (mechanical)
R7  value 100K  [R0603]  (hidden comment: Resistor)
R8  value 3K3  [R0402]  (hidden comment: Resistor)
R9  value 3K3  [R0402]  (hidden comment: Resistor)
R183  value 10K  [R0402]  (hidden comment: Resistor)
R184  value 10K  [R0402]  (hidden comment: Resistor)
R185  value 10K  [R0402]  (hidden comment: Resistor)
R186  value 10K  [R0402]  (hidden comment: Resistor)
R187  value 10K  [R0402]  (hidden comment: Resistor)
SB2  SB_ON  [SOLDER-BRIDGE_R0603-0R]  (value not drawn)
U49  ESDA6V1-5SC6  [ESD_SOT23-6L]

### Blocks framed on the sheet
MOTOR CONTROL JOYSTICK (OPTIONAL : not fitted): B4 C80-C84 HW4 R183-R187 U49

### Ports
JOYSTICK (harness JOYSTICK), MOTOR (harness MOTOR), MOTOR_GPIO1, MOTOR_GPIO2

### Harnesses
MOTOR: MOTOR_TIM2_CH1, MOTOR_TIM2_CH2, MOTOR_TIM2_CH3, MOTOR_ADC12_INP7, MOTOR_TIM1_CH1, MOTOR_TIM1_CH2, MOTOR_TIM1_CH3, MOTOR_TIM1_CH1N, MOTOR_TIM1_CH2N, MOTOR_TIM1_CH3N, MOTOR_ADC12_INP10, MOTOR_ADC12_INP11, MOTOR_TIM15_CH2, MOTOR_ADC2_INP1, MOTOR_ADC12_INP4, MOTOR_ADC12_INP8, MOTOR_TIM15_BKIN, MOTOR_ADC1_INP6, MOTOR_TIM1_BKIN, MOTOR_TIM15_CH1
JOYSTICK: JOY_SEL, JOY_LEFT, JOY_DOWN, JOY_RIGHT, JOY_UP

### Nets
3V3_AO: CN1.28(3.3V_Power) R8.2 R9.2 R183.2 R184.2 R185.2 R186.2 R187.2
5V: CN1.25(+5V_POWER)
GND: B4.5(COMMON) B4.7(MT) B4.8(MT) C5.1 C6.1 C7.1 C8.1 C9.1 C10.1 C11.1 C12.1 C13.1 C14.1 C15.1 C16.1 C17.1 C18.1 C20.1 C80.1 C81.1 C82.1 C83.1 C84.1 CN1.2(GND) CN1.4(GND) CN1.6(GND) CN1.8(GND) CN1.10(GND) CN1.12(GND) CN1.16(PHASE_A_CURRENT_-) CN1.18(PHASE_B_CURRENT_-) CN1.20(PHASE_C_CURRENT_-) CN1.22(GND) R7.1 U49.2(GND)
MOTOR_ADC1_INP6: C17.2 CN1.14(BUS_VOLTAGE) R7.2 ; port MOTOR.MOTOR_ADC1_INP6
MOTOR_ADC2_INP1: C12.2 CN1.26(Heatsink_Temperature) ; port MOTOR.MOTOR_ADC2_INP1
MOTOR_ADC12_INP4: C13.2 CN1.24(PFC_Inductor_current) ; port MOTOR.MOTOR_ADC12_INP4
MOTOR_ADC12_INP7: C14.2 CN1.19(PHASE_C_CURRENT_+) ; port MOTOR.MOTOR_ADC12_INP7
MOTOR_ADC12_INP8: C8.2 CN1.32(PFC_Vac) ; port MOTOR.MOTOR_ADC12_INP8
MOTOR_ADC12_INP10: C16.2 CN1.15(PHASE_A_CURRENT_+) ; port MOTOR.MOTOR_ADC12_INP10
MOTOR_ADC12_INP11: C15.2 CN1.17(PHASE_B_CURRENT_+) ; port MOTOR.MOTOR_ADC12_INP11
MOTOR_GPIO1: CN1.21(ICL_shut_out) ; port MOTOR_GPIO1
MOTOR_GPIO2: CN1.23(DISSIPATIVE_BRAKE) ; port MOTOR_GPIO2
MOTOR_TIM1_BKIN: C18.2 CN1.1(EMERGENCY_STOP) R9.1 ; port MOTOR.MOTOR_TIM1_BKIN
MOTOR_TIM1_CH1: CN1.3(PWM_1H) ; port MOTOR.MOTOR_TIM1_CH1
MOTOR_TIM1_CH1N: CN1.5(PWM_1L) ; port MOTOR.MOTOR_TIM1_CH1N
MOTOR_TIM1_CH2: CN1.7(PWM_2H) ; port MOTOR.MOTOR_TIM1_CH2
MOTOR_TIM1_CH2N: CN1.9(PWM_2L) ; port MOTOR.MOTOR_TIM1_CH2N
MOTOR_TIM1_CH3: CN1.11(PWM_3H) ; port MOTOR.MOTOR_TIM1_CH3
MOTOR_TIM1_CH3N: CN1.13(PWM_3L) ; port MOTOR.MOTOR_TIM1_CH3N
MOTOR_TIM2_CH1: C7.2 CN1.31(Encoder_A) SB2.1 ; port MOTOR.MOTOR_TIM2_CH1
MOTOR_TIM2_CH2: C5.2 CN1.33(Encoder_B) ; port MOTOR.MOTOR_TIM2_CH2
MOTOR_TIM2_CH3: C6.2 CN1.34(Encoder_Index) ; port MOTOR.MOTOR_TIM2_CH3
MOTOR_TIM15_BKIN: C10.2 CN1.30(PFC_Shut_down) R8.1 ; port MOTOR.MOTOR_TIM15_BKIN
MOTOR_TIM15_CH1: C11.2 CN1.27(PFC_SYNC) ; port MOTOR.MOTOR_TIM15_CH1
MOTOR_TIM15_CH2: C9.2 CN1.29(PFC_PWM) ; port MOTOR.MOTOR_TIM15_CH2
NetB4_1: B4.1(LEFT) C82.2 R185.1 U49.6(I/O5) ; port JOYSTICK.JOY_LEFT
NetB4_2: B4.2(CENTER) C81.2 R184.1 U49.5(I/O4) ; port JOYSTICK.JOY_SEL
NetB4_3: B4.3(DOWN) C80.2 R183.1 U49.4(I/O3) ; port JOYSTICK.JOY_DOWN
NetB4_4: B4.4(UP) C83.2 R186.1 U49.1(I/O1) ; port JOYSTICK.JOY_UP
NetB4_6: B4.6(RIGHT) C84.2 R187.1 U49.3(I/O2) ; port JOYSTICK.JOY_RIGHT
NetC20_2: C20.2 SB2.2

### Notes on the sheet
- MOTOR CONTROL
- (optional : not fitted)
- (near CN1) MOTOR CONTROL CONNECTOR
- (near R7) PF12
- PA6
- PA9
- PA8
- PE8
- PC4
- (near C16) PC0
- PB14
- PB15
- PA10
- PC1
- From MFX
- (near CN1) MFX_GPO6
- (near CN1) MFX_GPO7
- (near C12) PC3_C
- PA1
- PA0
- PE6
- PD2
- PA7
- PC5
- PE5
- PA2
- (near R184) PD5
- PD4
- PI0
- (near R184) PI9
- PH13
- LIMITATIONS :
- See user manual

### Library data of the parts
B4 = MCD-00132: Joystick, 4 dir, 1 OK; Part_Type: Misc; Manufacturer: XIEJIA Electronics; Provided_By: SUBCO
C5-C9 C11-C17 = MCD-00006: as C76 on sheet LCD
C10 C18 = MCD-00198: Capacitor, MLCC, 1nF, 16V, X7R, 10%, 0402, T=0.5mm; Manufacturer_Part_Number: CC0402KRX7R7BB102; Manufacturer: YAGEO; Provided_By: SUBCO; ECCN_US: EAR99; ECCN_EU: NEC
C20 C80-C84 = MCD-00011: Capacitor, MLCC, 10nF, 16V, X7R, 10%, 0402, T=0.5mm; Manufacturer_Part_Number: CC0402KRX7R7BB103; Manufacturer: YAGEO; Provided_By: SUBCO; ECCN_US: EAR99; ECCN_EU: NEC
CN1 = MCD-00583: Header, 17x2, 2.54mm, VR, TH, Height 8.89mm/2.92mm, shrouded; Manufacturer_Part_Number: TST-117-01-T-D; Manufacturer: SAMTEC; Part_Type: Connector; Alternate_Manufacturer_Part_Number: BHFS03-34G01BT1; Alternate_Manufacturer: WINPIN; Provided_By: SUBCO
HW4 = MCD-01337: Joystick Blue Hat; Part_Type: Mechanical; Manufacturer_Part_Number: PB-504; Manufacturer: JIUBABA; Provided_By: SUBCO
R7 = MCD-00223: Resistor,100K,0603,1%,1/10W; Manufacturer_Part_Number: RC0603FR-07100KL; Manufacturer: YAGEO; Provided_By: SUBCO; ECCN_US: EAR99; ECCN_EU: NEC
R8 R9 = MCD-00184: Resistor,3K3,0402,1%,1/16W; Manufacturer_Part_Number: RC0402FR-073K3L; Manufacturer: YAGEO; Provided_By: SUBCO; ECCN_US: EAR99; ECCN_EU: NEC
R183-R187 = MCD-00053: as R395 on sheet JTAG&Trace
SB2 = MCD-00071: as SB43 on sheet JTAG&Trace
U49 = MCD-01066: 5 unidirectional Transil diodes ESD protection; Part_Type: Diode; Manufacturer: STMICROELECTRONICS; BMS_Part_Number: 9179044; Provided_By: SUBCO with ST control; ECCN_US: EAR99; ECCN_EU: NEC

## Sheet OCSPI.SchDoc: OCSPI
size A4; Date: Not used; ApprovedBy: Not used; CheckedBy: Not used; Author: Not used; CompanyName: STMicroelectronics; DrawnBy: Not used; Engineer: Not used; Organization: Not used; Address1: Not used; Address2: Not used; Address3: Not used; Address4: Not used; DocumentNumber: Not used; Revision: Not used; SheetNumber: 8; SheetTotal: 23

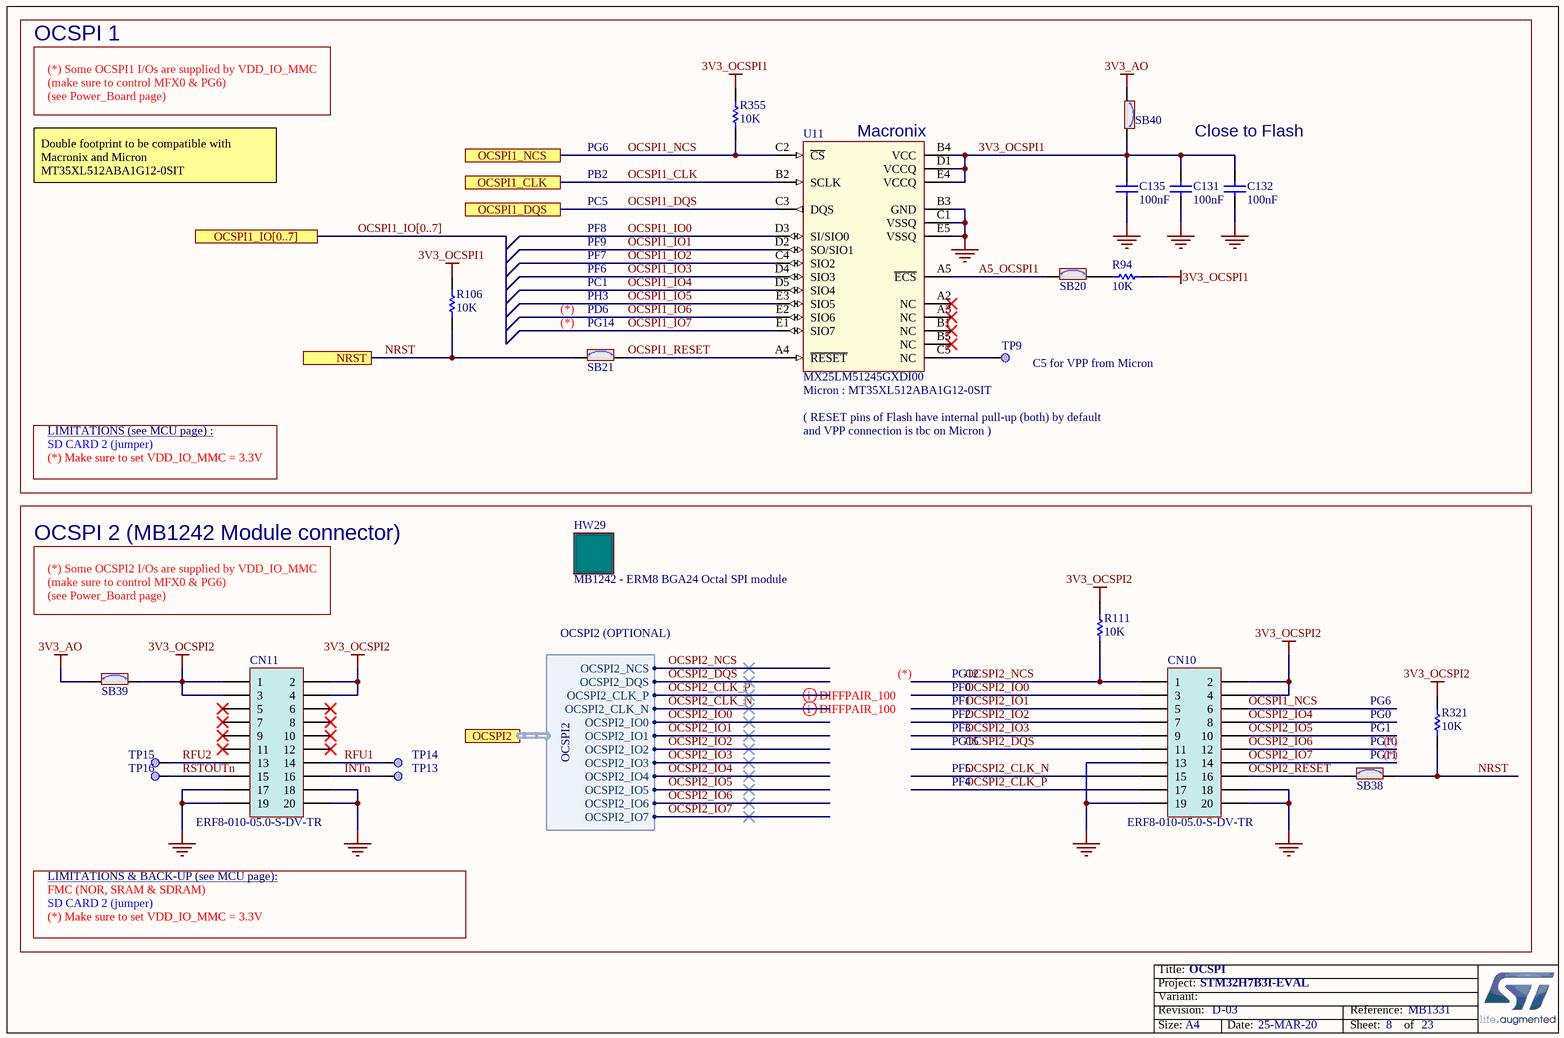
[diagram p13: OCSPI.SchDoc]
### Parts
C131  value 100nF  [C0402]  (hidden comment: Capacitor)
C132  value 100nF  [C0402]  (hidden comment: Capacitor)
C135  value 100nF  [C0402]  (hidden comment: Capacitor)
CN10  value ERF8-010-05.0-S-DV-TR  [CON_SAMTEC_ERF8-010-050-S-DV-TR]  (hidden comment: Socket 10x2)
CN11  value ERF8-010-05.0-S-DV-TR  [CON_SAMTEC_ERF8-010-050-S-DV-TR]  (hidden comment: Socket 10x2)
HW29  value MB1242 - ERM8 BGA24 Octal SPI module  [MOD_ERM8_BGA24-OCTAL-SPI_MB1242]  (hidden comment: Daughter_Board)
R94  value 10K  [R0402]  (hidden comment: Resistor)
R106  value 10K  [R0402]  (hidden comment: Resistor)
R111  value 10K  [R0402]  (hidden comment: Resistor)
R321  value 10K  [R0402]  (hidden comment: Resistor)
R355  value 10K  [R0402]  (hidden comment: Resistor)
SB20  SB_ON  [SOLDER-BRIDGE_R0603-0R]  (value not drawn)
SB21  SB_ON  [SOLDER-BRIDGE_R0603-0R]  (value not drawn)
SB38  SB_ON  [SOLDER-BRIDGE_R0603-0R]  (value not drawn)
SB39  SB_ON  [SOLDER-BRIDGE_R0603-0R]  (value not drawn)
SB40  SB_ON  [SOLDER-BRIDGE_R0603-0R]  (value not drawn)
TP9  Test Point  [TP_SMD_1MM]  (value not drawn)  (no BOM)
TP13  Test Point  [TP_SMD_1MM]  (value not drawn)  (no BOM)
TP14  Test Point  [TP_SMD_1MM]  (value not drawn)  (no BOM)
TP15  Test Point  [TP_SMD_1MM]  (value not drawn)  (no BOM)
TP16  Test Point  [TP_SMD_1MM]  (value not drawn)  (no BOM)
U11  MX25LM51245GXDI00  [ICC_BGA24_5X5-BALL-ARRAY_6X8_P1]

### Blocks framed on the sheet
OCSPI 1: C131 C132 C135 R94 R106 R355 SB20 SB21 SB40 TP9 U11
OCSPI 2 (MB1242 Module connector): CN10 CN11 HW29 R111 R321 SB38 SB39 TP13-TP16

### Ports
NRST, OCSPI1_CLK, OCSPI1_DQS, OCSPI1_IO[0..7], OCSPI1_NCS, OCSPI2 (harness OCSPI2)

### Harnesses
OCSPI2: OCSPI2_NCS, OCSPI2_DQS, OCSPI2_CLK_P, OCSPI2_CLK_N, OCSPI2_IO0, OCSPI2_IO1, OCSPI2_IO2, OCSPI2_IO3, OCSPI2_IO4, OCSPI2_IO5, OCSPI2_IO6, OCSPI2_IO7

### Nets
3V3_AO: SB39.2 SB40.1
3V3_OCSPI1: C131.2 C132.2 C135.2 R94.2 R106.1 R355.1 SB40.2 U11.B4(VCC) U11.D1(VCCQ) U11.E4(VCCQ)
3V3_OCSPI2: CN10.2 CN10.4 CN11.1 CN11.2 CN11.3 CN11.4 R111.1 R321.1 SB39.1
GND: C131.1 C132.1 C135.1 CN10.13 CN10.18 CN10.19 CN10.20 CN11.17 CN11.18 CN11.19 CN11.20 U11.B3(GND) U11.C1(VSSQ) U11.E5(VSSQ)
A5_OCSPI1: SB20.1 U11.A5(~{ECS})
INTn: CN11.16 TP13.1
NRST: R106.2 R321.2 SB21.1 SB38.1 ; port NRST
OCSPI1_CLK: U11.B2(SCLK) ; port OCSPI1_CLK
OCSPI1_DQS: U11.C3(DQS) ; port OCSPI1_DQS
OCSPI1_IO0: U11.D3(SI/SIO0)
OCSPI1_IO1: U11.D2(SO/SIO1)
OCSPI1_IO2: U11.C4(SIO2)
OCSPI1_IO3: U11.D4(SIO3)
OCSPI1_IO4: U11.D5(SIO4)
OCSPI1_IO5: U11.E3(SIO5)
OCSPI1_IO6: U11.E2(SIO6)
OCSPI1_IO7: U11.E1(SIO7)
OCSPI1_NCS: CN10.6 R355.2 U11.C2(~{CS}) ; port OCSPI1_NCS
OCSPI1_RESET: SB21.2 U11.A4(~{RESET})
OCSPI2_CLK_N: CN10.15 ; port OCSPI2.OCSPI2_CLK_N
OCSPI2_CLK_P: CN10.17 ; port OCSPI2.OCSPI2_CLK_P
OCSPI2_DQS: CN10.11 ; port OCSPI2.OCSPI2_DQS
OCSPI2_IO0: CN10.3 ; port OCSPI2.OCSPI2_IO0
OCSPI2_IO1: CN10.5 ; port OCSPI2.OCSPI2_IO1
OCSPI2_IO2: CN10.7 ; port OCSPI2.OCSPI2_IO2
OCSPI2_IO3: CN10.9 ; port OCSPI2.OCSPI2_IO3
OCSPI2_IO4: CN10.8 ; port OCSPI2.OCSPI2_IO4
OCSPI2_IO5: CN10.10 ; port OCSPI2.OCSPI2_IO5
OCSPI2_IO6: CN10.12 ; port OCSPI2.OCSPI2_IO6
OCSPI2_IO7: CN10.14 ; port OCSPI2.OCSPI2_IO7
OCSPI2_NCS: CN10.1 R111.2 ; port OCSPI2.OCSPI2_NCS
OCSPI2_RESET: CN10.16 SB38.2
RFU1: CN11.14 TP14.1
RFU2: CN11.13 TP15.1
RSTOUTn: CN11.15 TP16.1
NetR94_1: R94.1 SB20.2
NetTP9_1: TP9.1 U11.C5(NC)

Not connected (* = marked no-connect by the designer): CN11 5* 6* 7* 8* 9* 10* 11* 12*; U11 A2(NC)* A3(NC)* B1(NC)* B5(NC)*

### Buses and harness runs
bus OCSPI1_IO[0..7] = port OCSPI1_IO[0..7]

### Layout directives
differential pair: OCSPI2_CLK_N, OCSPI2_CLK_P

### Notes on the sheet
- (*) Some OCSPI1 I/Os are supplied by VDD_IO_MMC
  (make sure to control MFX0 & PG6)
  (see Power_Board page)
- Double footprint to be compatible with Macronix and Micron MT35XL512ABA1G12-0SIT
- PB2
- PG6
- (near U11) Macronix
- Close to Flash
- PF8
- PC5
- PF9
- (near SB21) (*)
- PF6
- PH3
- PC1
- (near SB21) PD6
- PF7
- (near SB21) PG14
- (near TP9) C5 for VPP from Micron
- LIMITATIONS (see MCU page) :
- SD CARD 2 (jumper)
- ( RESET pins of Flash have internal pull-up (both) by default
- and VPP connection is tbc on Micron )
- Micron : MT35XL512ABA1G12-0SIT
- (*) Make sure to set VDD_IO_MMC = 3.3V
- (*) Some OCSPI2 I/Os are supplied by VDD_IO_MMC
  (make sure to control MFX0 & PG6)
  (see Power_Board page)
- OCSPI2 (OPTIONAL)
- (*)
- PF0
- PF2
- PF1
- PG12
- PG0
- PF3
- PF4
- PF5
- PG15
- (near SB38) PG1
- (near SB38) PG10
- (near SB38) PG11
- (near SB38) (*)
- LIMITATIONS & BACK-UP (see MCU page):
- FMC (NOR, SRAM & SDRAM)

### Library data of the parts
C131 C132 C135 = MCD-00006: as C76 on sheet LCD
CN10 CN11 = MCD-00675: Socket High Speed, 10x2, 0.8mm, Center Strip Contacts, VR, SMT, Height 5.33 mm; Part_Type: Connector; Manufacturer: SAMTEC; Provided_By: SUBCO; ECCN_US: EAR99; ECCN_EU: NEC
HW29 = MCD-01033: MB1242 - ERM8 BGA24 Octal SPI module; Part_Type: Misc; Manufacturer: STMICROELECTRONICS; Provided_By: SUBCO with ST control
R94 R106 R111 R321 R355 = MCD-00053: as R395 on sheet JTAG&Trace
SB20 SB21 SB38-SB40 = MCD-00071: as SB43 on sheet JTAG&Trace
TP9 TP13-TP16 = MCD-00074: Test Point 1mm; Part_Type: Mechanical
U11 = MCD-00246: Memory,Octo-SPI-NOR,512Mb,2048x16,133MHz,3V,DTR,BGA24, CMOS MXSMIO; Part_Type: IC; Manufacturer: MACRONIX; Provided_By: SUBCO; ECCN_US: 3A991.b.1.a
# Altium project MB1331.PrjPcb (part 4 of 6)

## Sheet Peripherals.SchDoc: Peripherals
size A4; Date: Not used; ApprovedBy: Not used; CheckedBy: Not used; Author: Not used; CompanyName: STMicroelectronics; DrawnBy: Not used; Engineer: Not used; Organization: Not used; Address1: Not used; Address2: Not used; Address3: Not used; Address4: Not used; DocumentNumber: Not used; Revision: Not used; SheetNumber: 14; SheetTotal: 23

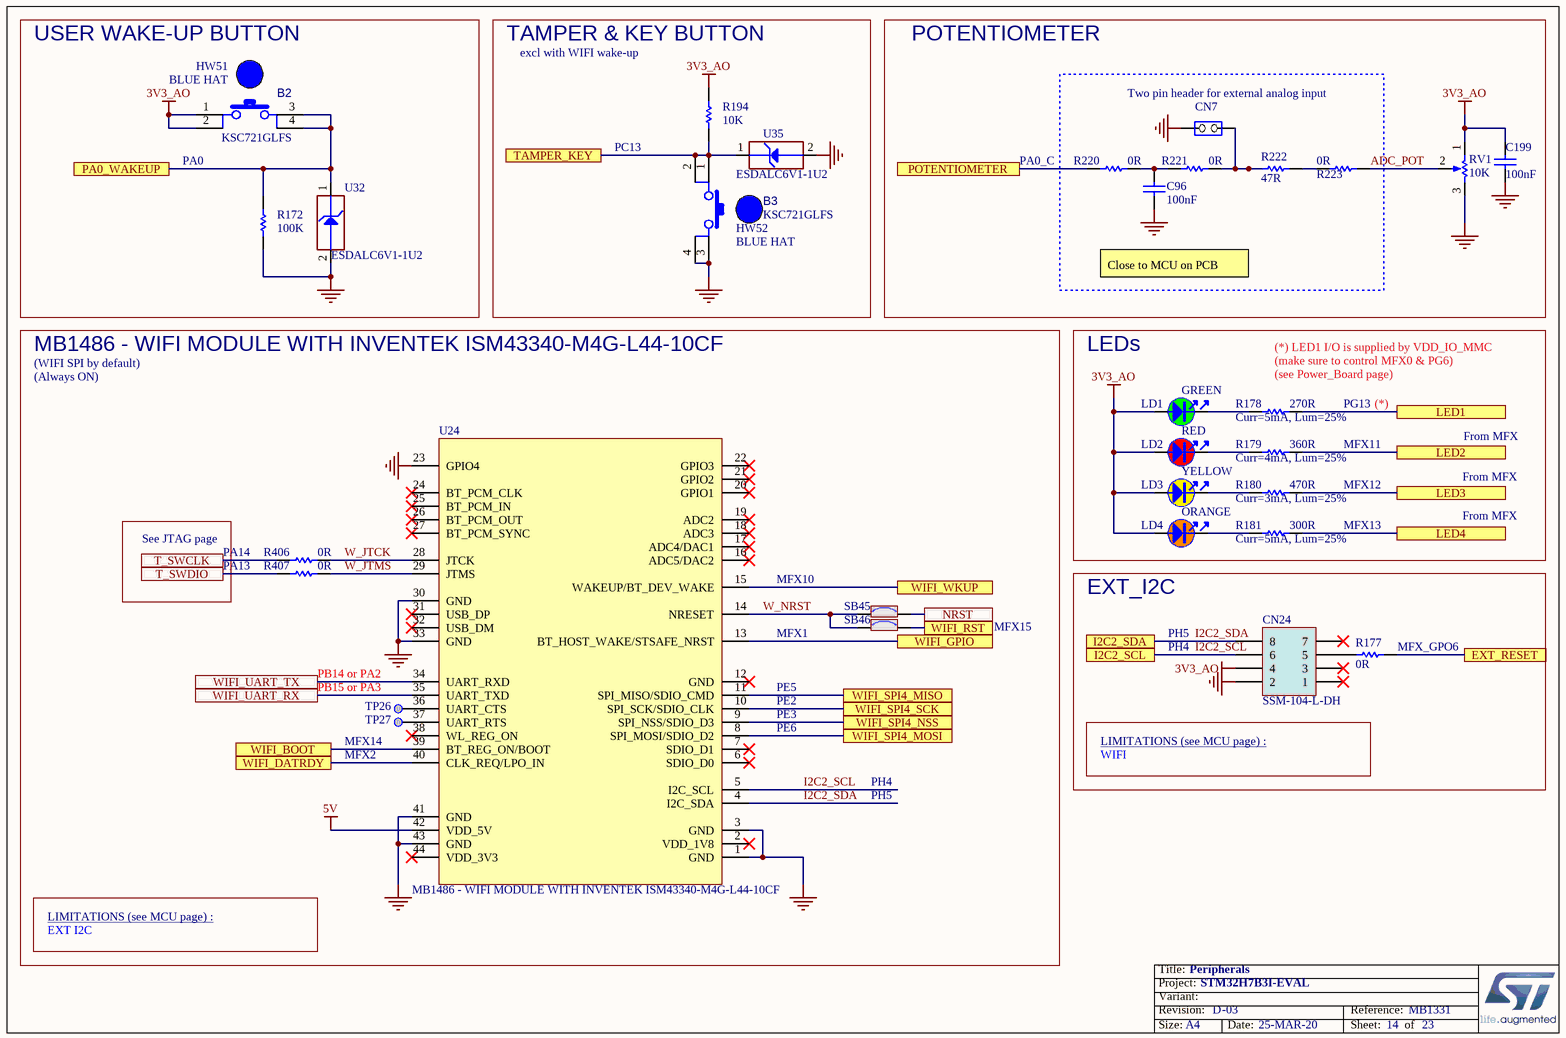
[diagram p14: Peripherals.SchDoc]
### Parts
B2  value KSC721GLFS  [SWI_C&K_KSC721GLFS_BLUE]  (hidden comment: SW_BLUE_KSC721GLFS)
B3  value KSC721GLFS  [SWI_C&K_KSC721GLFS_BLUE]  (hidden comment: SW_BLUE_KSC721GLFS)
C96  value 100nF  [C0603]  (hidden comment: Capacitor)
C199  value 100nF  [C0402]  (hidden comment: Capacitor)
CN7  Jumper_Header 2x1  [CON_SAMTEC_TSW-102-07-G-S]  (value not drawn)
CN24  value SSM-104-L-DH  [CON_SAMTEC_SSM-104-L-DH]  (hidden comment: Socket 4x2)
HW51  value BLUE HAT  (hidden comment: BUTTON_HAT_BLUE)  (mechanical)
HW52  value BLUE HAT  (hidden comment: BUTTON_HAT_BLUE)  (mechanical)
LD1  value GREEN  [LED_0603_OSRAM_LG-Q396-PS-35_GREEN_1A2K_H0P4]  (hidden comment: LED_green)
LD2  value RED  [LED_0603_VISHAY_VLMS1300-GS08_RED_1A2K_H0P8]  (hidden comment: LED_red)
LD3  value YELLOW  [LED_0603_OSRAM_LY-Q396-P1Q2-36_YELLOW_1A2K_H0P4]  (hidden comment: LED_yellow)
LD4  value ORANGE  [LED_0603_OSRAM_LO-Q976-PS-25_ORANGE_1A2K_H0P8]  (hidden comment: LED_orange)
R172  value 100K  [R0402]  (hidden comment: Resistor)
R177  value 0R  [R0402]  (hidden comment: Resistor)
R178  value 270R  [R0402]  (hidden comment: Resistor)
R179  value 360R  [R0402]  (hidden comment: Resistor)
R180  value 470R  [R0402]  (hidden comment: Resistor)
R181  value 300R  [R0402]  (hidden comment: Resistor)
R194  value 10K  [R0402]  (hidden comment: Resistor)
R220  value 0R  [R0603]  (hidden comment: Resistor)
R221  value 0R  [R0603]  (hidden comment: Resistor)
R222  value 47R  [R0603]  (hidden comment: Resistor)
R223  value 0R  [R0603]  (hidden comment: Resistor)
R406  value 0R  [R0402]  (hidden comment: Resistor)
R407  value 0R  [R0402]  (hidden comment: Resistor)
RV1  value 10K  [POT_BOURNS_3386P]  (hidden comment: POTENTIOMETER)
SB45  SB_ON  [SOLDER-BRIDGE_R0603-0R]  (value not drawn)
SB46  SB_ON  [SOLDER-BRIDGE_R0603-0R]  (value not drawn)
TP26  Test Point  [TP_SMD_1MM]  (value not drawn)  (no BOM)
TP27  Test Point  [TP_SMD_1MM]  (value not drawn)  (no BOM)
U24  value MB1486 - WIFI MODULE WITH INVENTEK ISM43340-M4G-L44-10CF  [MOD_WIFI_INVENTEK_ISM43362]  (hidden comment: WIFI MODULE INTERPOSER)
U32  value ESDALC6V1-1U2  [ESD_ST0201]  (hidden comment: ESD-TRANSIL)
U35  value ESDALC6V1-1U2  [ESD_ST0201]  (hidden comment: ESD-TRANSIL)

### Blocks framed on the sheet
USER WAKE-UP BUTTON: B2 HW51 R172 U32
TAMPER & KEY BUTTON: B3 HW52 R194 U35
POTENTIOMETER: C199 RV1
Two pin header for external analog input: C96 CN7 R220-R223
MB1486 - WIFI MODULE WITH INVENTEK ISM43340-M4G-L44-10CF: R406 R407 SB45 SB46 TP26 TP27 U24
LEDs: LD1-LD4 R178-R181
EXT_I2C: CN24 R177

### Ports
EXT_RESET, I2C2_SCL, I2C2_SDA, LED1, LED2, LED3, LED4, NRST, PA0_WAKEUP, POTENTIOMETER, T_SWCLK, T_SWDIO, TAMPER_KEY, WIFI_BOOT, WIFI_DATRDY, WIFI_GPIO, WIFI_RST, WIFI_SPI4_MISO, WIFI_SPI4_MOSI, WIFI_SPI4_NSS, WIFI_SPI4_SCK, WIFI_UART_RX, WIFI_UART_TX, WIFI_WKUP

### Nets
3V3_AO: B2.1 B2.2 C199.1 CN24.4 LD1.1 LD2.1 LD3.1 LD4.1 R194.2 RV1.1(BOT)
5V: U24.42(VDD_5V)
GND: B3.3 B3.4 C96.2 C199.2 CN7.2(NO) CN24.2 R172.1 RV1.3(TOP) U24.1(GND) U24.3(GND) U24.23(GPIO4) U24.30(GND) U24.33(GND) U24.41(GND) U24.43(GND) U32.2(GND) U35.2(GND)
ADC_POT: R223.2 RV1.2(TAP)
EXT_RESET: R177.2 ; port EXT_RESET
I2C2_SCL: CN24.6 U24.5(I2C_SCL) ; port I2C2_SCL
I2C2_SDA: CN24.8 U24.4(I2C_SDA) ; port I2C2_SDA
JTAG_TCK: R406.1 ; port T_SWCLK
JTAG_TMS: R407.1 ; port T_SWDIO
LED2: R179.2 ; port LED2
LED3: R180.2 ; port LED3
LED4: R181.2 ; port LED4
NRST: SB45.2 ; port NRST
PA0_WAKEUP: B2.3 B2.4 R172.2 U32.1(IO1) ; port PA0_WAKEUP
PG13: R178.2 ; port LED1
POTENTIOMETER: R220.2 ; port POTENTIOMETER
TAMPER_KEY: B3.1 B3.2 R194.1 U35.1(IO1) ; port TAMPER_KEY
W_JTCK: R406.2 U24.28(JTCK)
W_JTMS: R407.2 U24.29(JTMS)
W_NRST: SB45.1 SB46.1 U24.14(NRESET)
WIFI_BOOT: U24.39(BT_REG_ON/BOOT) ; port WIFI_BOOT
WIFI_DATRDY: U24.40(CLK_REQ/LPO_IN) ; port WIFI_DATRDY
WIFI_GPIO: U24.13(BT_HOST_WAKE/STSAFE_NRST) ; port WIFI_GPIO
WIFI_RST: SB46.2 ; port WIFI_RST
WIFI_SPI4_MISO: U24.11(SPI_MISO/SDIO_CMD) ; port WIFI_SPI4_MISO
WIFI_SPI4_MOSI: U24.8(SPI_MOSI/SDIO_D2) ; port WIFI_SPI4_MOSI
WIFI_SPI4_NSS: U24.9(SPI_NSS/SDIO_D3) ; port WIFI_SPI4_NSS
WIFI_SPI4_SCK: U24.10(SPI_SCK/SDIO_CLK) ; port WIFI_SPI4_SCK
WIFI_UART_RX: U24.35(UART_TXD) ; port WIFI_UART_RX
WIFI_UART_TX: U24.34(UART_RXD) ; port WIFI_UART_TX
WIFI_WKUP: U24.15(WAKEUP/BT_DEV_WAKE) ; port WIFI_WKUP
NetC96_1: C96.1 R220.1 R221.1
NetCN7_1: CN7.1(COMMON) R221.2 R222.1
NetCN24_5: CN24.5 R177.1
NetLD1_2: LD1.2 R178.1
NetLD2_2: LD2.2 R179.1
NetLD3_2: LD3.2 R180.1
NetLD4_2: LD4.2 R181.1
NetR222_2: R222.2 R223.1
NetTP26_1: TP26.1 U24.36(UART_CTS)
NetTP27_1: TP27.1 U24.37(UART_RTS)

Not connected (* = marked no-connect by the designer): CN24 1* 3* 7*; U24 2(VDD_1V8)* 6(SDIO_D0)* 7(SDIO_D1)* 12(GND)* 16(ADC5/DAC2)* 17(ADC4/DAC1)* 18(ADC3)* 19(ADC2)* 20(GPIO1)* 21(GPIO2)* 22(GPIO3)* 24(BT_PCM_CLK)* 25(BT_PCM_IN)* 26(BT_PCM_OUT)* 27(BT_PCM_SYNC)* 31(USB_DP)* 32(USB_DM)* 38(WL_REG_ON)* 44(VDD_3V3)*

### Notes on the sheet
- excl with WIFI wake-up
- (near B2) PA0
- PC13
- (near R220) PA0_C
- Close to MCU on PCB
- (WIFI SPI by default)
- (Always ON)
- (near R178) (*) LED1 I/O is supplied by VDD_IO_MMC
  (make sure to control MFX0 & PG6)
  (see Power_Board page)
- (near R178) Curr=5mA, Lum=25%
- PG13
- MFX11
- (*)
- From MFX
- (near R179) Curr=4mA, Lum=25%
- (near R180) Curr=3mA, Lum=25%
- MFX12
- See JTAG page
- PA13
- PA14
- MFX10
- (near R181) Curr=5mA, Lum=25%
- MFX13
- MFX1
- MFX15
- PH5
- PH4
- (near R177) MFX_GPO6
- PB14 or PA2
- PB15 or PA3
- PE5
- PE3
- PE2
- MFX14
- MFX2
- PE6
- LIMITATIONS (see MCU page) :
- WIFI
- EXT I2C

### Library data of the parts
B2 B3 = MCD-00176: Switch HW BLUE High4.3mm 2.25 Newtons; Manufacturer: C&K; Part_Type: Misc; Provided_By: SUBCO
C96 = MCD-00237: Capacitor, MLCC, 100nF, 6V3, X5R, 10%, 0603, T=0,8mm; Manufacturer_Part_Number: CC0603KRX5R5BB104; Manufacturer: YAGEO; Provided_By: SUBCO; ECCN_US: EAR99; ECCN_EU: NEC
C199 = MCD-00006: Capacitor, MLCC, 100nF, 16V, X7R, 10%, 0402, T=0.5mm; Manufacturer_Part_Number: CC0402KRX7R7BB104; Manufacturer: YAGEO; Alternate_Manufacturer_Part_Number: GCM155R71C104KA55D; Alternate_Manufacturer: MURATA; Provided_By: SUBCO; ECCN_US: EAR99; ECCN_EU: NEC
CN7 = MCD-00045: Header, 2x1, 2,54mm, VR, TH, Height 5.84mm/2.54mm; Manufacturer_Part_Number: TSW-102-07-x-S; Manufacturer: SAMTEC; Part_Type: Connector; Alternate_Manufacturer_Part_Number: 313102S111116;313102S111116; Alternate_Manufacturer: JIUBABA; LIANYI; Value: Shunt not fitted; Provided_By: SUBCO
CN24 = MCD-00131: Socket, 4x2, 2.54mm, RA, SMT, Height 5.72mm; Manufacturer: SAMTEC; Part_Type: Connector; Alternate_Manufacturer_Part_Number: F206A-2x04MGF-LA; Alternate_Manufacturer: JIUBABA; Provided_By: SUBCO; ECCN_US: EAR99; ECCN_EU: NEC
HW51 HW52 = MCD-00634: Blue Hat for switch TD0341X-G01-BLU; Part_Type: Mechanical; Manufacturer_Part_Number: 988.16.09.3.00002_SH-517; Manufacturer: JIUBABA; Provided_By: SUBCO
LD1 = MCD-00588: LED Green, 0603 SMD, Forward Voltage Typ=2V, Max=2.5V; Part_Type: Display; Manufacturer_Part_Number: LG Q396-PS-35; Manufacturer: OSRAM OPTO SEMICONDUCTORS; Alternate_Manufacturer_Part_Number: VLMTG1300-GS08; Alternate_Manufacturer: VISHAY SEMICONDUCTOR OPTO DIVISION; Provided_By: SUBCO
LD2 = MCD-00587: LED Red, 0603 SMD, 2V Forward Voltage; Part_Type: Display; Manufacturer_Part_Number: VLMS1300-GS08; Manufacturer: VISHAY; Alternate_Manufacturer_Part_Number: LS Q976-NR-1; Alternate_Manufacturer: OSRAM OPTO SEMICONDUCTORS; Provided_By: SUBCO
LD3 = MCD-01061: LED Yellow, 0603 SMD, Forward Voltage min=1.7V, Typ=2V, Max=2.3V; Part_Type: Display; Manufacturer_Part_Number: LY Q396-P1Q2-36; Manufacturer: OSRAM OPTO SEMICONDUCTORS; Provided_By: SUBCO
LD4 = MCD-00590: LED Orange, 0603 SMD, Forward Voltage Min=1.6V, Max=2.4V; Part_Type: Display; Manufacturer_Part_Number: LO Q976-PS-25; Manufacturer: OSRAM OPTO SEMICONDUCTORS; Alternate_Manufacturer_Part_Number: VLMO1300-GS08; Alternate_Manufacturer: VISHAY SEMICONDUCTOR OPTO DIVISION; Provided_By: SUBCO
R172 = MCD-00059: Resistor,100K,0402,1%,1/16W; Manufacturer_Part_Number: RC0402FR-07100KL; Manufacturer: YAGEO; Alternate_Manufacturer_Part_Number: RT0402FRE07100KL; Provided_By: SUBCO; ECCN_US: EAR99; ECCN_EU: NEC
R177 R406 R407 = MCD-00052: Resistor,0R,0402,5%,1/16W; Manufacturer_Part_Number: RC0402JR-070RL; Manufacturer: YAGEO; Provided_By: SUBCO; ECCN_US: EAR99; ECCN_EU: NEC
R178 = MCD-00441: Resistor,270R,0402,1%,1/16W; Manufacturer_Part_Number: RC0402FR-07270RL; Manufacturer: YAGEO; Provided_By: SUBCO; ECCN_US: EAR99; ECCN_EU: NEC
R179 = MCD-00461: Resistor,360R,0402,1%,1/16W; Manufacturer_Part_Number: RC0402FR-07360RL; Manufacturer: YAGEO; Provided_By: SUBCO; ECCN_US: EAR99; ECCN_EU: NEC
R180 = MCD-00178: Resistor,470R,0402,1%,1/16W; Manufacturer_Part_Number: RC0402FR-07470RL; Manufacturer: YAGEO; Provided_By: SUBCO; ECCN_US: EAR99; ECCN_EU: NEC
R181 = MCD-00449: Resistor,300R,0402,1%,1/16W; Manufacturer_Part_Number: RC0402FR-07300RL; Manufacturer: YAGEO; Provided_By: SUBCO; ECCN_US: EAR99; ECCN_EU: NEC
R194 = MCD-00053: Resistor,10K,0402,1%,1/16W; Manufacturer_Part_Number: RC0402FR-0710KL; Manufacturer: YAGEO; Provided_By: SUBCO; ECCN_US: EAR99; ECCN_EU: NEC
R220 R221 R223 = MCD-00056: Resistor,0R,0603,5%,1/10W; Manufacturer_Part_Number: RC0603JR-070RL; Manufacturer: YAGEO; Provided_By: SUBCO; ECCN_US: EAR99; ECCN_EU: NEC
R222 = MCD-00482: Resistor,47R,0603,1%,1/10W; Manufacturer_Part_Number: RC0603FR-0747RL; Manufacturer: YAGEO; Provided_By: SUBCO; ECCN_US: EAR99; ECCN_EU: NEC
RV1 = MCD-00575: TRIMMER 10K OHM 0.5W PC PIN; Part_Type: Resistor; Manufacturer_Part_Number: 3386P-1-103; Manufacturer: BOURNS; Provided_By: SUBCO; ECCN_US: EAR99; ECCN_EU: NEC
SB45 SB46 = MCD-00071: Solder Bridge ON; Part_Type: Mechanical; Manufacturer_Part_Number: RC0603JR-070RL; Manufacturer: YAGEO; Provided_By: SUBCO
TP26 TP27 = MCD-00074: Test Point 1mm; Part_Type: Mechanical
U24 = MCD-01999: 44 pins Interposer for WIFI module (MB1486 module is with INVENTEK ISM43340-M4G-L44-10CF); Part_Type: Misc; Manufacturer: STMICROELECTRONICS; ECCN_US: 5A002A4; Provided_By: SUBCO with ST control
U32 U35 = MCD-00170: ESD protection 6V1; Part_Type: Diode; Manufacturer: STMICROELECTRONICS; BMS_Part_Number: 9151132; Provided_By: SUBCO with ST control; ECCN_US: EAR99; ECCN_EU: NEC

## Sheet Power_Board.SchDoc: Board Power
size A4; Date: Not used; ApprovedBy: Not used; CheckedBy: Not used; Author: Not used; CompanyName: STMicroelectronics; DrawnBy: Not used; Engineer: Not used; Organization: Not used; Address1: Not used; Address2: Not used; Address3: Not used; Address4: Not used; DocumentNumber: Not used; Revision: Not used; SheetNumber: 20; SheetTotal: 23

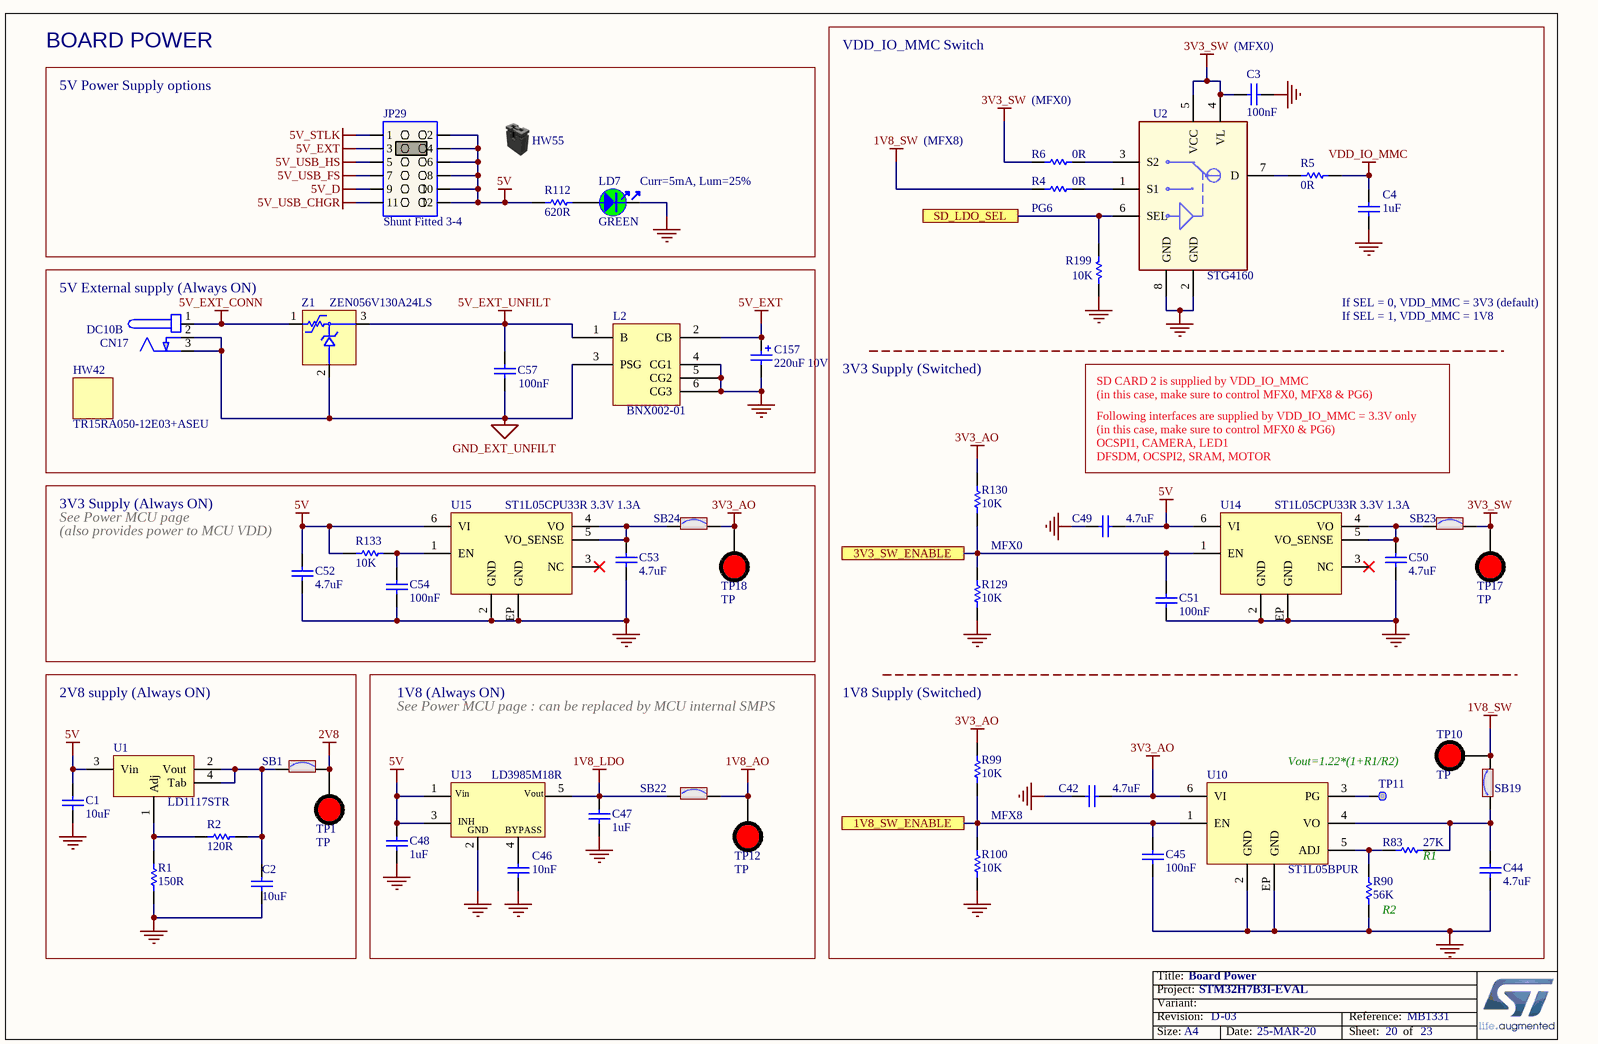
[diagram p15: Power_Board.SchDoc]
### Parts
C1  value 10uF  [C0603]  (hidden comment: Capacitor)
C2  value 10uF  [C0603]  (hidden comment: Capacitor)
C3  value 100nF  [C0402]  (hidden comment: Capacitor)
C4  value 1uF  [C0603]  (hidden comment: Capacitor)
C42  value 4.7uF  [C0603]  (hidden comment: Capacitor)
C44  value 4.7uF  [C0603]  (hidden comment: Capacitor)
C45  value 100nF  [C0402]  (hidden comment: Capacitor)
C46  value 10nF  [C0402]  (hidden comment: Capacitor)
C47  value 1uF  [C0402]  (hidden comment: Capacitor)
C48  value 1uF  [C0402]  (hidden comment: Capacitor)
C49  value 4.7uF  [C0603]  (hidden comment: Capacitor)
C50  value 4.7uF  [C0603]  (hidden comment: Capacitor)
C51  value 100nF  [C0402]  (hidden comment: Capacitor)
C52  value 4.7uF  [C0603]  (hidden comment: Capacitor)
C53  value 4.7uF  [C0603]  (hidden comment: Capacitor)
C54  value 100nF  [C0402]  (hidden comment: Capacitor)
C57  value 100nF  [C0402]  (hidden comment: Capacitor)
C157  value 220uF 10V  [CPOL_TAJ-C_2312_H2P6]  (hidden comment: Cap_POL_TANA)
CN17  value DC10B  [CON_DC-POWER-SOCKET_CLIFF_FC68149_DC10B]  (hidden comment: Power_Jack_DC10B)
HW42  value TR15RA050-12E03+ASEU  (hidden comment: Hardware)  (mechanical)
HW55  Shunt Black 2.54mm  (value not drawn)  (mechanical)
JP29  value Shunt Fitted 3-4  [CON_SAMTEC_TSW-106-07-X-D]  (hidden comment: Jumper_Header 6x2 Fitted 3-4)
L2  BNX002-01  [FIL_MURATA_BNX002-01]
LD7  value GREEN  [LED_0603_OSRAM_LG-Q396-PS-35_GREEN_1A2K_H0P4]  (hidden comment: LED_green)
R1  value 150R  [R0603]  (hidden comment: Resistor)
R2  value 120R  [R0603]  (hidden comment: Resistor)
R4  value 0R  [R0603]  (hidden comment: Resistor)
R5  value 0R  [R0603]  (hidden comment: Resistor)
R6  value 0R  [R0603]  (hidden comment: Resistor)
R83  value 27K  [R0402]  (hidden comment: Resistor)
R90  value 56K  [R0402]  (hidden comment: Resistor)
R99  value 10K  [R0402]  (hidden comment: Resistor)
R100  value 10K  [R0402]  (hidden comment: Resistor)
R112  value 620R  [R0402]  (hidden comment: Resistor)
R129  value 10K  [R0402]  (hidden comment: Resistor)
R130  value 10K  [R0402]  (hidden comment: Resistor)
R133  value 10K  [R0402]  (hidden comment: Resistor)
R199  value 10K  [R0402]  (hidden comment: Resistor)
SB1  SB_ON  [SOLDER-BRIDGE_R0603-0R]  (value not drawn)
SB19  SB_ON  [SOLDER-BRIDGE_R0603-0R]  (value not drawn)
SB22  SB_ON  [SOLDER-BRIDGE_R0603-0R]  (value not drawn)
SB23  SB_ON  [SOLDER-BRIDGE_R0603-0R]  (value not drawn)
SB24  SB_ON  [SOLDER-BRIDGE_R0603-0R]  (value not drawn)
TP1  value TP  [TP_PTH-1MM_TEST-TERMINAL_RS_262-2185_RED]  (hidden comment: Test_pin_conn_red)
TP10  value TP  [TP_PTH-1MM_TEST-TERMINAL_RS_262-2185_RED]  (hidden comment: Test_pin_conn_red)
TP11  Test Point  [TP_SMD_1MM]  (value not drawn)  (no BOM)
TP12  value TP  [TP_PTH-1MM_TEST-TERMINAL_RS_262-2185_RED]  (hidden comment: Test_pin_conn_red)
TP17  value TP  [TP_PTH-1MM_TEST-TERMINAL_RS_262-2185_RED]  (hidden comment: Test_pin_conn_red)
TP18  value TP  [TP_PTH-1MM_TEST-TERMINAL_RS_262-2185_RED]  (hidden comment: Test_pin_conn_red)
U1  LD1117STR  [REG_SOT223-TAB]
U2  STG4160  [ESD_FLIP-CHIP-BGA8_1P9X0P9_P050]
U10  ST1L05BPUR  [ICC_DFN6-EPAD_3X3_P095]
U13  LD3985M18R  [REG_SOT23-5L]
U14  value ST1L05CPU33R 3.3V 1.3A  [ICC_DFN6-EPAD_3X3_P095]  (hidden comment: ST1L05CPU33R)
U15  value ST1L05CPU33R 3.3V 1.3A  [ICC_DFN6-EPAD_3X3_P095]  (hidden comment: ST1L05CPU33R)
Z1  ZEN056V130A24LS  [DIOZ_LITTELFUSE_ZEN056V130A24LS]

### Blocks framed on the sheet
BOARD POWER: HW55 JP29 LD7 R112
5V External supply (Always ON): C57 C157 CN17 HW42 L2 Z1
2V8 supply (Always ON): C1 C2 R1 R2 SB1 TP1 U1

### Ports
1V8_SW_ENABLE, 3V3_SW_ENABLE, SD_LDO_SEL

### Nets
1V8_AO: SB22.2 TP12.1
1V8_LDO: C47.2 SB22.1 U13.5(Vout)
1V8_SW: R4.1 SB19.2 TP10.1
2V8: SB1.2 TP1.1
3V3_AO: C42.1 R99.1 R130.1 SB24.2 TP18.1 U10.6(VI)
3V3_SW: C3.1 R6.1 SB23.2 TP17.1 U2.4(VL) U2.5(VCC)
5V: C1.2 C48.2 C49.1 C52.2 JP29.2 JP29.4 JP29.6 JP29.8 JP29.10 JP29.12 R112.1 R133.2 U1.3(Vin) U13.1(Vin) U13.3(CE) U14.6(VI) U15.6(VI)
5V_D: JP29.9
5V_EXT: C157.1 JP29.3 L2.2(CB)
5V_EXT_CONN: CN17.1 Z1.1
5V_EXT_UNFILT: C57.1 L2.1(B) Z1.3
5V_STLK: JP29.1
5V_USB_CHGR: JP29.11
5V_USB_FS: JP29.7
5V_USB_HS: JP29.5
GND: C1.1 C2.1 C3.2 C4.1 C42.2 C44.1 C45.2 C46.1 C47.1 C48.1 C49.2 C50.1 C51.2 C52.1 C53.1 C54.2 C157.2 L2.4(CG1) L2.5(CG2) L2.6(CG3) LD7.2 R1.1 R90.1 R100.2 R129.2 R199.1 U2.2(GND) U2.8(GND) U10.2(GND) U10.EP(GND) U13.2(GND) U14.2(GND) U14.EP(GND) U15.2(GND) U15.EP(GND)
GND_EXT_UNFILT: C57.2 CN17.2 CN17.3 L2.3(PSG) Z1.2
VDD_IO_MMC: C4.2 R5.2
1V8_SW_ENABLE: C45.1 R99.2 R100.1 U10.1(EN) ; port 1V8_SW_ENABLE
3V3_SW_ENABLE: C51.1 R129.1 R130.2 U14.1(EN) ; port 3V3_SW_ENABLE
SD_LDO_SEL: R199.2 U2.6(SEL) ; port SD_LDO_SEL
NetC2_2: C2.2 R2.1 SB1.1 U1.2(Vout) U1.4(Tab)
NetC44_2: C44.2 R83.1 SB19.1 U10.4(VO)
NetC46_2: C46.2 U13.4(BYPASS)
NetC50_2: C50.2 SB23.1 U14.4(VO) U14.5(VO_SENSE)
NetC53_2: C53.2 SB24.1 U15.4(VO) U15.5(VO_SENSE)
NetC54_1: C54.1 R133.1 U15.1(EN)
NetLD7_1: LD7.1 R112.2
NetR1_2: R1.2 R2.2 U1.1(Adj)
NetR4_2: R4.2 U2.1(S1)
NetR5_1: R5.1 U2.7(D)
NetR6_2: R6.2 U2.3(S2)
NetR83_2: R83.2 R90.2 U10.5(ADJ)
NetTP11_1: TP11.1 U10.3(PG)

Not connected (* = marked no-connect by the designer): U14 3(NC)*; U15 3(NC)*

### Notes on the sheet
- VDD_IO_MMC Switch
- (near C3) (MFX0)
- 5V Power Supply options
- (MFX0)
- (near LD7) Curr=5mA, Lum=25%
- (MFX8)
- (near R4) PG6
- If SEL = 0, VDD_MMC = 3V3 (default)
- If SEL = 1, VDD_MMC = 1V8
- 3V3 Supply (Switched)
- SD CARD 2 is supplied by VDD_IO_MMC
  (in this case, make sure to control MFX0, MFX8 & PG6)
- 3V3 Supply (Always ON)
- See Power MCU page
- Following interfaces are supplied by VDD_IO_MMC = 3.3V only
  (in this case, make sure to control MFX0 & PG6)
  OCSPI1, CAMERA, LED1
  DFSDM, OCSPI2, SRAM, MOTOR
- (near C52) (also provides power to MCU VDD)
- MFX0
- 1V8 (Always ON)
- See Power MCU page : can be replaced by MCU internal SMPS
- 1V8 Supply (Switched)
- Vout=1.22*(1+R1/R2)
- MFX8
- (near R83) R1
- (near R90) R2

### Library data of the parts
C1 C2 = MCD-00243: Capacitor, MLCC, 10uF, 6V3, X5R, 10%, 0603, T=0,8mm; Manufacturer_Part_Number: CC0603KRX5R5BB106; Manufacturer: YAGEO; Provided_By: SUBCO; ECCN_US: EAR99; ECCN_EU: NEC
C3 C45 C51 C54 C57 = MCD-00006: as C199 on sheet Peripherals
C4 = MCD-00010: Capacitor, MLCC, 1uF, 16V, X5R, 10%, 0603, T=0,8mm; Manufacturer_Part_Number: CC0603KRX5R7BB105; Manufacturer: YAGEO; Provided_By: SUBCO; ECCN_US: EAR99; ECCN_EU: NEC
C42 C44 C50 C53 = MCD-01121: Capacitor, MLCC, 4.7uF, 10V, X5R, 20%, 0603, T=0,8mm; Manufacturer_Part_Number: GRM188R61A475ME15; Manufacturer: MURATA; Provided_By: SUBCO; ECCN_US: EAR99; ECCN_EU: NEC
C46 = MCD-00011: Capacitor, MLCC, 10nF, 16V, X7R, 10%, 0402, T=0.5mm; Manufacturer_Part_Number: CC0402KRX7R7BB103; Manufacturer: YAGEO; Provided_By: SUBCO; ECCN_US: EAR99; ECCN_EU: NEC
C47 C48 = MCD-00095: Capacitor, MLCC, 1uF, 6V3, X5R, 10%, 0402, T=0,5mm; Manufacturer_Part_Number: GRM155R61E105KA12; Manufacturer: MURATA; Alternate_Manufacturer_Part_Number: GRM155R60J105KE19; Provided_By: SUBCO; ECCN_US: EAR99; ECCN_EU: NEC
C49 C52 = MCD-00097: Capacitor, MLCC, 4.7uF, 16V, X5R, 20%, 0603, T=0,8mm; Manufacturer_Part_Number: GRM188R61C475KE11; Manufacturer: MURATA; Alternate_Manufacturer_Part_Number: GRM188R61C475MAAJ; Provided_By: SUBCO; ECCN_US: EAR99; ECCN_EU: NEC
C157 = MCD-00142: Capacitor, Tantalum, 220uF, 10V, 10%, 500mOhms, pkg Type_C (6032 metric), T=2.6mm; Manufacturer_Part_Number: TAJC227K010R; Manufacturer: AVX; Provided_By: SUBCO; ECCN_US: EAR99; ECCN_EU: NEC
CN17 = MCD-00173: DC-Power-Jack, 2.5mm, 5A, RA, TH; Manufacturer: CLIFF; Part_Type: Connector; BMS_Part_Number: 9087803; Provided_By: SUBCO
HW42 = MCD-01420: External CA Wall power supply 5V 2A Switching Adapter, Level VI, Wallmount, 15W, 90-264VAC Input, 5VDC Output, 5.5x2.5x12mm Straight, Grey Case, DC Cable 1800mm; Part_Type: Mechanical; Manufacturer: CINCON; BMS_Part_Number: 9027030; Provided_By: ST
HW55 = MCD-00043: SHUNT 2.54mm BLACK; Part_Type: Mechanical; Manufacturer: SAMTEC; Alternate_Manufacturer_Part_Number: 316102S111A; Alternate_Manufacturer: JIUBABA; Value: SNT-100-BK-G; Provided_By: SUBCO
JP29 = MCD-01147: Header, 6x2, 2,54mm, VR, TH, Height 5.84mm/2.54mm - Shunt Fitted 1-2; Part_Type: Connector; Manufacturer_Part_Number: TSW-106-07-x-D; Manufacturer: SAMTEC; Provided_By: SUBCO
L2 = MCD-00150: Through HOLE DC power EMI line filter, 40dB min (1MHz - 1GHz) insertion loss; Manufacturer: MURATA; Part_Type: Inductor; BMS_Part_Number: 9049203; Provided_By: SUBCO; ECCN_US: EAR99; ECCN_EU: NEC
LD7 = MCD-00588: as LD1 on sheet Peripherals
R1 = MCD-00394: Resistor,150,0603,1%,1/10W; Manufacturer_Part_Number: RC0603FR-07150RL; Manufacturer: YAGEO; Provided_By: SUBCO; ECCN_US: EAR99; ECCN_EU: NEC
R2 = MCD-00338: Resistor,120R,0603,1%,1/10W; Manufacturer_Part_Number: RC0603FR-07120RL; Manufacturer: YAGEO; BMS_Part_Number: 9129734; Provided_By: SUBCO; ECCN_US: EAR99; ECCN_EU: NEC
R4-R6 = MCD-00056: as R220 on sheet Peripherals
R83 = MCD-00443: Resistor,27K,0402,1%,1/16W; Manufacturer_Part_Number: RC0402FR-0727KL; Manufacturer: YAGEO; Provided_By: SUBCO; ECCN_US: EAR99; ECCN_EU: NEC
R90 = MCD-00493: Resistor,56K,0402,1%,1/16W; Manufacturer_Part_Number: RC0402FR-0756KL; Manufacturer: YAGEO; Provided_By: SUBCO; ECCN_US: EAR99; ECCN_EU: NEC
R99 R100 R129 R130 R133 R199 = MCD-00053: as R194 on sheet Peripherals
R112 = MCD-00499: Resistor,620R,0402,1%,1/16W; Manufacturer_Part_Number: RC0402FR-07620RL; Manufacturer: YAGEO; Provided_By: SUBCO; ECCN_US: EAR99; ECCN_EU: NEC
SB1 SB19 SB22-SB24 = MCD-00071: as SB45 on sheet Peripherals
TP1 TP10 TP12 TP17 TP18 = MCD-00712: RS Pro 1mm Red Test Terminal; Part_Type: Mechanical; Manufacturer_Part_Number: 262-2185; Provided_By: SUBCO
TP11 = MCD-00074: Test Point 1mm; Part_Type: Mechanical
U1 = MCD-00721: LDO Voltage Regulator, Adjustable, 15V in, 1.1V drop, 1.25V to 15V/0.8A out, SOT-223-3; Part_Type: IC; Manufacturer: STMICROELECTRONICS; BMS_Part_Number: 9176132; Provided_By: SUBCO with ST control; ECCN_US: EAR99; ECCN_EU: NEC
U2 = MCD-00668: Low voltage 0.5 ohm single SPDT switch with break-before-make feature and 15 kV contact ESD protection; Manufacturer_Part_Number: STG4160BJR; Manufacturer: STMICROELECTRONICS; Part_Type: IC; Provided_By: SUBCO with ST control; ECCN_US: EAR99; ECCN_EU: NEC
U10 = MCD-00581: LDO Linear Voltage Regulator IC Positive Adjustable 1 Output Adjustable 1.3A 6-DFN (3x3); Manufacturer: STMICROELECTRONICS; BMS_Part_Number: 9176239; Provided_By: SUBCO with ST control; ECCN_US: EAR99; ECCN_EU: NEC
U13 = MCD-00078: Ultra low drop-low noise BiCMOS voltage, regulators low ESR capacitors compatible; Manufacturer: STMICROELECTRONICS; Part_Type: IC; BMS_Part_Number: 9176159; Provided_By: SUBCO with ST control; ECCN_US: EAR99; ECCN_EU: NEC
U14 U15 = MCD-01025: LDO, 3.3V, 1.3A, Very low quiescent current BiCMOS voltage regulator; Part_Type: IC; Manufacturer: STMICROELECTRONICS; BMS_Part_Number: 9176246; Provided_By: SUBCO with ST control; ECCN_US: EAR99; ECCN_EU: NEC
Z1 = MCD-00149: Protection circuit Zener Diode; Manufacturer: LITTLEFUSE; BMS_Part_Number: 9127091; Provided_By: SUBCO; ECCN_US: EAR99; ECCN_EU: NEC

## Sheet STLink_V3E_SWD.SchDoc: ST-LINK V3 SWD Module
size A3; Date: Not used; ApprovedBy: Not used; CheckedBy: Not used; Author: Not used; CompanyName: STMicroelectronics; DrawnBy: Not used; Engineer: Not used; Organization: Not used; Address1: Not used; Address2: Not used; Address3: Not used; Address4: Not used; DocumentNumber: Not used; Revision: Not used; SheetNumber: 23; SheetTotal: 23

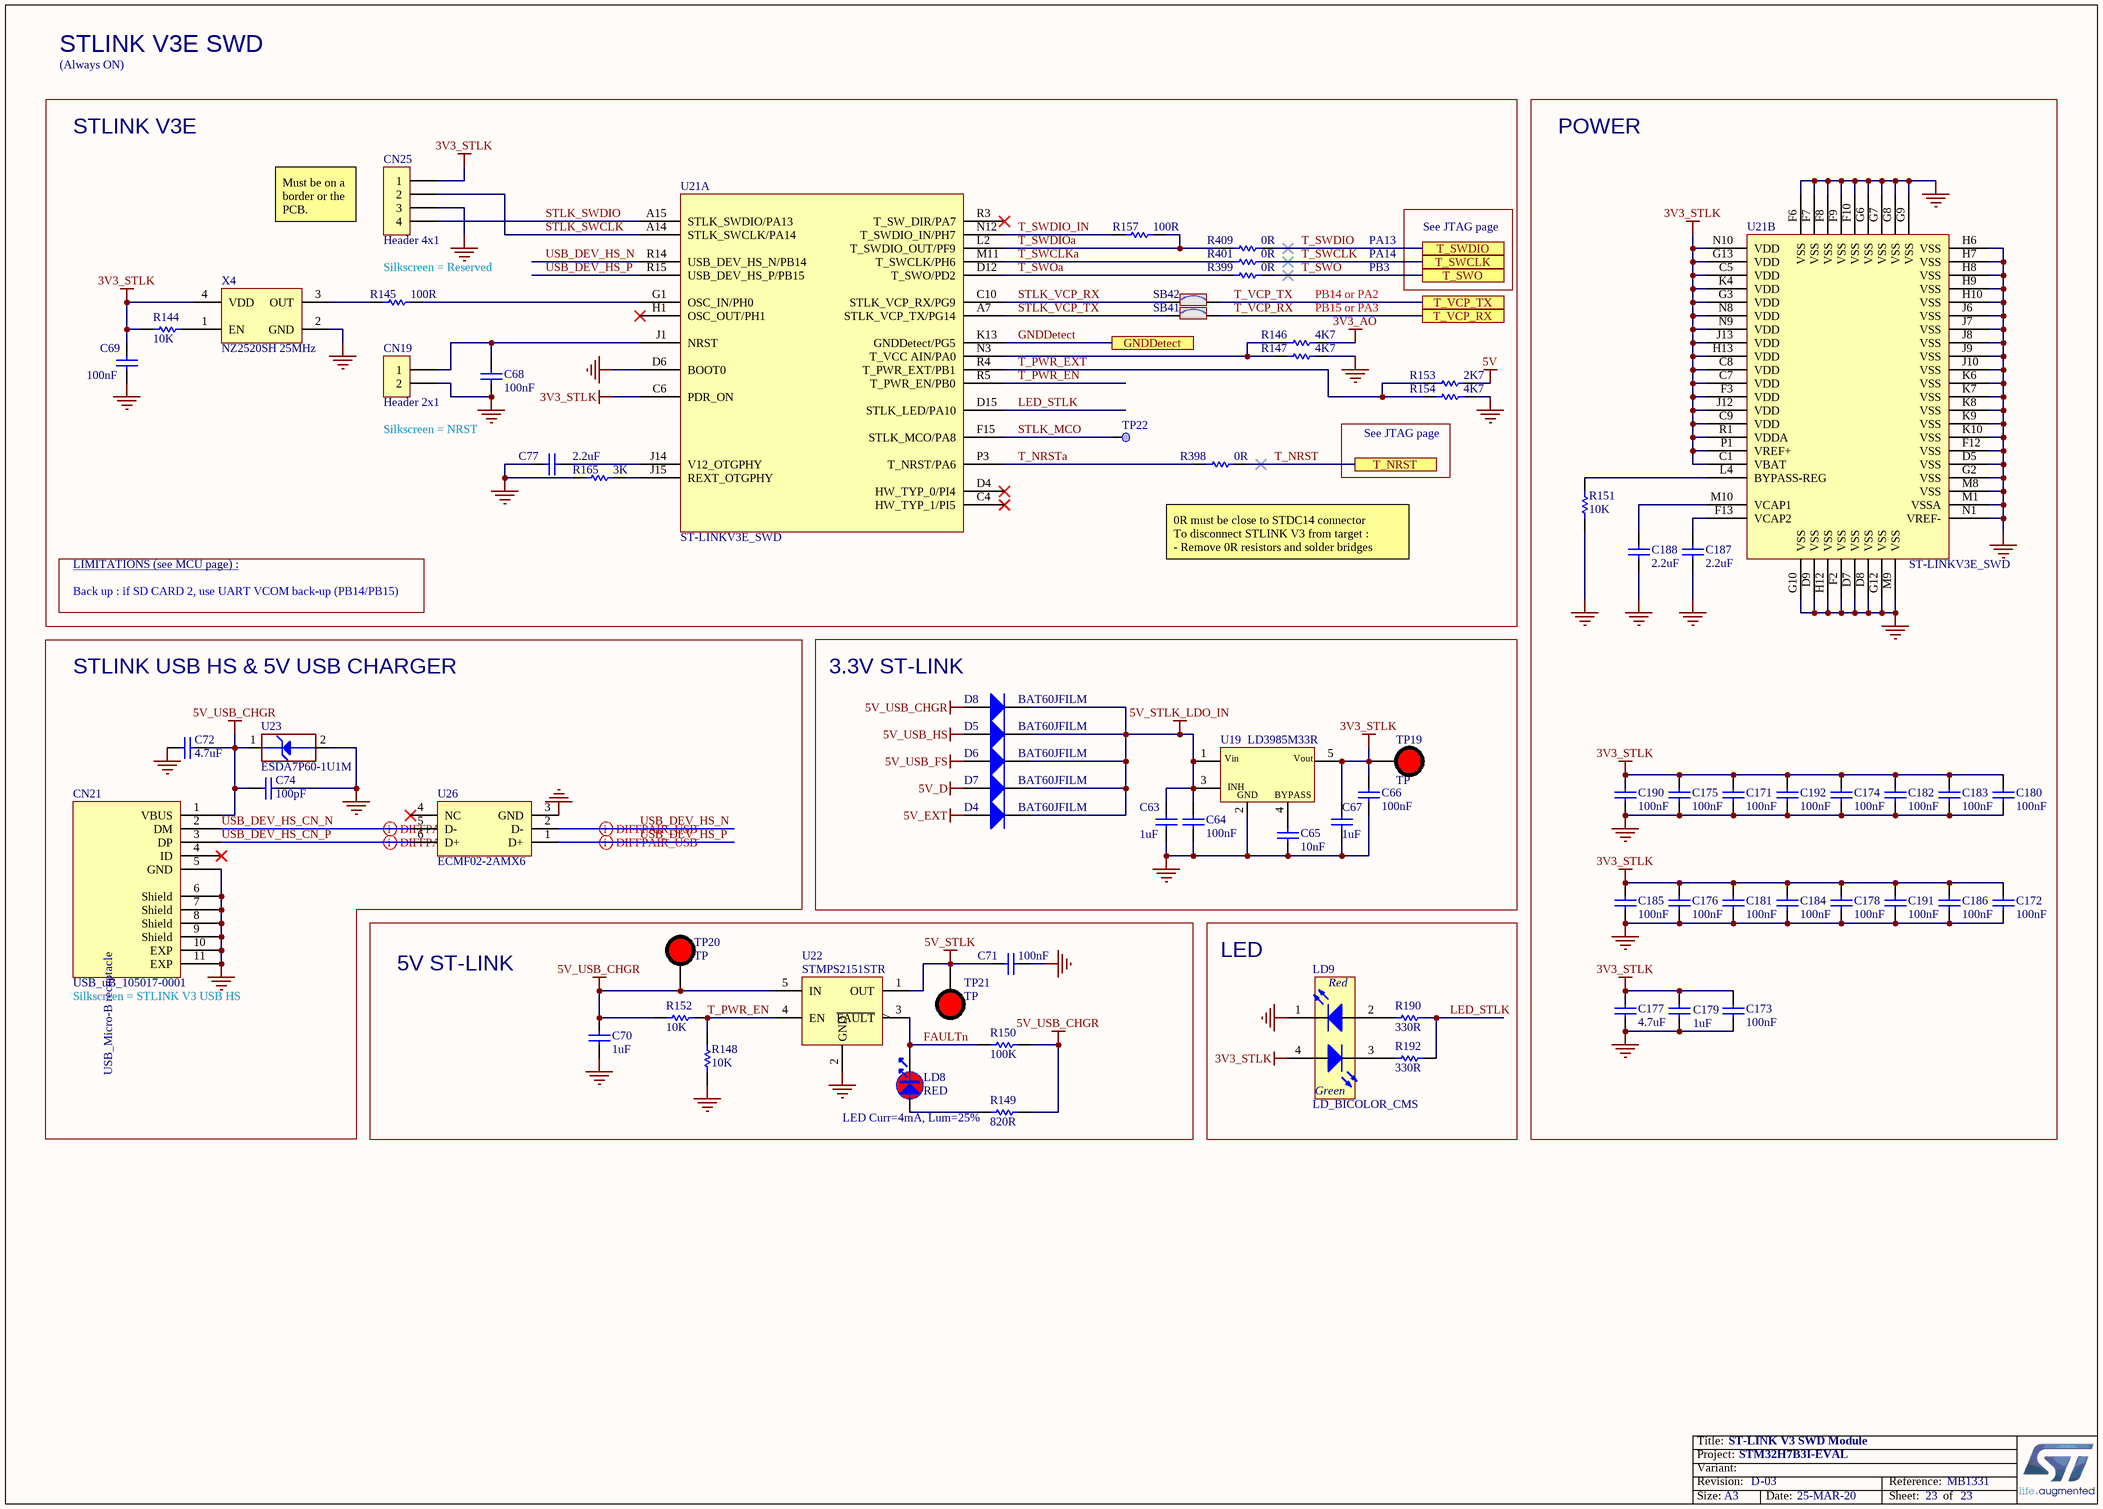
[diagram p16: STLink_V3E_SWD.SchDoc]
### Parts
C63  value 1uF  [C0603]  (hidden comment: Capacitor)
C64  value 100nF  [C0402]  (hidden comment: Capacitor)
C65  value 10nF  [C0402]  (hidden comment: Capacitor)
C66  value 100nF  [C0603]  (hidden comment: Capacitor)
C67  value 1uF  [C0603]  (hidden comment: Capacitor)
C68  value 100nF  [C0402]  (hidden comment: Capacitor)
C69  value 100nF  [C0402]  (hidden comment: Capacitor)
C70  value 1uF  [C0603]  (hidden comment: Capacitor)
C71  value 100nF  [C0402]  (hidden comment: Capacitor)
C72  value 4.7uF  [C0603]  (hidden comment: Capacitor)
C74  value 100pF  [C0402]  (hidden comment: Capacitor)
C77  value 2.2uF  [C0603]  (hidden comment: Capacitor)
C171  value 100nF  [C0402]  (hidden comment: Capacitor)
C172  value 100nF  [C0402]  (hidden comment: Capacitor)
C173  value 100nF  [C0402]  (hidden comment: Capacitor)
C174  value 100nF  [C0402]  (hidden comment: Capacitor)
C175  value 100nF  [C0402]  (hidden comment: Capacitor)
C176  value 100nF  [C0402]  (hidden comment: Capacitor)
C177  value 4.7uF  [C0603]  (hidden comment: Capacitor)
C178  value 100nF  [C0402]  (hidden comment: Capacitor)
C179  value 1uF  [C0603]  (hidden comment: Capacitor)
C180  value 100nF  [C0402]  (hidden comment: Capacitor)
C181  value 100nF  [C0402]  (hidden comment: Capacitor)
C182  value 100nF  [C0402]  (hidden comment: Capacitor)
C183  value 100nF  [C0402]  (hidden comment: Capacitor)
C184  value 100nF  [C0402]  (hidden comment: Capacitor)
C185  value 100nF  [C0402]  (hidden comment: Capacitor)
C186  value 100nF  [C0402]  (hidden comment: Capacitor)
C187  value 2.2uF  [C0603]  (hidden comment: Capacitor)
C188  value 2.2uF  [C0603]  (hidden comment: Capacitor)
C190  value 100nF  [C0402]  (hidden comment: Capacitor)
C191  value 100nF  [C0402]  (hidden comment: Capacitor)
C192  value 100nF  [C0402]  (hidden comment: Capacitor)
CN19  Header 2x1  [CON_SAMTEC_TSW-102-07-G-S]
CN21  value USB_uB_105017-0001  [CON_USBMICROB_MOLEX_105017-0001_H2P90]  (hidden comment: USB_uB_105017.0001)
CN25  Header 4x1  [CON_SAMTEC_TSW-104-07-G-S]
D4  BAT60JFILM  [DIO_SOD323]
D5  BAT60JFILM  [DIO_SOD323]
D6  BAT60JFILM  [DIO_SOD323]
D7  BAT60JFILM  [DIO_SOD323]
D8  BAT60JFILM  [DIO_SOD323]
LD8  value RED  [LED_0603_VISHAY_VLMS1300-GS08_RED_1A2K_H0P8]  (hidden comment: LED_red)
LD9  LD_BICOLOR_CMS  [LED_BI-GR_HSMF-A201-A00J1]
R144  value 10K  [R0402]  (hidden comment: Resistor)
R145  value 100R  [R0402]  (hidden comment: Resistor)
R146  value 4K7  [R0402]  (hidden comment: Resistor)
R147  value 4K7  [R0402]  (hidden comment: Resistor)
R148  value 10K  [R0402]  (hidden comment: Resistor)
R149  value 820R  [R0402]  (hidden comment: Resistor)
R150  value 100K  [R0402]  (hidden comment: Resistor)
R151  value 10K  [R0402]  (hidden comment: Resistor)
R152  value 10K  [R0402]  (hidden comment: Resistor)
R153  value 2K7  [R0402]  (hidden comment: Resistor)
R154  value 4K7  [R0402]  (hidden comment: Resistor)
R157  value 100R  [R0402]  (hidden comment: Resistor)
R165  value 3K  [R0402]  (hidden comment: Resistor)
R190  value 330R  [R0603]  (hidden comment: Resistor)
R192  value 330R  [R0603]  (hidden comment: Resistor)
R398  value 0R  [R0402]  (hidden comment: Resistor)
R399  value 0R  [R0402]  (hidden comment: Resistor)
R401  value 0R  [R0402]  (hidden comment: Resistor)
R409  value 0R  [R0402]  (hidden comment: Resistor)
SB41  SB_ON  [SOLDER-BRIDGE_R0402-0R]  (value not drawn)
SB42  SB_ON  [SOLDER-BRIDGE_R0402-0R]  (value not drawn)
TP19  value TP  [TP_PTH-1MM_TEST-TERMINAL_RS_262-2185_RED]  (hidden comment: Test_pin_conn_red)
TP20  value TP  [TP_PTH-1MM_TEST-TERMINAL_RS_262-2185_RED]  (hidden comment: Test_pin_conn_red)
TP21  value TP  [TP_PTH-1MM_TEST-TERMINAL_RS_262-2185_RED]  (hidden comment: Test_pin_conn_red)
TP22  Test Point  [TP_SMD_1MM]  (value not drawn)  (no BOM)
U19  LD3985M33R  [REG_SOT23-5L]
U21  ST-LINKV3E_SWD  [ICC_UFBGA201_176+25_10X10_P065]  (parts A,B of 2)
U22  STMPS2151STR  [MOS_SOT23-5L]
U23  value ESDA7P60-1U1M  [ESD_QFN2_1P6X1_P125]  (hidden comment: ESD-TRANSIL)
U26  ECMF02-2AMX6  [ESD_QFN-6L_1P7X1P5_P050]
X4  value NZ2520SH 25MHz  [OSC_NDK_NZ2520SB_4P]  (hidden comment: OSCILLATOR_4_PINS)

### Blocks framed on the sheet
STLINK V3E: C68 C69 C77 CN19 CN25 R144-R147 R153 R154 R157 R165 R398 R399 R401 R409 SB41 SB42 TP22 U21 X4
POWER: C171-C188 C190-C192 R151 U21
STLINK USB HS & 5V USB CHARGER: C72 C74 CN21 U23 U26
3.3V ST-LINK: C63-C67 D4-D8 TP19 U19
5V ST-LINK: C70 C71 LD8 R148-R150 R152 TP20 TP21 U22
LED: LD9 R190 R192

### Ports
GNDDetect, T_NRST, T_SWCLK, T_SWDIO, T_SWO, T_VCP_RX, T_VCP_TX

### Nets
3V3_AO: R146.2
3V3_STLK: C66.2 C67.2 C69.2 C171.2 C172.2 C173.2 C174.2 C175.2 C176.2 C177.2 C178.2 C179.2 C180.2 C181.2 C182.2 C183.2 C184.2 C185.2 C186.2 C190.2 C191.2 C192.2 CN25.1 LD9.4(YellowGreen_anode) R144.1 TP19.1 U19.5(Vout) U21.C1(VBAT) U21.C5(VDD) U21.C6(PDR_ON) U21.C7(VDD) U21.C8(VDD) U21.C9(VDD) U21.F3(VDD) U21.G3(VDD) U21.G13(VDD) U21.H13(VDD) U21.J12(VDD) U21.J13(VDD) U21.K4(VDD) U21.N8(VDD) U21.N9(VDD) U21.N10(VDD) U21.P1(VREF+) U21.R1(VDDA) X4.4(VDD)
5V: R153.2
5V_D: D7.1(A)
5V_EXT: D4.1(A)
5V_STLK: C71.2 TP21.1 U22.1(OUT)
5V_STLK_LDO_IN: C63.1 C64.2 D4.2(K) D5.2(K) D6.2(K) D7.2(K) D8.2(K) U19.1(Vin) U19.3(CE)
5V_USB_CHGR: C70.2 C72.1 C74.1 CN21.1(VBUS) D8.1(A) R149.2 R150.2 R152.2 TP20.1 U22.5(IN) U23.1(IO1)
5V_USB_FS: D6.1(A)
5V_USB_HS: D5.1(A)
GND: C63.2 C64.1 C65.1 C66.1 C67.1 C68.1 C69.1 C70.1 C71.1 C72.2 C74.2 C77.1 C171.1 C172.1 C173.1 C174.1 C175.1 C176.1 C177.1 C178.1 C179.1 C180.1 C181.1 C182.1 C183.1 C184.1 C185.1 C186.1 C187.1 C188.1 C190.1 C191.1 C192.1 CN19.2 CN21.5(GND) CN21.6(Shield) CN21.7(Shield) CN21.8(Shield) CN21.9(Shield) CN21.10(EXP) CN21.11(EXP) CN25.3 LD9.1(RED_cathode) R147.2 R148.2 R151.1 R154.1 R165.1 U19.2(GND) U21.D5(VSS) U21.D6(BOOT0) U21.D7(VSS) U21.D8(VSS) U21.D9(VSS) U21.F2(VSS) U21.F6(VSS) U21.F7(VSS) U21.F8(VSS) U21.F9(VSS) U21.F10(VSS) U21.F12(VSS) U21.G2(VSS) U21.G6(VSS) U21.G7(VSS) U21.G8(VSS) U21.G9(VSS) U21.G10(VSS) U21.G12(VSS) U21.H6(VSS) U21.H7(VSS) U21.H8(VSS) U21.H9(VSS) U21.H10(VSS) U21.H12(VSS) U21.J6(VSS) U21.J7(VSS) U21.J8(VSS) U21.J9(VSS) U21.J10(VSS) U21.K6(VSS) U21.K7(VSS) U21.K8(VSS) U21.K9(VSS) U21.K10(VSS) U21.M1(VSSA) U21.M8(VSS) U21.M9(VSS) U21.N1(VREF-) U22.2(GND) U23.2(GND) U26.3(GND) X4.2(GND)
FAULTn: LD8.2 R150.1 U22.3(~{FAULT})
GNDDetect: U21.K13(GNDDetect/PG5) ; port GNDDetect
LED_STLK: R190.2 R192.2 U21.D15(STLK_LED/PA10)
STLK_MCO: TP22.1 U21.F15(STLK_MCO/PA8)
STLK_SWCLK: CN25.2 U21.A14(STLK_SWCLK/PA14)
STLK_SWDIO: CN25.4 U21.A15(STLK_SWDIO/PA13)
STLK_VCP_RX: SB42.1 U21.C10(STLK_VCP_RX/PG9)
STLK_VCP_TX: SB41.1 U21.A7(STLK_VCP_TX/PG14)
T_NRST: R398.2 ; port T_NRST  [project net JTAG_HOST_NRST]
T_NRSTa: R398.1 U21.P3(T_NRST/PA6)
T_PWR_EN: R148.1 R152.1 U21.R5(T_PWR_EN/PB0) U22.4(EN)
T_PWR_EXT: R153.1 R154.2 U21.R4(T_PWR_EXT/PB1)
T_SWCLK: R401.2 ; port T_SWCLK  [project net JTAG_TCK]
T_SWCLKa: R401.1 U21.M11(T_SWCLK/PH6)
T_SWDIO: R409.2 ; port T_SWDIO  [project net JTAG_TMS]
T_SWDIO_IN: R157.1 U21.N12(T_SWDIO_IN/PH7)
T_SWDIOa: R157.2 R409.1 U21.L2(T_SWDIO_OUT/PF9)
T_SWO: R399.2 ; port T_SWO  [project net JTAG_TDO]
T_SWOa: R399.1 U21.D12(T_SWO/PD2)
T_VCP_RX: SB41.2 ; port T_VCP_RX
T_VCP_TX: SB42.2 ; port T_VCP_TX
USB_DEV_HS_CN_N: CN21.2(DM) U26.5(D-)
USB_DEV_HS_CN_P: CN21.3(DP) U26.6(D+)
USB_DEV_HS_N: U21.R14(USB_DEV_HS_N/PB14) U26.2(D-)
USB_DEV_HS_P: U21.R15(USB_DEV_HS_P/PB15) U26.1(D+)
NetC65_2: C65.2 U19.4(BYPASS)
NetC68_2: C68.2 CN19.1 U21.J1(NRST)
NetC77_2: C77.2 U21.J14(V12_OTGPHY)
NetC187_2: C187.2 U21.F13(VCAP2)
NetC188_2: C188.2 U21.M10(VCAP1)
NetLD8_1: LD8.1 R149.1
NetLD9_2: LD9.2(Red_anode) R190.1
NetLD9_3: LD9.3(YellowGreen_cathode) R192.1
NetR144_2: R144.2 X4.1(EN)
NetR145_1: R145.1 X4.3(OUT)
NetR145_2: R145.2 U21.G1(OSC_IN/PH0)
NetR146_1: R146.1 R147.1 U21.N3(T_VCC_AIN/PA0)
NetR151_2: R151.2 U21.L4(BYPASS-REG)
NetR165_2: R165.2 U21.J15(REXT_OTGPHY)

Not connected (* = marked no-connect by the designer): CN21 4(ID)*; U21 C4(HW_TYP_1/PI5)* D4(HW_TYP_0/PI4)* H1(OSC_OUT/PH1)* R3(T_SW_DIR/PA7)*; U26 4(NC)*

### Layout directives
differential pair; rule Impedance Constraint [Min = 85.00    Max = 95.00    ]: USB_DEV_HS_CN_N, USB_DEV_HS_CN_P, USB_DEV_HS_N, USB_DEV_HS_P

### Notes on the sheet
- STLINK V3E SWD
- (Always ON)
- Must be on a border or the PCB.
- PA13
- See JTAG page
- Silkscreen = Reserved
- PB14 or PA2
- PB15 or PA3
- PA14
- PB3
- Silkscreen = NRST
- LIMITATIONS (see MCU page) :
- (near R398) 0R must be close to STDC14 connector
  To disconnect STLINK V3 from target :
  - Remove 0R resistors and solder bridges
- Back up : if SD CARD 2, use UART VCOM back-up (PB14/PB15)
- (near CN21) Silkscreen = STLINK V3 USB HS
- LED Curr=4mA, Lum=25%

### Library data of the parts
C63 = MCD-00238: Capacitor, MLCC, 1uF, 6V3, X5R, 10%, 0603, T=0,8mm; Manufacturer_Part_Number: CC0603KRX5R5BB105; Manufacturer: YAGEO; Provided_By: SUBCO; ECCN_US: EAR99; ECCN_EU: NEC
C64 C68 C69 C71 C171-C176 C178 C180-C186 C190-C192 = MCD-00006: as C199 on sheet Peripherals
C65 = MCD-00011: as C46 on sheet Power_Board
C66 = MCD-00211: Capacitor, MLCC, 100nF, 16V, X7R, 10%, 0603, T=0,8mm; Manufacturer_Part_Number: CC0603KRX7R7BB104; Manufacturer: YAGEO; Provided_By: SUBCO; ECCN_US: EAR99; ECCN_EU: NEC
C67 C70 C179 = MCD-00010: as C4 on sheet Power_Board
C72 C177 = MCD-00009: Capacitor, MLCC, 4.7uF, 16V, X5R, 10%, 0603, T=0.8mm; Manufacturer_Part_Number: CC0603KRX5R7BB475; Manufacturer: YAGEO; Provided_By: SUBCO; ECCN_US: EAR99; ECCN_EU: NEC
C74 = MCD-00205: Capacitor, MLCC, 100pF, 50V, NPO, 5%, 0402, T=0,5mm; Manufacturer_Part_Number: CC0402JRNPO9BN101; Manufacturer: YAGEO; Provided_By: SUBCO; ECCN_US: EAR99; ECCN_EU: NEC
C77 C187 C188 = MCD-00012: Capacitor, MLCC, 2.2uF, 10V, X5R, 10%, 0603, T=0,8mm; Manufacturer_Part_Number: CC0603KRX5R6BB225; Manufacturer: YAGEO; Alternate_Manufacturer_Part_Number: C0603C225K8PACTU; Alternate_Manufacturer: KEMET; Provided_By: SUBCO; ECCN_US: EAR99; ECCN_EU: NEC
CN19 = MCD-00032: Header, 2x1, 2,54mm, VR, TH, Height 5.84mm/2.54mm; Part_Type: Connector; Manufacturer_Part_Number: TSW-102-07-x-S; Manufacturer: SAMTEC; Alternate_Manufacturer_Part_Number: 313102S111116; Alternate_Manufacturer: JIUBABA; Provided_By: SUBCO
CN21 = MCD-00028: USB-MICRO-B, 0.65mm, RA, SMT, Bottom Mount,; Manufacturer_Part_Number: 1050170001; Manufacturer: MOLEX; Part_Type: Connector; Provided_By: SUBCO
CN25 = MCD-00029: Header, 4x1, 2,54mm, VR, TH, Height 5.84mm/2.54mm; Manufacturer_Part_Number: TSW-104-07-x-S; Manufacturer: SAMTEC; Part_Type: Connector; Provided_By: SUBCO
D4-D8 = MCD-00034: Manufacturer: STMICROELECTRONICS; Part_Type: Diode; BMS_Part_Number: 9151097; Provided_By: SUBCO with ST control; ECCN_US: EAR99; ECCN_EU: NEC
LD8 = MCD-00587: as LD2 on sheet Peripherals
LD9 = MCD-00051: LED Bicolor; Part_Type: Display; Manufacturer_Part_Number: HSMF-A201-A00J1; Manufacturer: AVAGO TECHNOLOGIES; Alternate_Manufacturer_Part_Number: LE-RGW35280; Alternate_Manufacturer: EVERLUCK; Provided_By: SUBCO; ECCN_US: EAR99; ECCN_EU: NEC
R144 R148 R151 R152 = MCD-00053: as R194 on sheet Peripherals
R145 R157 = MCD-00067: Resistor,100R,0402,1%,1/16W; Manufacturer_Part_Number: RC0402FR-07100RL; Manufacturer: YAGEO; Provided_By: SUBCO; ECCN_US: EAR99; ECCN_EU: NEC
R146 R147 R154 = MCD-00065: Resistor,4K7,0402,1%,1/16W; Manufacturer_Part_Number: RC0402FR-074K7L; Manufacturer: YAGEO; Alternate_Manufacturer_Part_Number: RT0402FRE074K7L; Provided_By: SUBCO; ECCN_US: EAR99; ECCN_EU: NEC
R149 = MCD-00527: Resistor,820R,0402,1%,1/16W; Manufacturer_Part_Number: RC0402FR-07820RL; Manufacturer: YAGEO; Provided_By: SUBCO; ECCN_US: EAR99; ECCN_EU: NEC
R150 = MCD-00059: as R172 on sheet Peripherals
R153 = MCD-00055: Resistor,2K7,0402,1%,1/16W; Manufacturer_Part_Number: RC0402FR-072K7L; Manufacturer: YAGEO; Provided_By: SUBCO; ECCN_US: EAR99; ECCN_EU: NEC
R165 = MCD-00185: Resistor,3K,0402,1%,1/16W; Manufacturer_Part_Number: RC0402FR-073KL; Manufacturer: YAGEO; Provided_By: SUBCO; ECCN_US: EAR99; ECCN_EU: NEC
R190 R192 = MCD-00197: Resistor,330R,0603,1%,1/10W; Manufacturer_Part_Number: RC0603FR-07330RL; Manufacturer: YAGEO; BMS_Part_Number: 9129729; Provided_By: SUBCO; ECCN_US: EAR99; ECCN_EU: NEC
R398 R399 R401 R409 = MCD-00052: as R177 on sheet Peripherals
SB41 SB42 = MCD-01618: Solder Bridge 0402 ON; Part_Type: Mechanical; Manufacturer_Part_Number: RC0402JR-070RL; Manufacturer: YAGEO; Provided_By: SUBCO
TP19-TP21 = MCD-00712: as TP1 on sheet Power_Board
TP22 = MCD-00074: Test Point 1mm; Part_Type: Mechanical
U19 = MCD-00086: Ultra low drop-low noise BiCMOS voltage, regulators low ESR capacitors compatible; Manufacturer: STMICROELECTRONICS; Part_Type: IC; BMS_Part_Number: 9176161; Provided_By: SUBCO with ST control; ECCN_US: EAR99; ECCN_EU: NEC
U21 = MCD-00596: STM32F723IEK  (STM32F7) BGA176; Part_Type: IC; Manufacturer_Part_Number: STM32F723IEK6; Manufacturer: STMICROELECTRONICS; BMS_Part_Number: 9175300; Provided_By: SUBCO with ST control; ECCN_US: 3A991A2; ECCN_EU: NEC
U22 = MCD-00159: 500mA, Enhanced single channel power switches with active high enable pin; Part_Type: IC; Manufacturer: STMICROELECTRONICS; Alternate_Manufacturer_Part_Number: TPS2051C; Alternate_Manufacturer: TEXAS INSTRUMENTS; BMS_Part_Number: 9159009; Provided_By: SUBCO with ST control; ECCN_US: EAR99; ECCN_EU: NEC
U23 = MCD-00251: High power transient voltage suppressor, 7V breakdown; Part_Type: Diode; Manufacturer: STMICROELECTRONICS; BMS_Part_Number: 9179042; Provided_By: SUBCO with ST control; ECCN_US: EAR99; ECCN_EU: NEC
U26 = MCD-00649: Common mode filter with ESD protection for USB 2.0 interface; Part_Type: Diode; Manufacturer: STMICROELECTRONICS; BMS_Part_Number: 9151138; Provided_By: SUBCO with ST control; ECCN_US: EAR99; ECCN_EU: NEC
X4 = MCD-00597: Oscillator 25Mhz, +-50ppm, Vcc:3.3V typ, square wave: [0.1Vcc;0.9Vcc], Enable pin, SMD; Part_Type: Crystal_Osc; Manufacturer_Part_Number: NZ2520SH 25MHz END4869C; Manufacturer: NDK; Alternate_Manufacturer_Part_Number: NZ2520SB 25MHz END4869B; BMS_Part_Number: 9157050; Provided_By: SUBCO; ECCN_US: EAR99; ECCN_EU: NEC

## Sheet ExtensionConnector.SchDoc: Extension Connectors
size A4; Date: Not used; ApprovedBy: Not used; CheckedBy: Not used; Author: Not used; CompanyName: STMicroelectronics; DrawnBy: Not used; Engineer: Not used; Organization: Not used; Address1: Not used; Address2: Not used; Address3: Not used; Address4: Not used; DocumentNumber: Not used; Revision: Not used; SheetNumber: 19; SheetTotal: 23

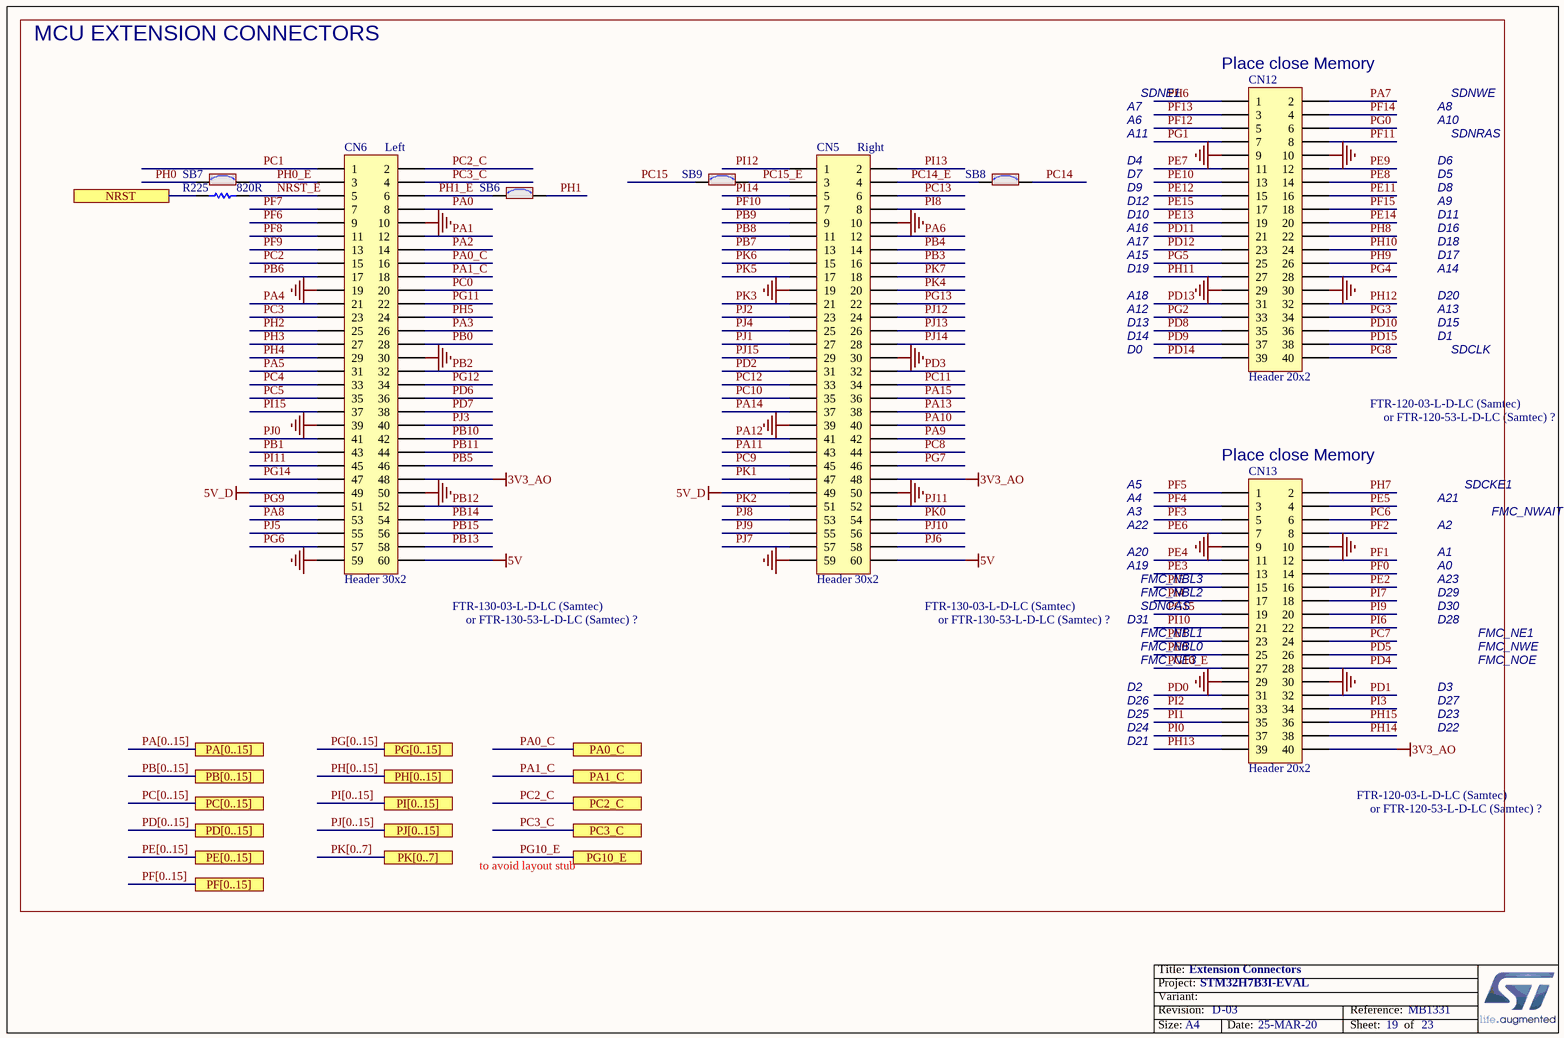
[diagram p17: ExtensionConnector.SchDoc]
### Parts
CN5  Header 30x2  [CON_SAMTEC_FTR-130-53-L-D-LC]
CN6  Header 30x2  [CON_SAMTEC_FTR-130-53-L-D-LC]
CN12  Header 20x2  [CON_SAMTEC_FTR-120-53-L-D-LC]
CN13  Header 20x2  [CON_SAMTEC_FTR-120-53-L-D-LC]
R225  value 820R  [R0603]  (hidden comment: Resistor)
SB6  SB_ON  [SOLDER-BRIDGE_R0603-0R]  (value not drawn)
SB7  SB_ON  [SOLDER-BRIDGE_R0603-0R]  (value not drawn)
SB8  SB_ON  [SOLDER-BRIDGE_R0603-0R]  (value not drawn)
SB9  SB_ON  [SOLDER-BRIDGE_R0603-0R]  (value not drawn)

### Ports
NRST, PA0_C, PA1_C, PA[0..15], PB[0..15], PC2_C, PC3_C, PC[0..15], PD[0..15], PE[0..15], PF[0..15], PG10_E, PG[0..15], PH[0..15], PI[0..15], PJ[0..15], PK[0..7]

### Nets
3V3_AO: CN5.48 CN6.48 CN13.40
5V: CN5.60 CN6.60
5V_D: CN5.49 CN6.49
GND: CN5.10 CN5.19 CN5.30 CN5.39 CN5.50 CN5.59 CN6.10 CN6.19 CN6.30 CN6.39 CN6.50 CN6.59 CN12.9 CN12.10 CN12.29 CN12.30 CN13.9 CN13.10 CN13.29 CN13.30
NRST: R225.1 ; port NRST
NRST_E: CN6.5 R225.2
PA0: CN6.8
PA0_C: CN6.16 ; port PA0_C
PA1: CN6.12
PA1_C: CN6.18 ; port PA1_C
PA2: CN6.14
PA3: CN6.26
PA4: CN6.21
PA5: CN6.31
PA6: CN5.12
PA7: CN12.2
PA8: CN6.53
PA9: CN5.42
PA10: CN5.40
PA11: CN5.43
PA12: CN5.41
PA13: CN5.38
PA14: CN5.37
PA15: CN5.36
PB0: CN6.28
PB1: CN6.43
PB2: CN6.32
PB3: CN5.16
PB4: CN5.14
PB5: CN6.46
PB6: CN6.17  [project net DFSDM1_DATIN5]
PB7: CN5.13
PB8: CN5.11
PB9: CN5.9
PB10: CN6.42
PB11: CN6.44
PB12: CN6.52
PB13: CN6.58
PB14: CN6.54
PB15: CN6.56
PC0: CN6.20
PC1: CN6.1
PC2: CN6.15
PC2_C: CN6.2 ; port PC2_C
PC3: CN6.23
PC3_C: CN6.4 ; port PC3_C
PC4: CN6.33
PC5: CN6.35
PC6: CN13.6
PC7: CN13.24
PC8: CN5.44
PC9: CN5.45
PC10: CN5.35
PC11: CN5.34
PC12: CN5.33
PC13: CN5.6
PC14: SB8.2
PC14_E: CN5.4 SB8.1
PC15: SB9.1
PC15_E: CN5.3 SB9.2
PD0: CN13.31
PD1: CN13.32
PD2: CN5.31
PD3: CN5.32
PD4: CN13.28
PD5: CN13.26
PD6: CN6.36
PD7: CN6.38
PD8: CN12.35
PD9: CN12.37
PD10: CN12.36
PD11: CN12.21
PD12: CN12.23
PD13: CN12.31
PD14: CN12.39
PD15: CN12.38
PE0: CN13.25
PE1: CN13.23
PE2: CN13.16
PE3: CN13.13
PE4: CN13.11
PE5: CN13.4
PE6: CN13.7
PE7: CN12.11
PE8: CN12.14
PE9: CN12.12
PE10: CN12.13
PE11: CN12.16
PE12: CN12.15
PE13: CN12.19
PE14: CN12.20
PE15: CN12.17
PF0: CN13.14
PF1: CN13.12
PF2: CN13.8
PF3: CN13.5
PF4: CN13.3
PF5: CN13.1
PF6: CN6.9
PF7: CN6.7
PF8: CN6.11
PF9: CN6.13
PF10: CN5.7
PF11: CN12.8
PF12: CN12.5
PF13: CN12.3
PF14: CN12.4
PF15: CN12.18
PG0: CN12.6
PG1: CN12.7
PG2: CN12.33
PG3: CN12.34
PG4: CN12.28
PG5: CN12.25
PG6: CN6.57
PG7: CN5.46
PG8: CN12.40
PG9: CN6.51
PG10_E: CN13.27 ; port PG10_E
PG11: CN6.22
PG12: CN6.34
PG13: CN5.22
PG14: CN6.47
PG15: CN13.19
PH0: SB7.1
PH0_E: CN6.3 SB7.2
PH1: SB6.2
PH1_E: CN6.6 SB6.1
PH2: CN6.25  [project net CTP_INT]
PH3: CN6.27
PH4: CN6.29
PH5: CN6.24
PH6: CN12.1
PH7: CN13.2
PH8: CN12.22
PH9: CN12.26
PH10: CN12.24
PH11: CN12.27
PH12: CN12.32
PH13: CN13.39
PH14: CN13.38
PH15: CN13.36
PI0: CN13.37
PI1: CN13.35
PI2: CN13.33
PI3: CN13.34
PI4: CN13.17
PI5: CN13.15
PI6: CN13.22
PI7: CN13.18
PI8: CN5.8
PI9: CN13.20
PI10: CN13.21
PI11: CN6.45
PI12: CN5.1
PI13: CN5.2
PI14: CN5.5
PI15: CN6.37
PJ0: CN6.41
PJ1: CN5.27
PJ2: CN5.23
PJ3: CN6.40
PJ4: CN5.25
PJ5: CN6.55
PJ6: CN5.58
PJ7: CN5.57
PJ8: CN5.53
PJ9: CN5.55
PJ10: CN5.56
PJ11: CN5.52
PJ12: CN5.24
PJ13: CN5.26
PJ14: CN5.28
PJ15: CN5.29
PK0: CN5.54
PK1: CN5.47
PK2: CN5.51
PK3: CN5.21
PK4: CN5.20
PK5: CN5.17
PK6: CN5.15
PK7: CN5.18

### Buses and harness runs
bus PA[0..15] = port PA[0..15]
bus PB[0..15] = port PB[0..15]
bus PC[0..15] = port PC[0..15]
bus PD[0..15] = port PD[0..15]
bus PE[0..15] = port PE[0..15]
bus PF[0..15] = port PF[0..15]
bus PG[0..15] = port PG[0..15]
bus PH[0..15] = port PH[0..15]
bus PI[0..15] = port PI[0..15]
bus PJ[0..15] = port PJ[0..15]
bus PK[0..7] = port PK[0..7]

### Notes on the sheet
- MCU EXTENSION CONNECTORS
- A7
- SDNE1
- (near CN12) Place close Memory
- A8
- SDNWE
- (near CN6) Left
- (near CN5) Right
- D4
- D7
- A6
- A11
- D5
- D6
- A10
- SDNRAS
- A16
- A17
- D9
- D10
- D12
- D8
- D11
- A9
- D16
- D18
- A18
- A12
- A15
- D19
- A13
- A14
- D17
- D20
- D13
- D14
- D0
- D15
- D1
- SDCLK
- (near CN12) FTR-120-03-L-D-LC (Samtec)
- or FTR-120-53-L-D-LC (Samtec) ?
- A3
- A4
- A5
- (near CN13) Place close Memory
- A21
- SDCKE1
- FMC_NWAIT
- A19
- A20
- A22
- FMC_NBL3
- A23
- A0
- A1
- A2
- (near CN6) FTR-130-03-L-D-LC (Samtec)
- or FTR-130-53-L-D-LC (Samtec) ?
- (near CN5) FTR-130-03-L-D-LC (Samtec)
- D31
- FMC_NBL0
- FMC_NBL1
- SDNCAS
- FMC_NBL2
- D28
- D29
- D30
- FMC_NWE
- FMC_NE1
- D2
- D25
- D26
- FMC_NE3
- D3
- D23
- D27
- FMC_NOE
- D21
- D24
- D22
- (near CN13) FTR-120-03-L-D-LC (Samtec)
- to avoid layout stub

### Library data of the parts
CN5 CN6 = MCD-00576: Header 30x2, 1.27mm, VR, CMS, Height 7.24mm; Part_Type: Connector; Manufacturer_Part_Number: FTR-130-53-L-D-LC; Manufacturer: SAMTEC; Alternate_Manufacturer_Part_Number: P1039-2*30MGF-089-1A; Alternate_Manufacturer: JIUBABA; Provided_By: SUBCO
CN12 CN13 = MCD-00578: Header 20x2, 1.27mm, VR, CMS, Height 7.24mm; Part_Type: Connector; Manufacturer_Part_Number: FTR-120-53-L-D-LC; Manufacturer: SAMTEC; Alternate_Manufacturer_Part_Number: P1039-2*20MGF-089-1A; Alternate_Manufacturer: JIUBABA; Provided_By: SUBCO
R225 = MCD-00528: Resistor,820R,0603,1%,1/10W; Manufacturer_Part_Number: RC0603FR-07820RL; Manufacturer: YAGEO; BMS_Part_Number: 9129759; Provided_By: SUBCO; ECCN_US: EAR99; ECCN_EU: NEC
SB6-SB9 = MCD-00071: as SB45 on sheet Peripherals

## Sheet USB_OTG_FS.SchDoc: USB_OTG_FS
size A4; Date: Not used; ApprovedBy: Not used; CheckedBy: Not used; Author: Not used; CompanyName: STMicroelectronics; DrawnBy: Not used; Engineer: Not used; Organization: Not used; Address1: Not used; Address2: Not used; Address3: Not used; Address4: Not used; DocumentNumber: Not used; Revision: Not used; SheetNumber: 5; SheetTotal: 23

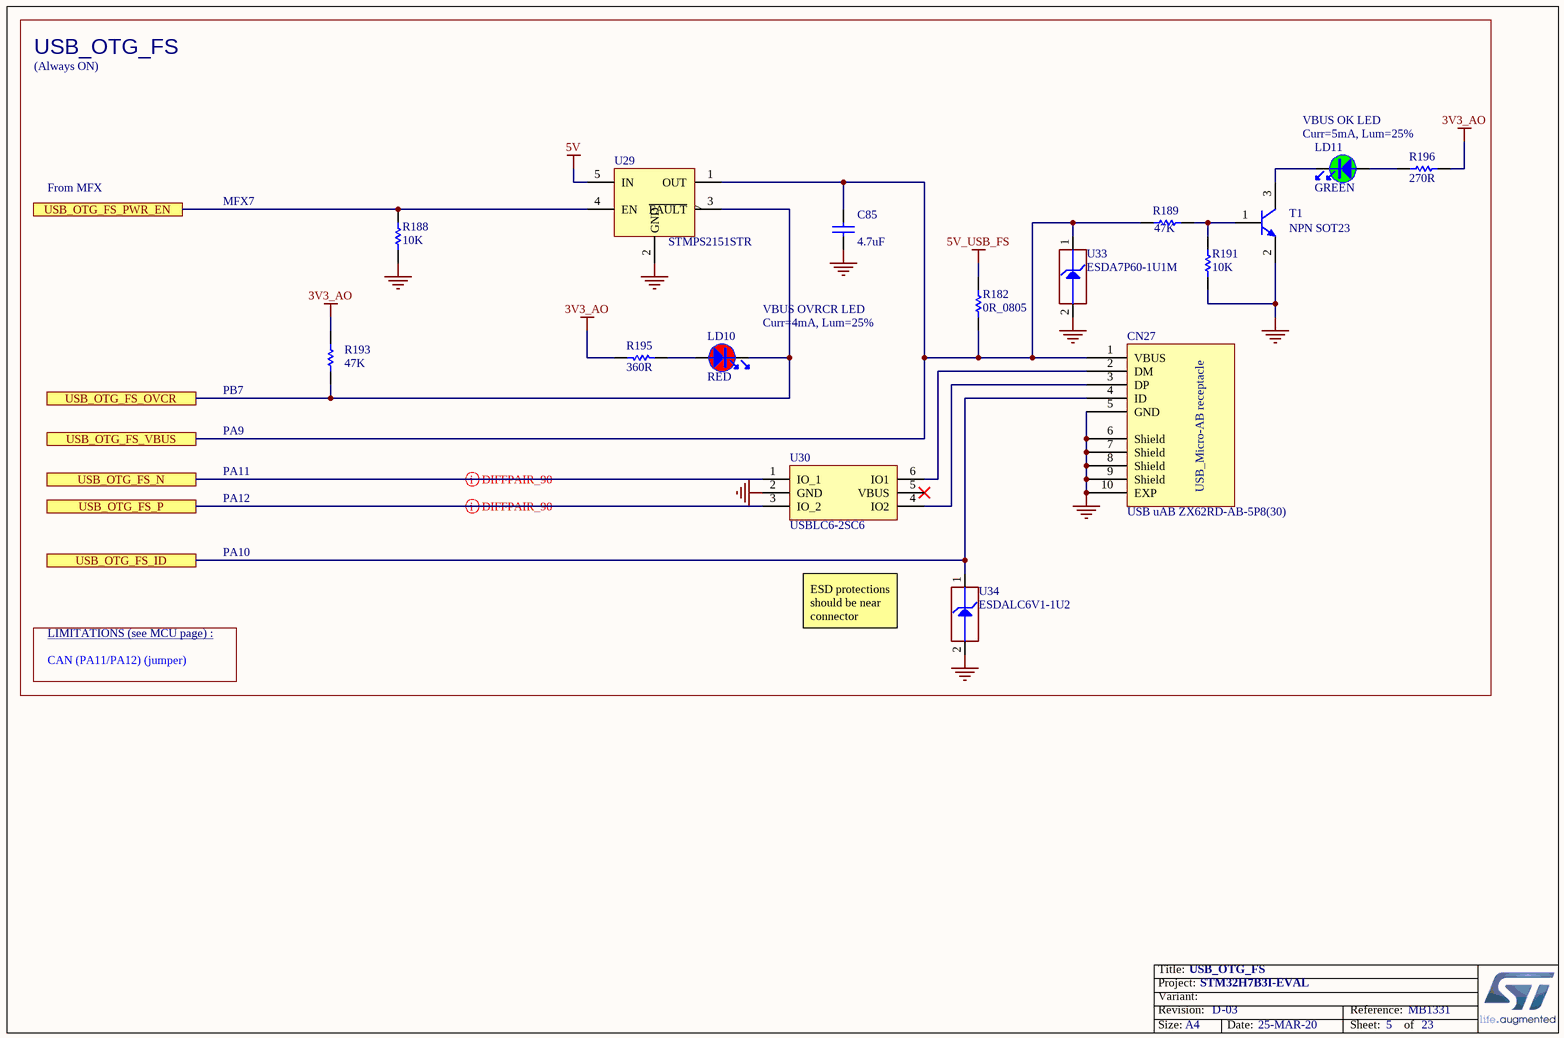
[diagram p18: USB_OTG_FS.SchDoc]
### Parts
C85  value 4.7uF  [C0603]  (hidden comment: Capacitor)
CN27  value USB uAB ZX62RD-AB-5P8(30)  [CON_USBMICROAB_MOLEX_47590-0001_H3]  (hidden comment: USB_uAB_47590.0001)
LD10  value RED  [LED_0603_VISHAY_VLMS1300-GS08_RED_1A2K_H0P8]  (hidden comment: LED_red)
LD11  value GREEN  [LED_0603_OSRAM_LG-Q396-PS-35_GREEN_1A2K_H0P4]  (hidden comment: LED_green)
R182  value 0R_0805  [R0805]  (hidden comment: Resistor)
R188  value 10K  [R0402]  (hidden comment: Resistor)
R189  value 47K  [R0402]  (hidden comment: Resistor)
R191  value 10K  [R0402]  (hidden comment: Resistor)
R193  value 47K  [R0402]  (hidden comment: Resistor)
R195  value 360R  [R0402]  (hidden comment: Resistor)
R196  value 270R  [R0402]  (hidden comment: Resistor)
T1  value NPN SOT23  [NPN_SOT23]  (hidden comment: 9013-SOT23)
U29  STMPS2151STR  [MOS_SOT23-5L]
U30  USBLC6-2SC6  [ESD_SOT23-6L]
U33  value ESDA7P60-1U1M  [ESD_QFN2_1P6X1_P125]  (hidden comment: ESD-TRANSIL)
U34  value ESDALC6V1-1U2  [ESD_ST0201]  (hidden comment: ESD-TRANSIL)

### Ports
USB_OTG_FS_ID, USB_OTG_FS_N, USB_OTG_FS_OVCR, USB_OTG_FS_P, USB_OTG_FS_PWR_EN, USB_OTG_FS_VBUS

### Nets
3V3_AO: R193.2 R195.2 R196.2
5V: U29.5(IN)
5V_USB_FS: R182.2
GND: C85.1 CN27.5(GND) CN27.6(Shield) CN27.7(Shield) CN27.8(Shield) CN27.9(Shield) CN27.10(EXP) R188.2 R191.1 T1.2(E) U29.2(GND) U30.2(GND) U33.2(GND) U34.2(GND)
USB_OTG_FS_ID: CN27.4(ID) U34.1(IO1) ; port USB_OTG_FS_ID
USB_OTG_FS_N: U30.1(IO_1) ; port USB_OTG_FS_N
USB_OTG_FS_OVCR: LD10.2 R193.1 U29.3(~{FAULT}) ; port USB_OTG_FS_OVCR
USB_OTG_FS_P: U30.3(IO_2) ; port USB_OTG_FS_P
USB_OTG_FS_PWR_EN: R188.1 U29.4(EN) ; port USB_OTG_FS_PWR_EN
USB_OTG_FS_VBUS: C85.2 CN27.1(VBUS) R182.1 R189.1 U29.1(OUT) U33.1(IO1) ; port USB_OTG_FS_VBUS
NetCN27_2: CN27.2(DM) U30.6(IO1)
NetCN27_3: CN27.3(DP) U30.4(IO2)
NetLD10_1: LD10.1 R195.1
NetLD11_1: LD11.1 R196.1
NetLD11_2: LD11.2 T1.3(C)
NetR189_2: R189.2 R191.2 T1.1(B)

Not connected (* = marked no-connect by the designer): U30 5(VBUS)*

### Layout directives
differential pair: USB_OTG_FS_N, USB_OTG_FS_P

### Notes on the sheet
- USB_OTG_FS
- (Always ON)
- VBUS OK LED
- Curr=5mA, Lum=25%
- From MFX
- MFX7
- VBUS OVRCR LED
- Curr=4mA, Lum=25%
- PA9
- PB7
- PA11
- PA12
- PA10
- LIMITATIONS (see MCU page) :
- ESD protections should be near connector
- CAN (PA11/PA12) (jumper)

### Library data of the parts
C85 = MCD-00009: as C72 on sheet STLink_V3E_SWD
CN27 = MCD-00661: USB-MICRO-AB Receptacle, RA, SMT + DIP, Standard, Top Mount, USB certified (symbol & footprint compatible with MCD-00022); Part_Type: Connector; Manufacturer_Part_Number: ZX62RD-AB-5P8(30); Manufacturer: HIROSE; Provided_By: SUBCO
LD10 = MCD-00587: as LD2 on sheet Peripherals
LD11 = MCD-00588: as LD1 on sheet Peripherals
R182 = MCD-00179: Resistor,0R,0805,5%; Manufacturer_Part_Number: RC0805JR-070RL; Manufacturer: YAGEO; Provided_By: SUBCO; ECCN_US: EAR99; ECCN_EU: NEC
R188 R191 = MCD-00053: as R194 on sheet Peripherals
R189 R193 = MCD-00063: Resistor,47K,0402,1%,1/16W; Manufacturer_Part_Number: RC0402FR-0747KL; Manufacturer: YAGEO; Provided_By: SUBCO; ECCN_US: EAR99; ECCN_EU: NEC
R195 = MCD-00461: as R179 on sheet Peripherals
R196 = MCD-00441: as R178 on sheet Peripherals
T1 = MCD-00073: NPN Bipolar Transistor; Manufacturer_Part_Number: BSR14; Manufacturer: ON SEMICONDUCTOR; Part_Type: IC; Alternate_Manufacturer_Part_Number: MMBT2222LT1G / MMBT2222ALT1G / MMBT2222ALT3G; Provided_By: SUBCO; ECCN_US: EAR99; ECCN_EU: NEC
U29 = MCD-00159: 500mA, Enhanced single channel power switches with active high enable pin; Manufacturer: STMICROELECTRONICS; Part_Type: IC; Alternate_Manufacturer_Part_Number: TPS2051C; Alternate_Manufacturer: TEXAS INSTRUMENTS; BMS_Part_Number: 9159009; Provided_By: SUBCO with ST control; ECCN_US: EAR99; ECCN_EU: NEC
U30 = MCD-00163: Very low capacitance ESD protection; Part_Type: IC; Manufacturer: STMICROELECTRONICS; BMS_Part_Number: 9151075; Provided_By: SUBCO with ST control; ECCN_US: EAR99; ECCN_EU: NEC
U33 = MCD-00251: as U23 on sheet STLink_V3E_SWD
U34 = MCD-00170: as U32 on sheet Peripherals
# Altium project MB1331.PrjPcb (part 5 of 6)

## Sheet USB_OTG_HS_externalPHY.SchDoc: USB OTG HS with external PHY
size A4; Date: Not used; ApprovedBy: Not used; CheckedBy: Not used; Author: Not used; CompanyName: STMicroelectronics; DrawnBy: Not used; Engineer: Not used; Organization: Not used; Address1: Not used; Address2: Not used; Address3: Not used; Address4: Not used; DocumentNumber: Not used; Revision: Not used; SheetNumber: 6; SheetTotal: 23

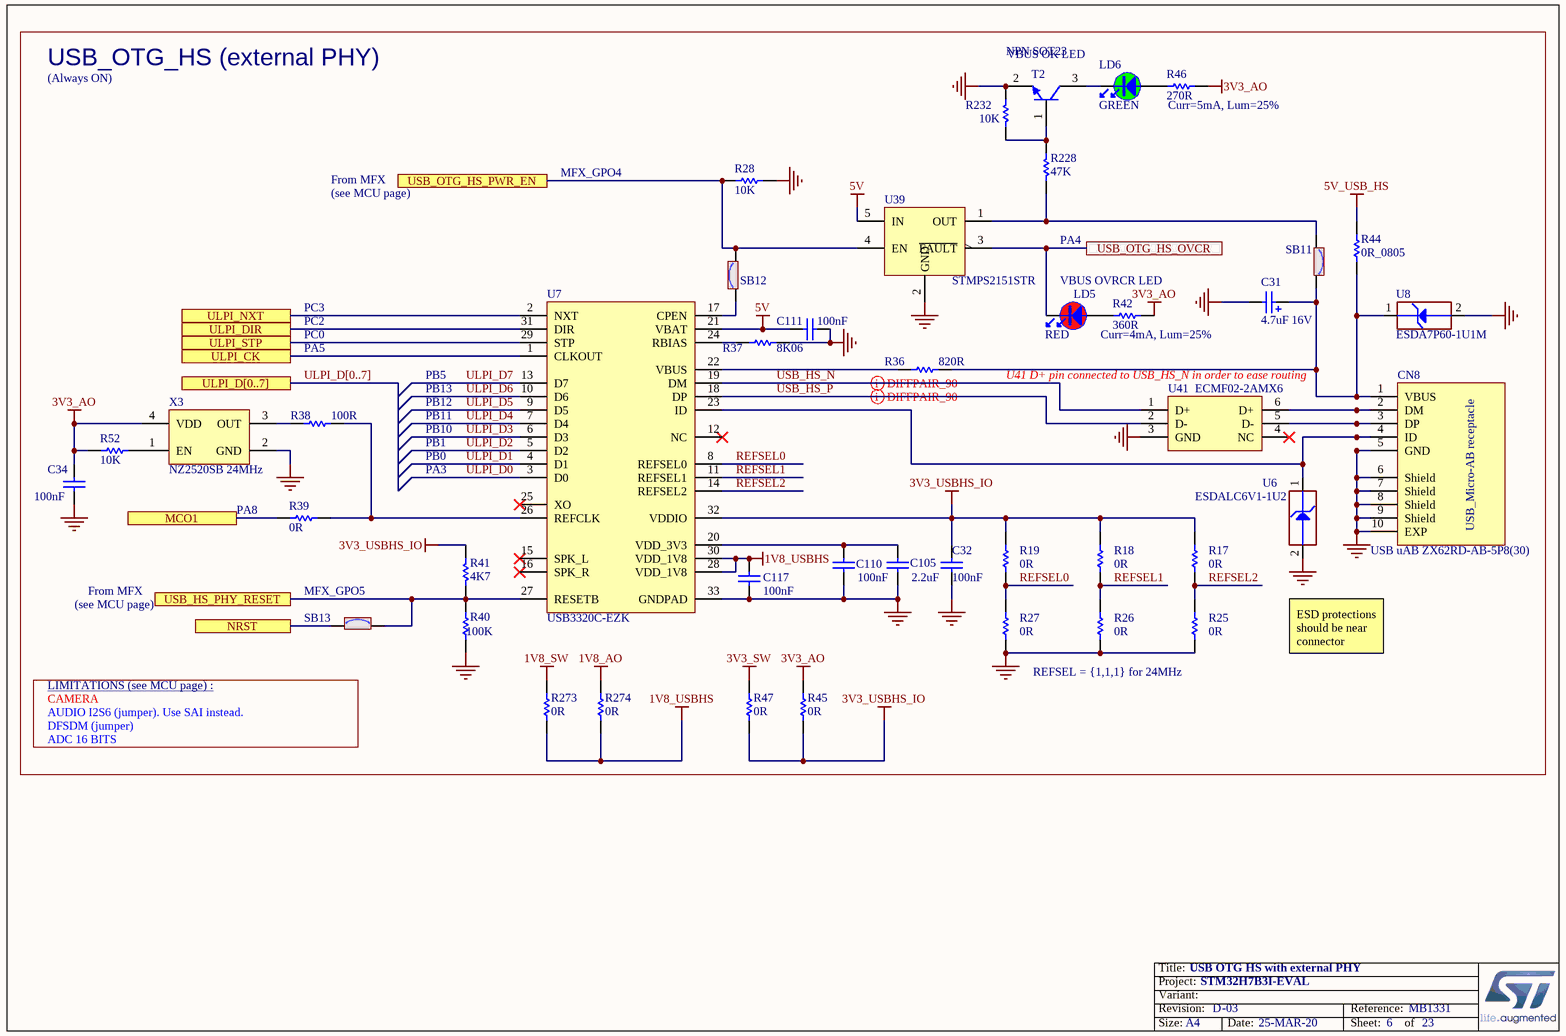
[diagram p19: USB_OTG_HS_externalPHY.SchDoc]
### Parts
C31  value 4.7uF 16V  [CPOL_TAJ-A_1206_H180]  (hidden comment: Cap_POL_TANA)
C32  value 100nF  [C0402]  (hidden comment: Capacitor)
C34  value 100nF  [C0402]  (hidden comment: Capacitor)
C105  value 2.2uF  [C0603]  (hidden comment: Capacitor)
C110  value 100nF  [C0402]  (hidden comment: Capacitor)
C111  value 100nF  [C0402]  (hidden comment: Capacitor)
C117  value 100nF  [C0402]  (hidden comment: Capacitor)
CN8  value USB uAB ZX62RD-AB-5P8(30)  [CON_USBMICROAB_MOLEX_47590-0001_H3]  (hidden comment: USB_uAB_47590.0001)
LD5  value RED  [LED_0603_VISHAY_VLMS1300-GS08_RED_1A2K_H0P8]  (hidden comment: LED_red)
LD6  value GREEN  [LED_0603_OSRAM_LG-Q396-PS-35_GREEN_1A2K_H0P4]  (hidden comment: LED_green)
R17  value 0R  [R0603]  (hidden comment: Resistor)
R18  value 0R  [R0603]  (hidden comment: Resistor)
R19  value 0R  [R0603]  (hidden comment: Resistor)
R25  value 0R  [R0603]  (hidden comment: Resistor)
R26  value 0R  [R0603]  (hidden comment: Resistor)
R27  value 0R  [R0603]  (hidden comment: Resistor)
R28  value 10K  [R0402]  (hidden comment: Resistor)
R36  value 820R  [R0603]  (hidden comment: Resistor)
R37  value 8K06  [R0603]  (hidden comment: Resistor)
R38  value 100R  [R0402]  (hidden comment: Resistor)
R39  value 0R  [R0402]  (hidden comment: Resistor)
R40  value 100K  [R0402]  (hidden comment: Resistor)
R41  value 4K7  [R0402]  (hidden comment: Resistor)
R42  value 360R  [R0402]  (hidden comment: Resistor)
R44  value 0R_0805  [R0805]  (hidden comment: Resistor)
R45  value 0R  [R0603]  (hidden comment: Resistor)
R46  value 270R  [R0402]  (hidden comment: Resistor)
R47  value 0R  [R0603]  (hidden comment: Resistor)
R52  value 10K  [R0402]  (hidden comment: Resistor)
R228  value 47K  [R0402]  (hidden comment: Resistor)
R232  value 10K  [R0402]  (hidden comment: Resistor)
R273  value 0R  [R0603]  (hidden comment: Resistor)
R274  value 0R  [R0603]  (hidden comment: Resistor)
SB11  SB_ON  [SOLDER-BRIDGE_R0603-0R]  (value not drawn)
SB12  SB_ON  [SOLDER-BRIDGE_R0603-0R]  (value not drawn)
SB13  SB_ON  [SOLDER-BRIDGE_R0603-0R]  (value not drawn)
T2  value NPN SOT23  [NPN_SOT23]  (hidden comment: 9013-SOT23)
U6  value ESDALC6V1-1U2  [ESD_ST0201]  (hidden comment: ESD-TRANSIL)
U7  USB3320C-EZK  [ICC_QFN32-EPAD_5X5_P050]
U8  value ESDA7P60-1U1M  [ESD_QFN2_1P6X1_P125]  (hidden comment: ESD-TRANSIL)
U39  STMPS2151STR  [MOS_SOT23-5L]
U41  ECMF02-2AMX6  [ESD_QFN-6L_1P7X1P5_P050]
X3  value NZ2520SB 24MHz  [OSC_NDK_NZ2520SB_4P]  (hidden comment: OSCILLATOR_4_PINS)

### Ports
MCO1, NRST, ULPI_CK, ULPI_D[0..7], ULPI_DIR, ULPI_NXT, ULPI_STP, USB_HS_PHY_RESET, USB_OTG_HS_OVCR, USB_OTG_HS_PWR_EN

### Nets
1V8_AO: R274.1
1V8_SW: R273.1
1V8_USBHS: C117.1 R273.2 R274.2 U7.28(VDD_1V8) U7.30(VDD_1V8)
3V3_AO: C34.2 R42.2 R45.1 R46.2 R52.1 X3.4(VDD)
3V3_SW: R47.1
3V3_USBHS_IO: C32.2 R17.2 R18.2 R19.2 R41.2 R45.2 R47.2 U7.32(VDDIO)
5V: C111.1 U7.21(VBAT) U39.5(IN)
5V_USB_HS: R44.2
GND: C31.2 C32.1 C34.1 C105.1 C110.2 C111.2 C117.2 CN8.5(GND) CN8.6(Shield) CN8.7(Shield) CN8.8(Shield) CN8.9(Shield) CN8.10(EXP) R25.1 R26.1 R27.1 R28.2 R37.2 R40.1 R232.1 T2.2(E) U6.2(GND) U7.33(GNDPAD) U8.2(GND) U39.2(GND) U41.3(GND) X3.2(GND)
MCO1: R39.1 ; port MCO1
NRST: SB13.2 ; port NRST
REFSEL0: R19.1 R27.2 U7.8(REFSEL0)
REFSEL1: R18.1 R26.2 U7.11(REFSEL1)
REFSEL2: R17.1 R25.2 U7.14(REFSEL2)
ULPI_CK: U7.1(CLKOUT) ; port ULPI_CK
ULPI_D0: U7.3(D0)
ULPI_D1: U7.4(D1)
ULPI_D2: U7.5(D2)
ULPI_D3: U7.6(D3)
ULPI_D4: U7.7(D4)
ULPI_D5: U7.9(D5)
ULPI_D6: U7.10(D6)
ULPI_D7: U7.13(D7)
ULPI_DIR: U7.31(DIR) ; port ULPI_DIR
ULPI_NXT: U7.2(NXT) ; port ULPI_NXT
ULPI_STP: U7.29(STP) ; port ULPI_STP
USB_HS_N: U7.19(DM) U41.1(D+)
USB_HS_P: U7.18(DP) U41.2(D-)
USB_HS_PHY_RESET: R40.2 R41.1 SB13.1 U7.27(RESETB) ; port USB_HS_PHY_RESET
USB_OTG_HS_OVCR: LD5.2 U39.3(~{FAULT}) ; port USB_OTG_HS_OVCR
USB_OTG_HS_PWR_EN: R28.1 SB12.1 U39.4(EN) ; port USB_OTG_HS_PWR_EN
NetC31_1: C31.1 CN8.1(VBUS) R36.2 R44.1 SB11.2 U8.1(IO1)
NetC105_2: C105.2 C110.1 U7.20(VDD_3V3)
NetCN8_2: CN8.2(DM) U41.6(D+)
NetCN8_3: CN8.3(DP) U41.5(D-)
NetCN8_4: CN8.4(ID) U6.1(IO1) U7.23(ID)
NetLD5_1: LD5.1 R42.1
NetLD6_1: LD6.1 R46.1
NetLD6_2: LD6.2 T2.3(C)
NetR36_1: R36.1 U7.22(VBUS)
NetR37_1: R37.1 U7.24(RBIAS)
NetR38_1: R38.1 X3.3(OUT)
NetR38_2: R38.2 R39.2 U7.26(REFCLK)
NetR52_2: R52.2 X3.1(EN)
NetR228_1: R228.1 SB11.1 U39.1(OUT)
NetR228_2: R228.2 R232.2 T2.1(B)
NetSB12_2: SB12.2 U7.17(CPEN)

Not connected (* = marked no-connect by the designer): U7 12(NC)* 15(SPK_L)* 16(SPK_R)* 25(XO)*; U41 4(NC)*

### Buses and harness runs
bus ULPI_D[0..7] = port ULPI_D[0..7]

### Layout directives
differential pair: USB_HS_N, USB_HS_P

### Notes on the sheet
- VBUS OK LED
- USB_OTG_HS (external PHY)
- (Always ON)
- (near R46) Curr=5mA, Lum=25%
- MFX_GPO4
- From MFX
- (see MCU page)
- PA4
- PC3
- VBUS OVRCR LED
- PC2
- PC0
- PA5
- PB5
- (near U41) U41 D+ pin connected to USB_HS_N in order to ease routing
- Curr=4mA, Lum=25%
- PB1
- PB10
- PB11
- PB12
- PB13
- PA8
- PA3
- PB0
- (near SB13) MFX_GPO5
- ESD protections should be near connector
- LIMITATIONS (see MCU page) :
- AUDIO I2S6 (jumper). Use SAI instead.
- CAMERA
- REFSEL = {1,1,1} for 24MHz
- DFSDM (jumper)
- ADC 16 BITS

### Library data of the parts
C31 = MCD-00007: Capacitor, Tantalum, 4.7uF, 16V, 10%, 4ohms, pkg Type_A (3216 metric), T=1.6mm; Manufacturer_Part_Number: TAJA475K016R; Manufacturer: AVX; Provided_By: SUBCO; ECCN_US: EAR99; ECCN_EU: NEC
C32 C34 C110 C111 C117 = MCD-00006: Capacitor, MLCC, 100nF, 16V, X7R, 10%, 0402, T=0.5mm; Manufacturer_Part_Number: CC0402KRX7R7BB104; Manufacturer: YAGEO; Alternate_Manufacturer_Part_Number: GCM155R71C104KA55D; Alternate_Manufacturer: MURATA; Provided_By: SUBCO; ECCN_US: EAR99; ECCN_EU: NEC
C105 = MCD-00012: Capacitor, MLCC, 2.2uF, 10V, X5R, 10%, 0603, T=0,8mm; Manufacturer_Part_Number: CC0603KRX5R6BB225; Manufacturer: YAGEO; Alternate_Manufacturer_Part_Number: C0603C225K8PACTU; Alternate_Manufacturer: KEMET; Provided_By: SUBCO; ECCN_US: EAR99; ECCN_EU: NEC
CN8 = MCD-00661: USB-MICRO-AB Receptacle, RA, SMT + DIP, Standard, Top Mount, USB certified (symbol & footprint compatible with MCD-00022); Part_Type: Connector; Manufacturer_Part_Number: ZX62RD-AB-5P8(30); Manufacturer: HIROSE; Provided_By: SUBCO
LD5 = MCD-00587: LED Red, 0603 SMD, 2V Forward Voltage; Part_Type: Display; Manufacturer_Part_Number: VLMS1300-GS08; Manufacturer: VISHAY; Alternate_Manufacturer_Part_Number: LS Q976-NR-1; Alternate_Manufacturer: OSRAM OPTO SEMICONDUCTORS; Provided_By: SUBCO
LD6 = MCD-00588: LED Green, 0603 SMD, Forward Voltage Typ=2V, Max=2.5V; Part_Type: Display; Manufacturer_Part_Number: LG Q396-PS-35; Manufacturer: OSRAM OPTO SEMICONDUCTORS; Alternate_Manufacturer_Part_Number: VLMTG1300-GS08; Alternate_Manufacturer: VISHAY SEMICONDUCTOR OPTO DIVISION; Provided_By: SUBCO
R17-R19 R25-R27 R45 R47 R273 R274 = MCD-00056: Resistor,0R,0603,5%,1/10W; Manufacturer_Part_Number: RC0603JR-070RL; Manufacturer: YAGEO; Provided_By: SUBCO; ECCN_US: EAR99; ECCN_EU: NEC
R28 R52 R232 = MCD-00053: Resistor,10K,0402,1%,1/16W; Manufacturer_Part_Number: RC0402FR-0710KL; Manufacturer: YAGEO; Provided_By: SUBCO; ECCN_US: EAR99; ECCN_EU: NEC
R36 = MCD-00528: Resistor,820R,0603,1%,1/10W; Manufacturer_Part_Number: RC0603FR-07820RL; Manufacturer: YAGEO; BMS_Part_Number: 9129759; Provided_By: SUBCO; ECCN_US: EAR99; ECCN_EU: NEC
R37 = MCD-00570: Resistor,8K06,0603,1%,1/10W; Manufacturer_Part_Number: RC0603FR-078K06L; Manufacturer: YAGEO; Provided_By: SUBCO; ECCN_US: EAR99; ECCN_EU: NEC
R38 = MCD-00067: Resistor,100R,0402,1%,1/16W; Manufacturer_Part_Number: RC0402FR-07100RL; Manufacturer: YAGEO; Provided_By: SUBCO; ECCN_US: EAR99; ECCN_EU: NEC
R39 = MCD-00052: Resistor,0R,0402,5%,1/16W; Manufacturer_Part_Number: RC0402JR-070RL; Manufacturer: YAGEO; Provided_By: SUBCO; ECCN_US: EAR99; ECCN_EU: NEC
R40 = MCD-00059: Resistor,100K,0402,1%,1/16W; Manufacturer_Part_Number: RC0402FR-07100KL; Manufacturer: YAGEO; Alternate_Manufacturer_Part_Number: RT0402FRE07100KL; Provided_By: SUBCO; ECCN_US: EAR99; ECCN_EU: NEC
R41 = MCD-00065: Resistor,4K7,0402,1%,1/16W; Manufacturer_Part_Number: RC0402FR-074K7L; Manufacturer: YAGEO; Alternate_Manufacturer_Part_Number: RT0402FRE074K7L; Provided_By: SUBCO; ECCN_US: EAR99; ECCN_EU: NEC
R42 = MCD-00461: Resistor,360R,0402,1%,1/16W; Manufacturer_Part_Number: RC0402FR-07360RL; Manufacturer: YAGEO; Provided_By: SUBCO; ECCN_US: EAR99; ECCN_EU: NEC
R44 = MCD-00179: Resistor,0R,0805,5%; Manufacturer_Part_Number: RC0805JR-070RL; Manufacturer: YAGEO; Provided_By: SUBCO; ECCN_US: EAR99; ECCN_EU: NEC
R46 = MCD-00441: Resistor,270R,0402,1%,1/16W; Manufacturer_Part_Number: RC0402FR-07270RL; Manufacturer: YAGEO; Provided_By: SUBCO; ECCN_US: EAR99; ECCN_EU: NEC
R228 = MCD-00063: Resistor,47K,0402,1%,1/16W; Manufacturer_Part_Number: RC0402FR-0747KL; Manufacturer: YAGEO; Provided_By: SUBCO; ECCN_US: EAR99; ECCN_EU: NEC
SB11-SB13 = MCD-00071: Solder Bridge ON; Part_Type: Mechanical; Manufacturer_Part_Number: RC0603JR-070RL; Manufacturer: YAGEO; Provided_By: SUBCO
T2 = MCD-00073: NPN Bipolar Transistor; Manufacturer_Part_Number: BSR14; Manufacturer: ON SEMICONDUCTOR; Part_Type: IC; Alternate_Manufacturer_Part_Number: MMBT2222LT1G / MMBT2222ALT1G / MMBT2222ALT3G; Provided_By: SUBCO; ECCN_US: EAR99; ECCN_EU: NEC
U6 = MCD-00170: ESD protection 6V1; Part_Type: Diode; Manufacturer: STMICROELECTRONICS; BMS_Part_Number: 9151132; Provided_By: SUBCO with ST control; ECCN_US: EAR99; ECCN_EU: NEC
U7 = MCD-00569: USB3320C,  Hi-Speed USB Host, Device or OTG PHY with ULPI Low Pin Interface; Manufacturer_Part_Number: USB3320C-EZK-TR; Manufacturer: MICROCHIP; Part_Type: IC; Provided_By: SUBCO; ECCN_US: EAR99; ECCN_EU: NEC
U8 = MCD-00251: High power transient voltage suppressor, 7V breakdown; Part_Type: Diode; Manufacturer: STMICROELECTRONICS; BMS_Part_Number: 9179042; Provided_By: SUBCO with ST control; ECCN_US: EAR99; ECCN_EU: NEC
U39 = MCD-00159: 500mA, Enhanced single channel power switches with active high enable pin; Manufacturer: STMICROELECTRONICS; Part_Type: IC; Alternate_Manufacturer_Part_Number: TPS2051C; Alternate_Manufacturer: TEXAS INSTRUMENTS; BMS_Part_Number: 9159009; Provided_By: SUBCO with ST control; ECCN_US: EAR99; ECCN_EU: NEC
U41 = MCD-00649: Common mode filter with ESD protection for USB 2.0 interface; Part_Type: Diode; Manufacturer: STMICROELECTRONICS; BMS_Part_Number: 9151138; Provided_By: SUBCO with ST control; ECCN_US: EAR99; ECCN_EU: NEC
X3 = MCD-01014: Oscillator 24Mhz, +-50ppm, Vcc:3.3V typ, square wave: [0.1Vcc;0.9Vcc], Enable pin; Part_Type: Crystal_Osc; Manufacturer_Part_Number: NZ2520SB 24MHz END4869A; Manufacturer: NDK; Alternate_Manufacturer_Part_Number: AVX Corp/Kyocera Corp; Alternate_Manufacturer: KC2520B24.0000C10E00; BMS_Part_Number: 9157032; Provided_By: SUBCO; ECCN_US: EAR99; ECCN_EU: NEC

## Sheet FDCAN&RS232.SchDoc: FDCAN & OCSPI
size A4; Date: Not used; ApprovedBy: Not used; CheckedBy: Not used; Author: Not used; CompanyName: STMicroelectronics; DrawnBy: Not used; Engineer: Not used; Organization: Not used; Address1: Not used; Address2: Not used; Address3: Not used; Address4: Not used; DocumentNumber: Not used; Revision: Not used; SheetNumber: 15; SheetTotal: 23

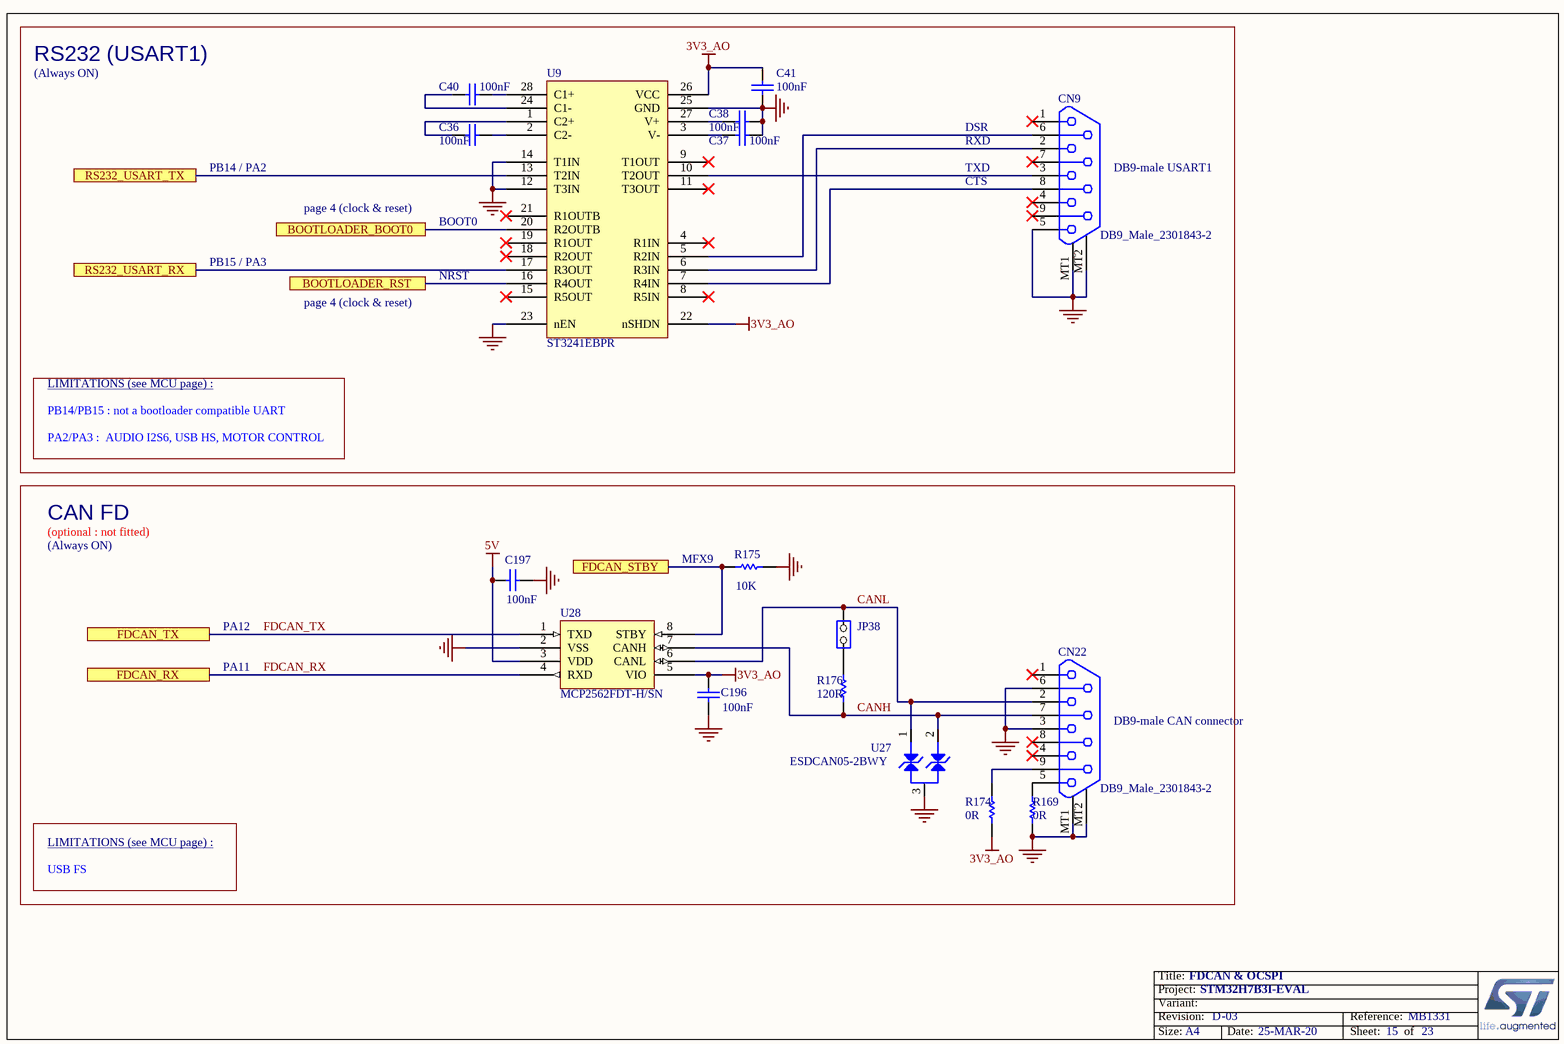
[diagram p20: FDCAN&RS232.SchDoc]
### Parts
C36  value 100nF  [C0402]  (hidden comment: Capacitor)
C37  value 100nF  [C0402]  (hidden comment: Capacitor)
C38  value 100nF  [C0402]  (hidden comment: Capacitor)
C40  value 100nF  [C0402]  (hidden comment: Capacitor)
C41  value 100nF  [C0402]  (hidden comment: Capacitor)
C196  value 100nF  [C0402]  (hidden comment: Capacitor)
C197  value 100nF  [C0402]  (hidden comment: Capacitor)
CN9  value DB9_Male_2301843-2  [CON_DB9-MALE_TYCO_2301843-2]  (hidden comment: DB9_Header_male_2301843-2)
CN22  value DB9_Male_2301843-2  [CON_DB9-MALE_TYCO_2301843-2]  (hidden comment: DB9_Header_male_2301843-2)
JP38  Jumper_Header 2x1  [CON_SAMTEC_TSW-102-07-G-S]  (value not drawn)
R169  value 0R  [R0603]  (hidden comment: Resistor)
R174  value 0R  [R0603]  (hidden comment: Resistor)
R175  value 10K  [R0402]  (hidden comment: Resistor)
R176  value 120R  [R0402]  (hidden comment: Resistor)
U9  ST3241EBPR  [ICC_SSOP28_10P2X5P3_P065]
U27  value ESDCAN05-2BWY  [DIO_SOT323]  (hidden comment: ESD-TRANSIL-DUAL-BIDIR)
U28  value MCP2562FDT-H/SN  [ICC_SO8_5X4_P127]  (hidden comment: MCP2562FD)

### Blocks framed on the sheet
RS232 (USART1): C36-C38 C40 C41 CN9 U9
CAN FD: C196 C197 CN22 JP38 R169 R174-R176 U27 U28

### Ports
BOOTLOADER_BOOT0, BOOTLOADER_RST, FDCAN_RX, FDCAN_STBY, FDCAN_TX, RS232_USART_RX, RS232_USART_TX

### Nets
3V3_AO: C41.1 C196.1 R174.1 U9.22(nSHDN) U9.26(VCC) U28.5(VIO)
5V: C197.1 U28.3(VDD)
GND: C37.1 C38.1 C41.2 C196.2 C197.2 CN9.5 CN9.MT1 CN9.MT2 CN22.3 CN22.6 CN22.MT1 CN22.MT2 R169.1 R175.2 U9.12(T3IN) U9.14(T1IN) U9.23(nEN) U9.25(GND) U27.3 U28.2(VSS)
BOOTLOADER_BOOT0: U9.20(R2OUTB) ; port BOOTLOADER_BOOT0
BOOTLOADER_RST: U9.16(R4OUT) ; port BOOTLOADER_RST
CANH: CN22.7 R176.1 U27.2 U28.7(CANH)
CANL: CN22.2 JP38.2(NO) U27.1 U28.6(CANL)
FDCAN_RX: U28.4(RXD) ; port FDCAN_RX
FDCAN_STBY: R175.1 U28.8(STBY) ; port FDCAN_STBY
FDCAN_TX: U28.1(TXD) ; port FDCAN_TX
RS232_USART_RX: U9.17(R3OUT) ; port RS232_USART_RX
RS232_USART_TX: U9.13(T2IN) ; port RS232_USART_TX
NetC36_1: C36.1 U9.1(C2+)
NetC36_2: C36.2 U9.2(C2-)
NetC37_2: C37.2 U9.3(V-)
NetC38_2: C38.2 U9.27(V+)
NetC40_1: C40.1 U9.24(C1-)
NetC40_2: C40.2 U9.28(C1+)
NetCN9_2: CN9.2 U9.6(R3IN)
NetCN9_3: CN9.3 U9.10(T2OUT)
NetCN9_6: CN9.6 U9.5(R2IN)
NetCN9_8: CN9.8 U9.7(R4IN)
NetCN22_5: CN22.5 R169.2
NetCN22_9: CN22.9 R174.2
NetJP38_1: JP38.1(COMMON) R176.2

Not connected (* = marked no-connect by the designer): CN9 1* 4* 7* 9*; CN22 1* 4* 8*; U9 4(R1IN)* 8(R5IN)* 9(T1OUT)* 11(T3OUT)* 15(R5OUT)* 18(R2OUT)* 19(R1OUT)* 21(R1OUTB)*

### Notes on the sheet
- (Always ON)
- PB14 / PA2
- RXD
- TXD
- CTS
- DSR
- (near CN9) DB9-male USART1
- page 4 (clock & reset)
- BOOT0
- PB15 / PA3
- NRST
- LIMITATIONS (see MCU page) :
- PB14/PB15 : not a bootloader compatible UART
- PA2/PA3 :  AUDIO I2S6, USB HS, MOTOR CONTROL
- (optional : not fitted)
- (near R175) MFX9
- PA12
- PA11
- (near CN22) DB9-male CAN connector
- USB FS

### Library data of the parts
C36-C38 C40 C41 C196 C197 = MCD-00006: as C32 on sheet USB_OTG_HS_externalPHY
CN9 CN22 = MCD-01978: DB9_Male, RA, TH, height 13.575mm/3.8mm; Part_Type: Connector; Manufacturer: TYCO; ECCN_US: EAR99; ECCN_EU: NEC; Provided_By: SUBCO
JP38 = MCD-00045: Header, 2x1, 2,54mm, VR, TH, Height 5.84mm/2.54mm; Manufacturer_Part_Number: TSW-102-07-x-S; Manufacturer: SAMTEC; Part_Type: Connector; Alternate_Manufacturer_Part_Number: 313102S111116;313102S111116; Alternate_Manufacturer: JIUBABA; LIANYI; Value: Shunt not fitted; Provided_By: SUBCO
R169 R174 = MCD-00056: as R17-R19 on sheet USB_OTG_HS_externalPHY
R175 = MCD-00053: as R28 on sheet USB_OTG_HS_externalPHY
R176 = MCD-00194: Resistor,120R,0402,1%,1/16W; Manufacturer_Part_Number: RC0402FR-07120RL; Manufacturer: YAGEO; Provided_By: SUBCO; ECCN_US: EAR99; ECCN_EU: NEC
U9 = MCD-00152: RS-232 transceiver with auto-power-down; Part_Type: IC; Manufacturer: STMICROELECTRONICS; BMS_Part_Number: 9176312; Provided_By: SUBCO with ST control; ECCN_US: EAR99; ECCN_EU: NEC
U27 = MCD-01358: Automotive dual-line Transil, transient voltage suppressor (TVS) for CAN bus 36V. Compliant with interfaces in automotive: CAN-FD, LIN, FlexRay, MOST, SENT, USB; Part_Type: Diode; Manufacturer: STMICROELECTRONICS; BMS_Part_Number: 9179021; Provided_By: SUBCO with ST control; ECCN_US: EAR99; ECCN_EU: NEC
U28 = MCD-00129: High-Speed CAN Flexible Data Rate Transceiver; Manufacturer: MICROCHIP; Part_Type: IC; Provided_By: SUBCO; ECCN_US: EAR99; ECCN_EU: NEC

## Sheet STMPS2&PT100.SchDoc: STMPS2&PT100
size A4; Date: Not used; ApprovedBy: Not used; CheckedBy: Not used; Author: Not used; CompanyName: STMicroelectronics; DrawnBy: Not used; Engineer: Not used; Organization: Not used; Address1: Not used; Address2: Not used; Address3: Not used; Address4: Not used; DocumentNumber: Not used; Revision: Not used; SheetNumber: 16; SheetTotal: 23

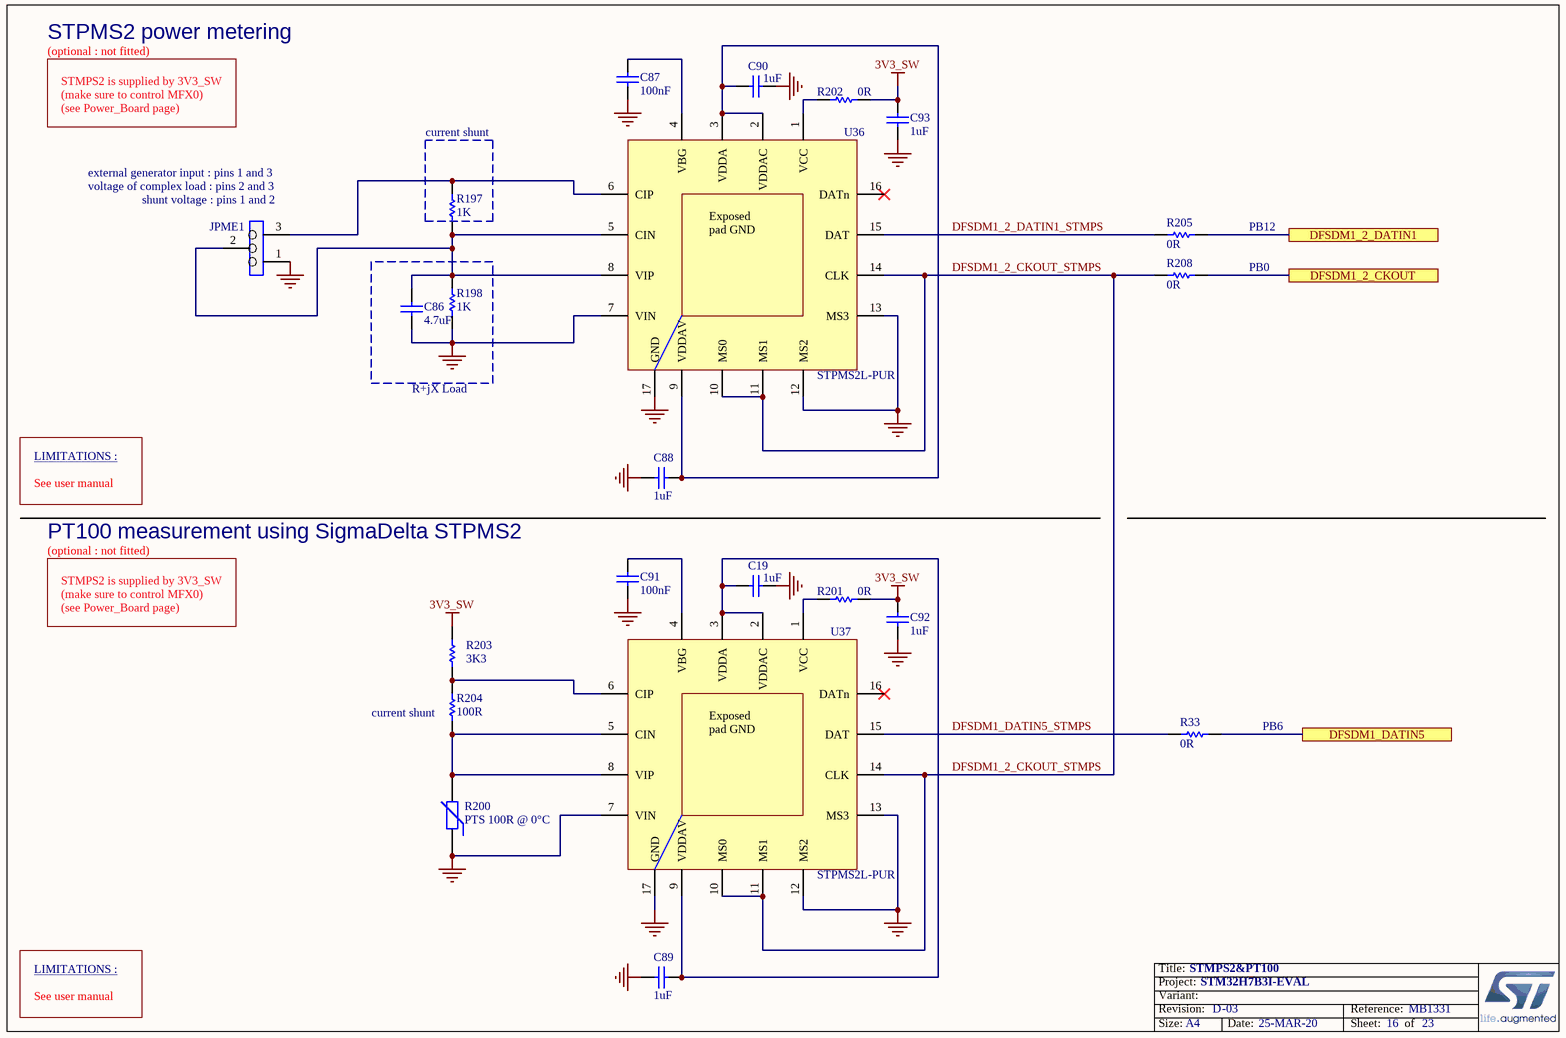
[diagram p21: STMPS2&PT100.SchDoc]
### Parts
C19  value 1uF  [C0402]  (hidden comment: Capacitor)
C86  value 4.7uF  [C0402]  (hidden comment: Capacitor)
C87  value 100nF  [C0402]  (hidden comment: Capacitor)
C88  value 1uF  [C0603]  (hidden comment: Capacitor)
C89  value 1uF  [C0603]  (hidden comment: Capacitor)
C90  value 1uF  [C0402]  (hidden comment: Capacitor)
C91  value 100nF  [C0402]  (hidden comment: Capacitor)
C92  value 1uF  [C0402]  (hidden comment: Capacitor)
C93  value 1uF  [C0402]  (hidden comment: Capacitor)
JPME1  Jumper_Header 3x1  [CON_SAMTEC_TSW-103-07-F-S]  (value not drawn)
R33  value 0R  [R0402]  (hidden comment: Resistor)
R197  value 1K  [R0603]  (hidden comment: Resistor)
R198  value 1K  [R0603]  (hidden comment: Resistor)
R200  value PTS 100R @ 0°C  [R0603_H0P45]  (hidden comment: PT100)
R201  value 0R  [R0603]  (hidden comment: Resistor)
R202  value 0R  [R0603]  (hidden comment: Resistor)
R203  value 3K3  [R0603]  (hidden comment: Resistor)
R204  value 100R  [R0603]  (hidden comment: Resistor)
R205  value 0R  [R0402]  (hidden comment: Resistor)
R208  value 0R  [R0402]  (hidden comment: Resistor)
U36  STPMS2L-PUR  [ICC_QFN16-EPAD_4X4_P065]
U37  STPMS2L-PUR  [ICC_QFN16-EPAD_4X4_P065]

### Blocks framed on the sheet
current shunt: R197

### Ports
DFSDM1_2_CKOUT, DFSDM1_2_DATIN1, DFSDM1_DATIN5

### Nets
3V3_SW: C92.1 C93.1 R201.2 R202.2 R203.2
GND: C19.1 C86.1 C87.1 C88.1 C89.1 C90.1 C91.1 C92.2 C93.2 JPME1.1 R198.1 R200.1 U36.7(VIN) U36.12(MS2) U36.13(MS3) U36.17(GND) U37.7(VIN) U37.12(MS2) U37.13(MS3) U37.17(GND)
DFSDM1_2_CKOUT: R208.2 ; port DFSDM1_2_CKOUT
DFSDM1_2_CKOUT_STMPS: R208.1 U36.10(MS0) U36.11(MS1) U36.14(CLK) U37.10(MS0) U37.11(MS1) U37.14(CLK)
DFSDM1_2_DATIN1: R205.2 ; port DFSDM1_2_DATIN1
DFSDM1_2_DATIN1_STMPS: R205.1 U36.15(DAT)
DFSDM1_DATIN5: R33.2 ; port DFSDM1_DATIN5
DFSDM1_DATIN5_STMPS: R33.1 U37.15(DAT)
NetC19_2: C19.2 C89.2 U37.2(VDDAC) U37.3(VDDA) U37.9(VDDAV)
NetC86_2: C86.2 JPME1.2 R197.1 R198.2 U36.5(CIN) U36.8(VIP)
NetC87_2: C87.2 U36.4(VBG)
NetC88_2: C88.2 C90.2 U36.2(VDDAC) U36.3(VDDA) U36.9(VDDAV)
NetC91_2: C91.2 U37.4(VBG)
NetJPME1_3: JPME1.3 R197.2 U36.6(CIP)
NetR200_2: R200.2 R204.1 U37.5(CIN) U37.8(VIP)
NetR201_1: R201.1 U37.1(VCC)
NetR202_1: R202.1 U36.1(VCC)
NetR203_1: R203.1 R204.2 U37.6(CIP)

Not connected (* = marked no-connect by the designer): U36 16(DATn)*; U37 16(DATn)*

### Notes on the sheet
- STPMS2 power metering
- (optional : not fitted)
- STMPS2 is supplied by 3V3_SW
  (make sure to control MFX0)
  (see Power_Board page)
- external generator input : pins 1 and 3
- (near JPME1) voltage of complex load : pins 2 and 3
- (near JPME1) shunt voltage : pins 1 and 2
- PB12
- PB0
- R+jX Load
- LIMITATIONS :
- See user manual
- PT100 measurement using SigmaDelta STPMS2
- (near R204) current shunt
- PB6

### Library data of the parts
C19 C90 C92 C93 = MCD-00095: Capacitor, MLCC, 1uF, 6V3, X5R, 10%, 0402, T=0,5mm; Manufacturer_Part_Number: GRM155R61E105KA12; Manufacturer: MURATA; Alternate_Manufacturer_Part_Number: GRM155R60J105KE19; Provided_By: SUBCO; ECCN_US: EAR99; ECCN_EU: NEC
C86 = MCD-01356: Capacitor, MLCC, 4.7uF, 6V3, X5R, 20%, 0402, T=0,5mm; Manufacturer_Part_Number: GRM155R60J475ME47; Manufacturer: MURATA; ECCN_US: EAR99; ECCN_EU: NEC; Provided_By: SUBCO
C87 C91 = MCD-00006: as C32 on sheet USB_OTG_HS_externalPHY
C88 C89 = MCD-00010: Capacitor, MLCC, 1uF, 16V, X5R, 10%, 0603, T=0,8mm; Manufacturer_Part_Number: CC0603KRX5R7BB105; Manufacturer: YAGEO; Provided_By: SUBCO; ECCN_US: EAR99; ECCN_EU: NEC
JPME1 = MCD-00111: Header, 3x1, 2,54mm, VR, TH, Height 5.84mm/2.54mm; Manufacturer_Part_Number: TSW-103-07-F-S; Manufacturer: SAMTEC; Part_Type: Connector; Provided_By: SUBCO; ECCN_US: EAR99; ECCN_EU: NEC
R33 R205 R208 = MCD-00052: as R39 on sheet USB_OTG_HS_externalPHY
R197 R198 = MCD-00070: Resistor,1K,0603,1%,1/10W; Manufacturer_Part_Number: RC0603FR-071KL; Manufacturer: YAGEO; Provided_By: SUBCO; ECCN_US: EAR99; ECCN_EU: NEC
R200 = MCD-00680: Resistor, SMD PTS 100ohm @ 0°C Flat Chip Temperature Sensor; Manufacturer_Part_Number: PTS060301B100RP100; Manufacturer: VISHAY; Provided_By: SUBCO; ECCN_US: EAR99; ECCN_EU: NEC
R201 R202 = MCD-00056: as R17-R19 on sheet USB_OTG_HS_externalPHY
R203 = MCD-00352: Resistor,3K3,0603,1%,1/10W; Manufacturer_Part_Number: RC0603FR-073K3L; Manufacturer: YAGEO; Provided_By: SUBCO; ECCN_US: EAR99; ECCN_EU: NEC
R204 = MCD-00224: Resistor,100R,0603,1%,1/10W; Manufacturer_Part_Number: RC0603FR-07100RL; Manufacturer: YAGEO; Provided_By: SUBCO; ECCN_US: EAR99; ECCN_EU: NEC
U36 U37 = MCD-00681: Smart sensor II dual-channel 1-bit, 4 MHz, second-order sigmadelta modulator with embedded PGLNA; Part_Type: IC; Manufacturer: STMICROELECTRONICS; BMS_Part_Number: 9177717; Provided_By: SUBCO with ST control; ECCN_US: EAR99; ECCN_EU: NEC

## Sheet Power_MCU.SchDoc: MCU Power
size A4; Date: Not used; ApprovedBy: Not used; CheckedBy: Not used; Author: Not used; CompanyName: STMicroelectronics; DrawnBy: Not used; Engineer: Not used; Organization: Not used; Address1: Not used; Address2: Not used; Address3: Not used; Address4: Not used; DocumentNumber: Not used; Revision: Not used; SheetNumber: 21; SheetTotal: 23

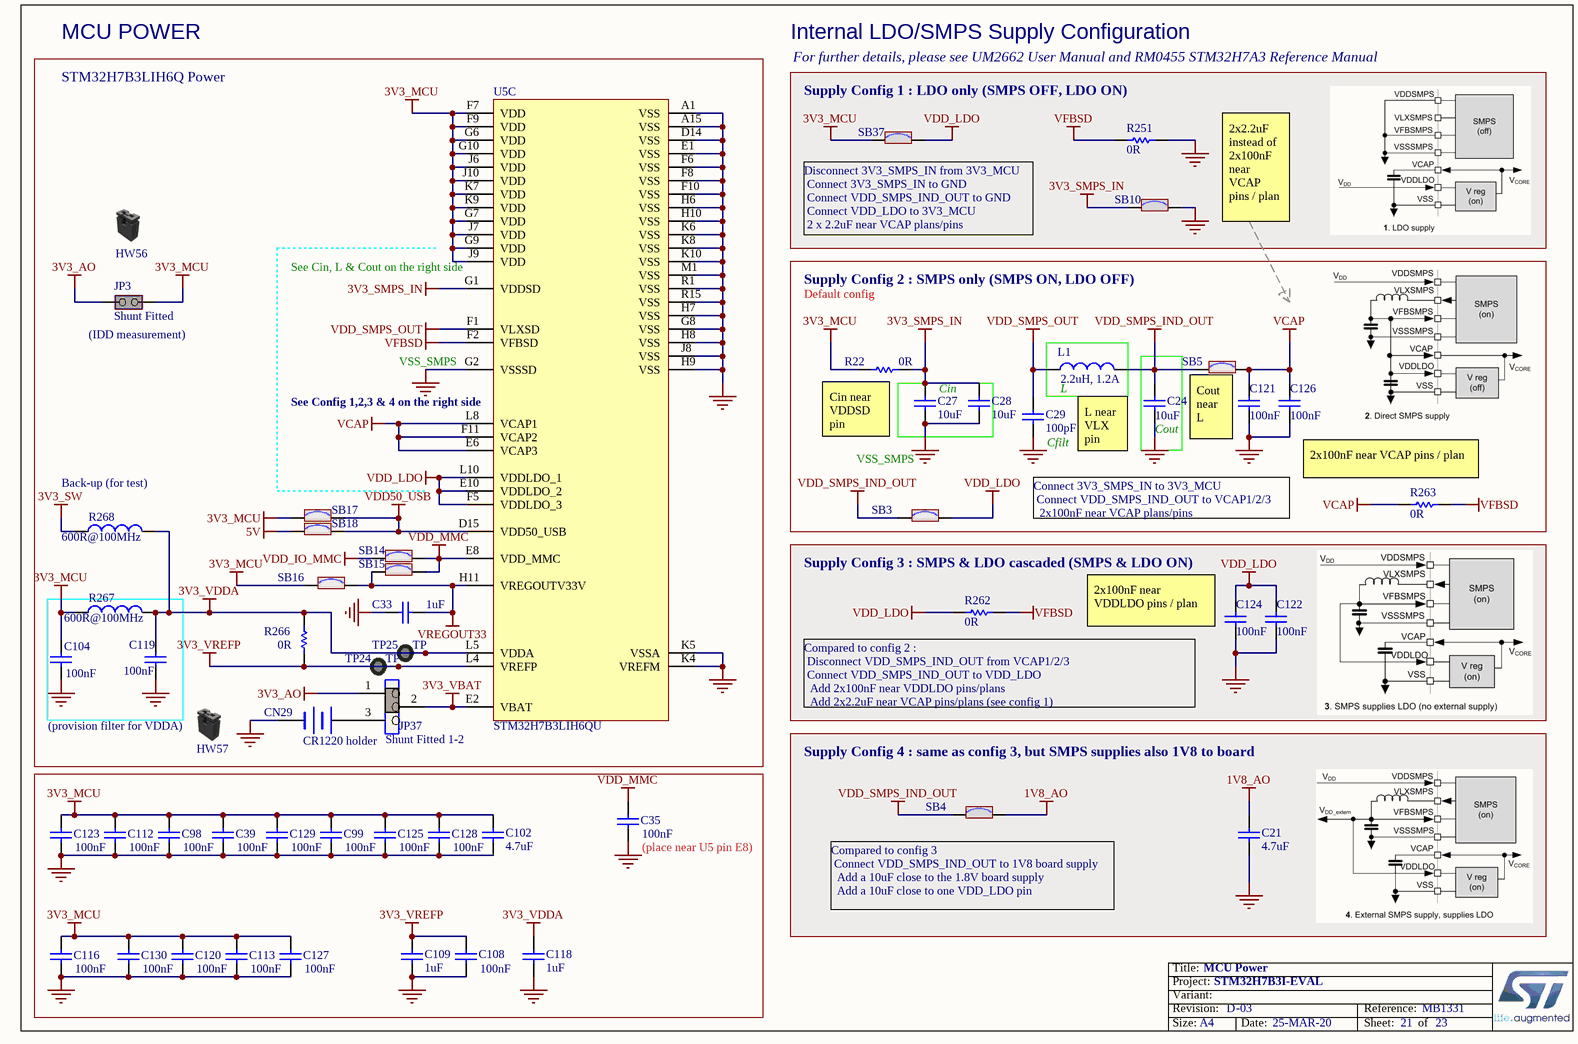
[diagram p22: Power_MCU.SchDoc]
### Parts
C21  value 4.7uF  [C0603]  (hidden comment: Capacitor)
C24  value 10uF  [C0603]  (hidden comment: Capacitor)
C27  value 10uF  [C0402]  (hidden comment: Capacitor)
C28  value 10uF  [C0402]  (hidden comment: Capacitor)
C29  value 100pF  [C0402]  (hidden comment: Capacitor)
C33  value 1uF  [C0603]  (hidden comment: Capacitor)
C35  value 100nF  [C0402]  (hidden comment: Capacitor)
C39  value 100nF  [C0402]  (hidden comment: Capacitor)
C98  value 100nF  [C0402]  (hidden comment: Capacitor)
C99  value 100nF  [C0402]  (hidden comment: Capacitor)
C102  value 4.7uF  [C0603]  (hidden comment: Capacitor)
C104  value 100nF  [C0402]  (hidden comment: Capacitor)
C108  value 100nF  [C0402]  (hidden comment: Capacitor)
C109  value 1uF  [C0402]  (hidden comment: Capacitor)
C112  value 100nF  [C0402]  (hidden comment: Capacitor)
C113  value 100nF  [C0402]  (hidden comment: Capacitor)
C116  value 100nF  [C0402]  (hidden comment: Capacitor)
C118  value 1uF  [C0402]  (hidden comment: Capacitor)
C119  value 100nF  [C0402]  (hidden comment: Capacitor)
C120  value 100nF  [C0402]  (hidden comment: Capacitor)
C121  value 100nF  [C0402]  (hidden comment: Capacitor)
C122  value 100nF  [C0402]  (hidden comment: Capacitor)
C123  value 100nF  [C0402]  (hidden comment: Capacitor)
C124  value 100nF  [C0402]  (hidden comment: Capacitor)
C125  value 100nF  [C0402]  (hidden comment: Capacitor)
C126  value 100nF  [C0402]  (hidden comment: Capacitor)
C127  value 100nF  [C0402]  (hidden comment: Capacitor)
C128  value 100nF  [C0402]  (hidden comment: Capacitor)
C129  value 100nF  [C0402]  (hidden comment: Capacitor)
C130  value 100nF  [C0402]  (hidden comment: Capacitor)
CN29  value CR1220 holder  [BAT_HARWIN_S8411-45R_SMD_2P]  (hidden comment: BATTERY HOLDER)
HW56  Shunt Black 2.54mm  (value not drawn)  (mechanical)
HW57  Shunt Black 2.54mm  (value not drawn)  (mechanical)
JP3  value Shunt Fitted  [CON_SAMTEC_TSW-102-07-G-S]  (hidden comment: Jumper_Header 2x1 Fitted)
JP37  value Shunt Fitted 1-2  [CON_SAMTEC_TSW-103-07-F-S]  (hidden comment: Jumper_Header 3x1 Fitted 1-2)
L1  value 2.2uH, 1.2A  [L0805_H0P9]  (hidden comment: Inductor)
R22  value 0R  [R0603]  (hidden comment: Resistor)
R251  value 0R  [R0402]  (hidden comment: Resistor)
R262  value 0R  [R0402]  (hidden comment: Resistor)
R263  value 0R  [R0402]  (hidden comment: Resistor)
R266  value 0R  [R0603]  (hidden comment: Resistor)
R267  value 600R@100MHz  [L0603]  (hidden comment: BEAD)
R268  value 600R@100MHz  [L0603]  (hidden comment: BEAD)
SB3  SB_ON  [SOLDER-BRIDGE_R0603-0R]  (value not drawn)
SB4  SB_ON  [SOLDER-BRIDGE_R0603-0R]  (value not drawn)
SB5  SB_ON  [SOLDER-BRIDGE_R0603-0R]  (value not drawn)
SB10  SB_ON  [SOLDER-BRIDGE_R0603-0R]  (value not drawn)
SB14  SB_ON  [SOLDER-BRIDGE_R0603-0R]  (value not drawn)
SB15  SB_ON  [SOLDER-BRIDGE_R0603-0R]  (value not drawn)
SB16  SB_ON  [SOLDER-BRIDGE_R0603-0R]  (value not drawn)
SB17  SB_ON  [SOLDER-BRIDGE_R0603-0R]  (value not drawn)
SB18  SB_ON  [SOLDER-BRIDGE_R0603-0R]  (value not drawn)
SB37  SB_ON  [SOLDER-BRIDGE_R0603-0R]  (value not drawn)
TP24  value TP  [TP_PTH_1MM_2MM]  (hidden comment: Test_Point_PTH_1mm_2mm)  (no BOM)
TP25  value TP  [TP_PTH_1MM_2MM]  (hidden comment: Test_Point_PTH_1mm_2mm)  (no BOM)
U5  value STM32H7B3LIH6QU  [ICC_TFBGA225_13X13_STM32H7B3NIH6Q_P080__SOCKET_IRONWOOD_CS1222291MF_REV-A_WITHOUT-3D-SOCKET]  (hidden comment: STM32H7B3NIH6Q)  (part C of 3)

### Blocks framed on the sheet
MCU POWER: C33 C104 C119 CN29 HW56 HW57 JP3 JP37 R266-R268 SB14-SB18 TP24 TP25 U5
Supply Config 1 : LDO only (SMPS OFF, LDO ON): R251 SB10 SB37
Supply Config 2 : SMPS only (SMPS ON, LDO OFF): C29 C121 C126 R22 R263 SB3 SB5
L: L1
Cin: C27 C28
Cout: C24
Supply Config 3 : SMPS & LDO cascaded (SMPS & LDO ON): C122 C124 R262
(place near U5 pin E8): C35 C39 C98 C99 C102 C108 C109 C112 C113 C116 C118 C120 C123 C125 C127-C130

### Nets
1V8_AO: C21.2 SB4.2
3V3_AO: JP3.1(COMMON) JP37.1
3V3_MCU: C39.1 C98.1 C99.1 C102.2 C104.1 C112.1 C113.1 C116.1 C120.1 C123.1 C125.1 C127.1 C128.1 C129.1 C130.1 JP3.2(NO) R22.2 R267.1 SB16.1 SB17.2 SB37.2 U5.F7(VDD) U5.F9(VDD) U5.G6(VDD) U5.G7(VDD) U5.G9(VDD) U5.G10(VDD) U5.J6(VDD) U5.J7(VDD) U5.J9(VDD) U5.J10(VDD) U5.K7(VDD) U5.K9(VDD)
3V3_SMPS_IN: C27.2 C28.2 R22.1 SB10.2 U5.G1(VDDSD)
3V3_SW: R268.1
3V3_VBAT: JP37.2 U5.E2(VBAT)
3V3_VDDA: C118.2 C119.1 R266.1 R267.2 R268.2 TP25.1 U5.L5(VDDA)
3V3_VREFP: C108.2 C109.2 R266.2 TP24.1 U5.L4(VREFP)
5V: SB18.2
GND: C21.1 C24.1 C27.1 C28.1 C29.1 C33.2 C35.2 C39.2 C98.2 C99.2 C102.1 C104.2 C108.1 C109.1 C112.2 C113.2 C116.2 C118.1 C119.2 C120.2 C121.2 C122.2 C123.2 C124.2 C125.2 C126.2 C127.2 C128.2 C129.2 C130.2 CN29.2(-) R251.2 SB10.1 U5.A1(VSS) U5.A15(VSS) U5.D14(VSS) U5.E1(VSS) U5.F6(VSS) U5.F8(VSS) U5.F10(VSS) U5.G2(VSSSD) U5.G8(VSS) U5.H6(VSS) U5.H7(VSS) U5.H8(VSS) U5.H9(VSS) U5.H10(VSS) U5.J8(VSS) U5.K4(VREFM) U5.K5(VSSA) U5.K6(VSS) U5.K8(VSS) U5.K10(VSS) U5.M1(VSS) U5.R1(VSS) U5.R15(VSS)
VCAP: C121.1 C126.1 R263.1 SB5.1 U5.E6(VCAP3) U5.F11(VCAP2) U5.L8(VCAP1)
VDD50_USB: SB17.1 SB18.1 U5.D15(VDD50_USB)
VDD_IO_MMC: SB14.1
VDD_LDO: C122.1 C124.1 R262.1 SB3.1 SB37.1 U5.E10(VDDLDO_2) U5.F5(VDDLDO_3) U5.L10(VDDLDO_1)
VDD_MMC: C35.1 SB14.2 SB15.1 U5.E8(VDD_MMC)
VDD_SMPS_IND_OUT: C24.2 L1.2 SB3.2 SB4.1 SB5.2
VDD_SMPS_OUT: C29.2 L1.1 U5.F1(VLXSD)
VFBSD: R251.1 R262.2 R263.2 U5.F2(VFBSD)
VREGOUT33: C33.1 SB15.2 SB16.2 U5.H11(VREGOUTV33V)
NetCN29_1: CN29.1(+) JP37.3

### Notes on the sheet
- Internal LDO/SMPS Supply Configuration
- STM32H7B3LIH6Q Power
- For further details, please see UM2662 User Manual and RM0455 STM32H7A3 Reference Manual
- (near SB37) Disconnect 3V3_SMPS_IN from 3V3_MCU
  Connect 3V3_SMPS_IN to GND
  Connect VDD_SMPS_IND_OUT to GND
  Connect VDD_LDO to 3V3_MCU
  2 x 2.2uF near VCAP plans/pins
- 2x2.2uF instead of 2x100nF near VCAP pins / plan
- (near U5) See Cin, L & Cout on the right side
- Default config
- (near JP3) (IDD measurement)
- (near U5) VSS_SMPS
- (near U5) See Config 1,2,3 & 4 on the right side
- (near R22) Cin near VDDSD pin
- (near C29) Cfilt
- L near VLX pin
- (near SB5) Cout near L
- (near R268) Back-up (for test)
- VSS_SMPS
- Connect 3V3_SMPS_IN to 3V3_MCU
  Connect VDD_SMPS_IND_OUT to VCAP1/2/3
  2x100nF near VCAP plans/pins
- 2x100nF near VCAP pins / plan
- (near C124) 2x100nF near VDDLDO pins / plan
- Compared to config 2 :
  Disconnect VDD_SMPS_IND_OUT from VCAP1/2/3
  Connect VDD_SMPS_IND_OUT to VDD_LDO
  Add 2x100nF near VDDLDO pins/plans
  Add 2x2.2uF near VCAP pins/plans (see config 1)
- (near HW57) (provision filter for VDDA)
- Supply Config 4 : same as config 3, but SMPS supplies also 1V8 to board
- (near SB4) Compared to config 3
  Connect VDD_SMPS_IND_OUT to 1V8 board supply
  Add a 10uF close to the 1.8V board supply
  Add a 10uF close to one VDD_LDO pin

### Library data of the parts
C21 C102 = MCD-01121: Capacitor, MLCC, 4.7uF, 10V, X5R, 20%, 0603, T=0,8mm; Manufacturer_Part_Number: GRM188R61A475ME15; Manufacturer: MURATA; Provided_By: SUBCO; ECCN_US: EAR99; ECCN_EU: NEC
C24 = MCD-01341: Capacitor, MLCC, 10uF, 6V3, X5R, 20%, 0603, T=0,8mm; Manufacturer_Part_Number: GRM188R60J106ME47D; Manufacturer: MURATA; Provided_By: SUBCO; ECCN_US: EAR99; ECCN_EU: NEC
C27 C28 = MCD-01716: Capacitor, MLCC, 10uF, 6V3, X5R, 20%, 0402, T=0.5mm; Manufacturer_Part_Number: CC0402MRX5R5BB106; Manufacturer: YAGEO; Provided_By: SUBCO
C29 = MCD-00205: Capacitor, MLCC, 100pF, 50V, NPO, 5%, 0402, T=0,5mm; Manufacturer_Part_Number: CC0402JRNPO9BN101; Manufacturer: YAGEO; Provided_By: SUBCO; ECCN_US: EAR99; ECCN_EU: NEC
C33 = MCD-00010: as C88 on sheet STMPS2&PT100
C35 C39 C98 C99 C104 C108 C112 C113 C116 C119-C130 = MCD-00006: as C32 on sheet USB_OTG_HS_externalPHY
C109 C118 = MCD-00095: as C19 on sheet STMPS2&PT100
CN29 = MCD-00558: Battery Coin Cell holder, CR1220_12mm, Height 4.25mm; Part_Type: Connector; Manufacturer_Part_Number: S8411-45R; Manufacturer: HARWIN; Provided_By: SUBCO
HW56 HW57 = MCD-00043: SHUNT 2.54mm BLACK; Part_Type: Mechanical; Manufacturer: SAMTEC; Alternate_Manufacturer_Part_Number: 316102S111A; Alternate_Manufacturer: JIUBABA; Value: SNT-100-BK-G; Provided_By: SUBCO
JP3 = MCD-00683: Header, 2x1, 2,54mm, VR, TH, Height 5.84mm/2.54mm - Shunt Fitted by default; Part_Type: Connector; Manufacturer_Part_Number: TSW-102-07-x-S; Manufacturer: SAMTEC; Alternate_Manufacturer_Part_Number: 313102S111116; Alternate_Manufacturer: LIANYI; Provided_By: SUBCO
JP37 = MCD-00684: Header, 3x1, 2,54mm, VR, TH, Height 5.84mm/2.54mm - Shunt Fitted 1-2 by default; Part_Type: Connector; Manufacturer_Part_Number: TSW-103-07-F-S; Manufacturer: SAMTEC; Provided_By: SUBCO
L1 = MCD-01340: Inductor, 2.2uH, 20%, Isat 1.2A, DCR 0.228Ohm, 0805; Manufacturer_Part_Number: DFE201210U-2R2M=P2; Manufacturer: MURATA; Provided_By: SUBCO
R22 R266 = MCD-00056: as R17-R19 on sheet USB_OTG_HS_externalPHY
R251 R262 R263 = MCD-00052: as R39 on sheet USB_OTG_HS_externalPHY
R267 R268 = MCD-00047: SMD Chip ferrite bead, 600R@100MHz +/-25%, 350mA, 500mohm DC, 0603, T=0.8mm; Part_Type: Inductor; Manufacturer_Part_Number: FCM1608KF-601T03; Manufacturer: TAI-TECH; Provided_By: SUBCO
SB3-SB5 SB10 SB14-SB18 SB37 = MCD-00071: as SB11-SB13 on sheet USB_OTG_HS_externalPHY
TP24 TP25 = MCD-01506: Test Point trought hole 1mm/2mm; Part_Type: Mechanical
U5 = MCD-01930: STM32H7B3LIH6QU (crypto),TFBGA 225, 13x13 0.8 with footprint for socket IRONWOOD CS1222291MF; Part_Type: IC; Manufacturer: STMICROELECTRONICS; BMS_Part_Number: 9175362; ECCN_US: 5A992C; ECCN_EU: 5A002A4; Provided_By: SUBCO with ST control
